VERSION 5.8 ;
BUSBITCHARS "[]" ;
DIVIDERCHAR "/" ;
UNITS
    DATABASE MICRONS 1000 ;
END UNITS

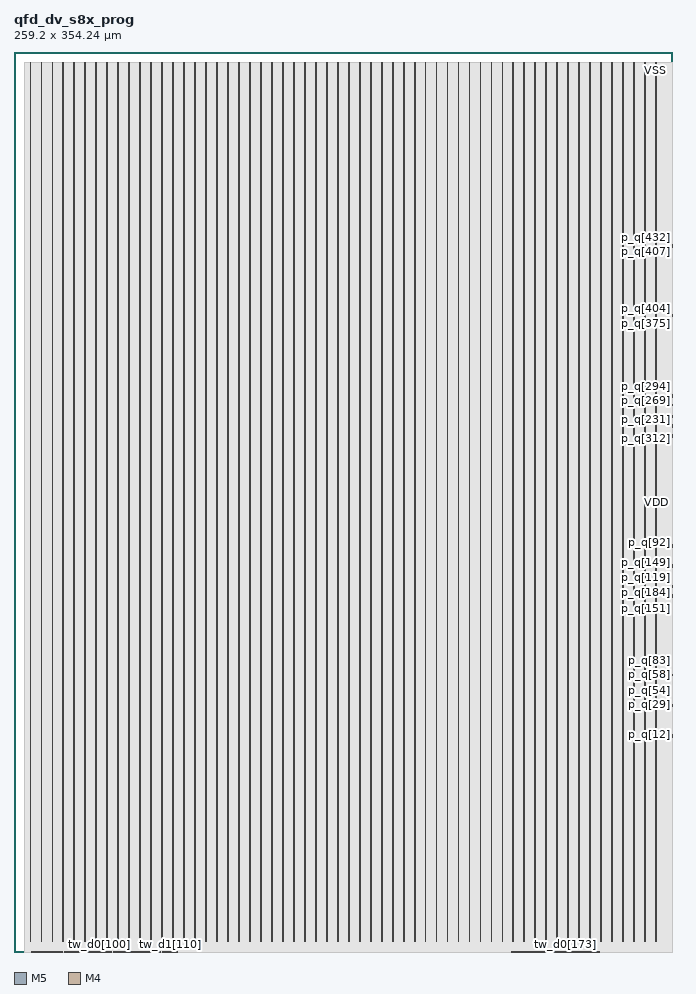
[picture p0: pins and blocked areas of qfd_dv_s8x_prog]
MACRO qfd_dv_s8x_prog
  FOREIGN qfd_dv_s8x_prog 0 0 ;
  CLASS BLOCK ;
  SIZE 259.2 BY 354.24 ;
  PIN ck
    DIRECTION INPUT ;
    USE SIGNAL ;
    PORT
      LAYER M5 ;
        RECT  35.28 0 35.304 0.084 ;
    END
  END ck
  PIN p_idx[0]
    DIRECTION INPUT ;
    USE SIGNAL ;
    PORT
      LAYER M4 ;
        RECT  259.116 83.664 259.2 83.688 ;
    END
  END p_idx[0]
  PIN p_idx[1]
    DIRECTION INPUT ;
    USE SIGNAL ;
    PORT
      LAYER M4 ;
        RECT  259.116 83.76 259.2 83.784 ;
    END
  END p_idx[1]
  PIN p_idx[2]
    DIRECTION INPUT ;
    USE SIGNAL ;
    PORT
      LAYER M4 ;
        RECT  259.116 83.856 259.2 83.88 ;
    END
  END p_idx[2]
  PIN p_idx[3]
    DIRECTION INPUT ;
    USE SIGNAL ;
    PORT
      LAYER M4 ;
        RECT  259.116 83.952 259.2 83.976 ;
    END
  END p_idx[3]
  PIN p_idx[4]
    DIRECTION INPUT ;
    USE SIGNAL ;
    PORT
      LAYER M4 ;
        RECT  259.116 84.048 259.2 84.072 ;
    END
  END p_idx[4]
  PIN p_idx[5]
    DIRECTION INPUT ;
    USE SIGNAL ;
    PORT
      LAYER M4 ;
        RECT  259.116 84.144 259.2 84.168 ;
    END
  END p_idx[5]
  PIN p_idx[6]
    DIRECTION INPUT ;
    USE SIGNAL ;
    PORT
      LAYER M4 ;
        RECT  259.116 84.24 259.2 84.264 ;
    END
  END p_idx[6]
  PIN p_idx[7]
    DIRECTION INPUT ;
    USE SIGNAL ;
    PORT
      LAYER M4 ;
        RECT  259.116 84.336 259.2 84.36 ;
    END
  END p_idx[7]
  PIN p_idx[8]
    DIRECTION INPUT ;
    USE SIGNAL ;
    PORT
      LAYER M4 ;
        RECT  259.116 84.432 259.2 84.456 ;
    END
  END p_idx[8]
  PIN p_q[0]
    DIRECTION OUTPUT ;
    USE SIGNAL ;
    PORT
      LAYER M4 ;
        RECT  259.116 84.528 259.2 84.552 ;
    END
  END p_q[0]
  PIN p_q[100]
    DIRECTION OUTPUT ;
    USE SIGNAL ;
    PORT
      LAYER M4 ;
        RECT  259.116 158.64 259.2 158.664 ;
    END
  END p_q[100]
  PIN p_q[101]
    DIRECTION OUTPUT ;
    USE SIGNAL ;
    PORT
      LAYER M4 ;
        RECT  259.116 158.736 259.2 158.76 ;
    END
  END p_q[101]
  PIN p_q[102]
    DIRECTION OUTPUT ;
    USE SIGNAL ;
    PORT
      LAYER M4 ;
        RECT  259.116 158.832 259.2 158.856 ;
    END
  END p_q[102]
  PIN p_q[103]
    DIRECTION OUTPUT ;
    USE SIGNAL ;
    PORT
      LAYER M4 ;
        RECT  259.116 158.928 259.2 158.952 ;
    END
  END p_q[103]
  PIN p_q[104]
    DIRECTION OUTPUT ;
    USE SIGNAL ;
    PORT
      LAYER M4 ;
        RECT  259.116 159.024 259.2 159.048 ;
    END
  END p_q[104]
  PIN p_q[105]
    DIRECTION OUTPUT ;
    USE SIGNAL ;
    PORT
      LAYER M4 ;
        RECT  259.116 159.12 259.2 159.144 ;
    END
  END p_q[105]
  PIN p_q[106]
    DIRECTION OUTPUT ;
    USE SIGNAL ;
    PORT
      LAYER M4 ;
        RECT  259.116 159.216 259.2 159.24 ;
    END
  END p_q[106]
  PIN p_q[107]
    DIRECTION OUTPUT ;
    USE SIGNAL ;
    PORT
      LAYER M4 ;
        RECT  259.116 159.312 259.2 159.336 ;
    END
  END p_q[107]
  PIN p_q[108]
    DIRECTION OUTPUT ;
    USE SIGNAL ;
    PORT
      LAYER M4 ;
        RECT  259.116 159.408 259.2 159.432 ;
    END
  END p_q[108]
  PIN p_q[109]
    DIRECTION OUTPUT ;
    USE SIGNAL ;
    PORT
      LAYER M4 ;
        RECT  259.116 159.504 259.2 159.528 ;
    END
  END p_q[109]
  PIN p_q[10]
    DIRECTION OUTPUT ;
    USE SIGNAL ;
    PORT
      LAYER M4 ;
        RECT  259.116 85.488 259.2 85.512 ;
    END
  END p_q[10]
  PIN p_q[110]
    DIRECTION OUTPUT ;
    USE SIGNAL ;
    PORT
      LAYER M4 ;
        RECT  259.116 159.6 259.2 159.624 ;
    END
  END p_q[110]
  PIN p_q[111]
    DIRECTION OUTPUT ;
    USE SIGNAL ;
    PORT
      LAYER M4 ;
        RECT  259.116 159.696 259.2 159.72 ;
    END
  END p_q[111]
  PIN p_q[112]
    DIRECTION OUTPUT ;
    USE SIGNAL ;
    PORT
      LAYER M4 ;
        RECT  259.116 159.792 259.2 159.816 ;
    END
  END p_q[112]
  PIN p_q[113]
    DIRECTION OUTPUT ;
    USE SIGNAL ;
    PORT
      LAYER M4 ;
        RECT  259.116 159.888 259.2 159.912 ;
    END
  END p_q[113]
  PIN p_q[114]
    DIRECTION OUTPUT ;
    USE SIGNAL ;
    PORT
      LAYER M4 ;
        RECT  259.116 159.984 259.2 160.008 ;
    END
  END p_q[114]
  PIN p_q[115]
    DIRECTION OUTPUT ;
    USE SIGNAL ;
    PORT
      LAYER M4 ;
        RECT  259.116 160.08 259.2 160.104 ;
    END
  END p_q[115]
  PIN p_q[116]
    DIRECTION OUTPUT ;
    USE SIGNAL ;
    PORT
      LAYER M4 ;
        RECT  259.116 160.176 259.2 160.2 ;
    END
  END p_q[116]
  PIN p_q[117]
    DIRECTION OUTPUT ;
    USE SIGNAL ;
    PORT
      LAYER M4 ;
        RECT  259.116 160.272 259.2 160.296 ;
    END
  END p_q[117]
  PIN p_q[118]
    DIRECTION OUTPUT ;
    USE SIGNAL ;
    PORT
      LAYER M4 ;
        RECT  259.116 160.368 259.2 160.392 ;
    END
  END p_q[118]
  PIN p_q[119]
    DIRECTION OUTPUT ;
    USE SIGNAL ;
    PORT
      LAYER M4 ;
        RECT  259.116 150.48 259.2 150.504 ;
    END
  END p_q[119]
  PIN p_q[11]
    DIRECTION OUTPUT ;
    USE SIGNAL ;
    PORT
      LAYER M4 ;
        RECT  259.116 85.584 259.2 85.608 ;
    END
  END p_q[11]
  PIN p_q[120]
    DIRECTION OUTPUT ;
    USE SIGNAL ;
    PORT
      LAYER M4 ;
        RECT  259.116 150.576 259.2 150.6 ;
    END
  END p_q[120]
  PIN p_q[121]
    DIRECTION OUTPUT ;
    USE SIGNAL ;
    PORT
      LAYER M4 ;
        RECT  259.116 150.672 259.2 150.696 ;
    END
  END p_q[121]
  PIN p_q[122]
    DIRECTION OUTPUT ;
    USE SIGNAL ;
    PORT
      LAYER M4 ;
        RECT  259.116 150.768 259.2 150.792 ;
    END
  END p_q[122]
  PIN p_q[123]
    DIRECTION OUTPUT ;
    USE SIGNAL ;
    PORT
      LAYER M4 ;
        RECT  259.116 150.864 259.2 150.888 ;
    END
  END p_q[123]
  PIN p_q[124]
    DIRECTION OUTPUT ;
    USE SIGNAL ;
    PORT
      LAYER M4 ;
        RECT  259.116 150.96 259.2 150.984 ;
    END
  END p_q[124]
  PIN p_q[125]
    DIRECTION OUTPUT ;
    USE SIGNAL ;
    PORT
      LAYER M4 ;
        RECT  259.116 151.056 259.2 151.08 ;
    END
  END p_q[125]
  PIN p_q[126]
    DIRECTION OUTPUT ;
    USE SIGNAL ;
    PORT
      LAYER M4 ;
        RECT  259.116 151.152 259.2 151.176 ;
    END
  END p_q[126]
  PIN p_q[127]
    DIRECTION OUTPUT ;
    USE SIGNAL ;
    PORT
      LAYER M4 ;
        RECT  259.116 151.248 259.2 151.272 ;
    END
  END p_q[127]
  PIN p_q[128]
    DIRECTION OUTPUT ;
    USE SIGNAL ;
    PORT
      LAYER M4 ;
        RECT  259.116 151.344 259.2 151.368 ;
    END
  END p_q[128]
  PIN p_q[129]
    DIRECTION OUTPUT ;
    USE SIGNAL ;
    PORT
      LAYER M4 ;
        RECT  259.116 151.44 259.2 151.464 ;
    END
  END p_q[129]
  PIN p_q[12]
    DIRECTION OUTPUT ;
    USE SIGNAL ;
    PORT
      LAYER M4 ;
        RECT  259.116 85.68 259.2 85.704 ;
    END
  END p_q[12]
  PIN p_q[130]
    DIRECTION OUTPUT ;
    USE SIGNAL ;
    PORT
      LAYER M4 ;
        RECT  259.116 151.536 259.2 151.56 ;
    END
  END p_q[130]
  PIN p_q[131]
    DIRECTION OUTPUT ;
    USE SIGNAL ;
    PORT
      LAYER M4 ;
        RECT  259.116 151.632 259.2 151.656 ;
    END
  END p_q[131]
  PIN p_q[132]
    DIRECTION OUTPUT ;
    USE SIGNAL ;
    PORT
      LAYER M4 ;
        RECT  259.116 151.728 259.2 151.752 ;
    END
  END p_q[132]
  PIN p_q[133]
    DIRECTION OUTPUT ;
    USE SIGNAL ;
    PORT
      LAYER M4 ;
        RECT  259.116 151.824 259.2 151.848 ;
    END
  END p_q[133]
  PIN p_q[134]
    DIRECTION OUTPUT ;
    USE SIGNAL ;
    PORT
      LAYER M4 ;
        RECT  259.116 151.92 259.2 151.944 ;
    END
  END p_q[134]
  PIN p_q[135]
    DIRECTION OUTPUT ;
    USE SIGNAL ;
    PORT
      LAYER M4 ;
        RECT  259.116 152.016 259.2 152.04 ;
    END
  END p_q[135]
  PIN p_q[136]
    DIRECTION OUTPUT ;
    USE SIGNAL ;
    PORT
      LAYER M4 ;
        RECT  259.116 152.112 259.2 152.136 ;
    END
  END p_q[136]
  PIN p_q[137]
    DIRECTION OUTPUT ;
    USE SIGNAL ;
    PORT
      LAYER M4 ;
        RECT  259.116 152.208 259.2 152.232 ;
    END
  END p_q[137]
  PIN p_q[138]
    DIRECTION OUTPUT ;
    USE SIGNAL ;
    PORT
      LAYER M4 ;
        RECT  259.116 152.304 259.2 152.328 ;
    END
  END p_q[138]
  PIN p_q[139]
    DIRECTION OUTPUT ;
    USE SIGNAL ;
    PORT
      LAYER M4 ;
        RECT  259.116 152.4 259.2 152.424 ;
    END
  END p_q[139]
  PIN p_q[13]
    DIRECTION OUTPUT ;
    USE SIGNAL ;
    PORT
      LAYER M4 ;
        RECT  259.116 85.776 259.2 85.8 ;
    END
  END p_q[13]
  PIN p_q[140]
    DIRECTION OUTPUT ;
    USE SIGNAL ;
    PORT
      LAYER M4 ;
        RECT  259.116 152.496 259.2 152.52 ;
    END
  END p_q[140]
  PIN p_q[141]
    DIRECTION OUTPUT ;
    USE SIGNAL ;
    PORT
      LAYER M4 ;
        RECT  259.116 152.592 259.2 152.616 ;
    END
  END p_q[141]
  PIN p_q[142]
    DIRECTION OUTPUT ;
    USE SIGNAL ;
    PORT
      LAYER M4 ;
        RECT  259.116 152.688 259.2 152.712 ;
    END
  END p_q[142]
  PIN p_q[143]
    DIRECTION OUTPUT ;
    USE SIGNAL ;
    PORT
      LAYER M4 ;
        RECT  259.116 152.784 259.2 152.808 ;
    END
  END p_q[143]
  PIN p_q[144]
    DIRECTION OUTPUT ;
    USE SIGNAL ;
    PORT
      LAYER M4 ;
        RECT  259.116 152.88 259.2 152.904 ;
    END
  END p_q[144]
  PIN p_q[145]
    DIRECTION OUTPUT ;
    USE SIGNAL ;
    PORT
      LAYER M4 ;
        RECT  259.116 152.976 259.2 153 ;
    END
  END p_q[145]
  PIN p_q[146]
    DIRECTION OUTPUT ;
    USE SIGNAL ;
    PORT
      LAYER M4 ;
        RECT  259.116 153.072 259.2 153.096 ;
    END
  END p_q[146]
  PIN p_q[147]
    DIRECTION OUTPUT ;
    USE SIGNAL ;
    PORT
      LAYER M4 ;
        RECT  259.116 153.168 259.2 153.192 ;
    END
  END p_q[147]
  PIN p_q[148]
    DIRECTION OUTPUT ;
    USE SIGNAL ;
    PORT
      LAYER M4 ;
        RECT  259.116 153.264 259.2 153.288 ;
    END
  END p_q[148]
  PIN p_q[149]
    DIRECTION OUTPUT ;
    USE SIGNAL ;
    PORT
      LAYER M4 ;
        RECT  259.116 153.36 259.2 153.384 ;
    END
  END p_q[149]
  PIN p_q[14]
    DIRECTION OUTPUT ;
    USE SIGNAL ;
    PORT
      LAYER M4 ;
        RECT  259.116 85.872 259.2 85.896 ;
    END
  END p_q[14]
  PIN p_q[150]
    DIRECTION OUTPUT ;
    USE SIGNAL ;
    PORT
      LAYER M4 ;
        RECT  259.116 153.456 259.2 153.48 ;
    END
  END p_q[150]
  PIN p_q[151]
    DIRECTION OUTPUT ;
    USE SIGNAL ;
    PORT
      LAYER M4 ;
        RECT  259.116 138.192 259.2 138.216 ;
    END
  END p_q[151]
  PIN p_q[152]
    DIRECTION OUTPUT ;
    USE SIGNAL ;
    PORT
      LAYER M4 ;
        RECT  259.116 138.288 259.2 138.312 ;
    END
  END p_q[152]
  PIN p_q[153]
    DIRECTION OUTPUT ;
    USE SIGNAL ;
    PORT
      LAYER M4 ;
        RECT  259.116 138.384 259.2 138.408 ;
    END
  END p_q[153]
  PIN p_q[154]
    DIRECTION OUTPUT ;
    USE SIGNAL ;
    PORT
      LAYER M4 ;
        RECT  259.116 138.48 259.2 138.504 ;
    END
  END p_q[154]
  PIN p_q[155]
    DIRECTION OUTPUT ;
    USE SIGNAL ;
    PORT
      LAYER M4 ;
        RECT  259.116 138.576 259.2 138.6 ;
    END
  END p_q[155]
  PIN p_q[156]
    DIRECTION OUTPUT ;
    USE SIGNAL ;
    PORT
      LAYER M4 ;
        RECT  259.116 138.672 259.2 138.696 ;
    END
  END p_q[156]
  PIN p_q[157]
    DIRECTION OUTPUT ;
    USE SIGNAL ;
    PORT
      LAYER M4 ;
        RECT  259.116 138.768 259.2 138.792 ;
    END
  END p_q[157]
  PIN p_q[158]
    DIRECTION OUTPUT ;
    USE SIGNAL ;
    PORT
      LAYER M4 ;
        RECT  259.116 138.864 259.2 138.888 ;
    END
  END p_q[158]
  PIN p_q[159]
    DIRECTION OUTPUT ;
    USE SIGNAL ;
    PORT
      LAYER M4 ;
        RECT  259.116 138.96 259.2 138.984 ;
    END
  END p_q[159]
  PIN p_q[15]
    DIRECTION OUTPUT ;
    USE SIGNAL ;
    PORT
      LAYER M4 ;
        RECT  259.116 85.968 259.2 85.992 ;
    END
  END p_q[15]
  PIN p_q[160]
    DIRECTION OUTPUT ;
    USE SIGNAL ;
    PORT
      LAYER M4 ;
        RECT  259.116 139.056 259.2 139.08 ;
    END
  END p_q[160]
  PIN p_q[161]
    DIRECTION OUTPUT ;
    USE SIGNAL ;
    PORT
      LAYER M4 ;
        RECT  259.116 139.152 259.2 139.176 ;
    END
  END p_q[161]
  PIN p_q[162]
    DIRECTION OUTPUT ;
    USE SIGNAL ;
    PORT
      LAYER M4 ;
        RECT  259.116 139.248 259.2 139.272 ;
    END
  END p_q[162]
  PIN p_q[163]
    DIRECTION OUTPUT ;
    USE SIGNAL ;
    PORT
      LAYER M4 ;
        RECT  259.116 139.344 259.2 139.368 ;
    END
  END p_q[163]
  PIN p_q[164]
    DIRECTION OUTPUT ;
    USE SIGNAL ;
    PORT
      LAYER M4 ;
        RECT  259.116 139.44 259.2 139.464 ;
    END
  END p_q[164]
  PIN p_q[165]
    DIRECTION OUTPUT ;
    USE SIGNAL ;
    PORT
      LAYER M4 ;
        RECT  259.116 139.536 259.2 139.56 ;
    END
  END p_q[165]
  PIN p_q[166]
    DIRECTION OUTPUT ;
    USE SIGNAL ;
    PORT
      LAYER M4 ;
        RECT  259.116 139.632 259.2 139.656 ;
    END
  END p_q[166]
  PIN p_q[167]
    DIRECTION OUTPUT ;
    USE SIGNAL ;
    PORT
      LAYER M4 ;
        RECT  259.116 139.728 259.2 139.752 ;
    END
  END p_q[167]
  PIN p_q[168]
    DIRECTION OUTPUT ;
    USE SIGNAL ;
    PORT
      LAYER M4 ;
        RECT  259.116 139.824 259.2 139.848 ;
    END
  END p_q[168]
  PIN p_q[169]
    DIRECTION OUTPUT ;
    USE SIGNAL ;
    PORT
      LAYER M4 ;
        RECT  259.116 139.92 259.2 139.944 ;
    END
  END p_q[169]
  PIN p_q[16]
    DIRECTION OUTPUT ;
    USE SIGNAL ;
    PORT
      LAYER M4 ;
        RECT  259.116 86.064 259.2 86.088 ;
    END
  END p_q[16]
  PIN p_q[170]
    DIRECTION OUTPUT ;
    USE SIGNAL ;
    PORT
      LAYER M4 ;
        RECT  259.116 140.016 259.2 140.04 ;
    END
  END p_q[170]
  PIN p_q[171]
    DIRECTION OUTPUT ;
    USE SIGNAL ;
    PORT
      LAYER M4 ;
        RECT  259.116 140.112 259.2 140.136 ;
    END
  END p_q[171]
  PIN p_q[172]
    DIRECTION OUTPUT ;
    USE SIGNAL ;
    PORT
      LAYER M4 ;
        RECT  259.116 140.208 259.2 140.232 ;
    END
  END p_q[172]
  PIN p_q[173]
    DIRECTION OUTPUT ;
    USE SIGNAL ;
    PORT
      LAYER M4 ;
        RECT  259.116 140.304 259.2 140.328 ;
    END
  END p_q[173]
  PIN p_q[174]
    DIRECTION OUTPUT ;
    USE SIGNAL ;
    PORT
      LAYER M4 ;
        RECT  259.116 140.4 259.2 140.424 ;
    END
  END p_q[174]
  PIN p_q[175]
    DIRECTION OUTPUT ;
    USE SIGNAL ;
    PORT
      LAYER M4 ;
        RECT  259.116 140.496 259.2 140.52 ;
    END
  END p_q[175]
  PIN p_q[176]
    DIRECTION OUTPUT ;
    USE SIGNAL ;
    PORT
      LAYER M4 ;
        RECT  259.116 140.592 259.2 140.616 ;
    END
  END p_q[176]
  PIN p_q[177]
    DIRECTION OUTPUT ;
    USE SIGNAL ;
    PORT
      LAYER M4 ;
        RECT  259.116 140.688 259.2 140.712 ;
    END
  END p_q[177]
  PIN p_q[178]
    DIRECTION OUTPUT ;
    USE SIGNAL ;
    PORT
      LAYER M4 ;
        RECT  259.116 140.784 259.2 140.808 ;
    END
  END p_q[178]
  PIN p_q[179]
    DIRECTION OUTPUT ;
    USE SIGNAL ;
    PORT
      LAYER M4 ;
        RECT  259.116 140.88 259.2 140.904 ;
    END
  END p_q[179]
  PIN p_q[17]
    DIRECTION OUTPUT ;
    USE SIGNAL ;
    PORT
      LAYER M4 ;
        RECT  259.116 86.16 259.2 86.184 ;
    END
  END p_q[17]
  PIN p_q[180]
    DIRECTION OUTPUT ;
    USE SIGNAL ;
    PORT
      LAYER M4 ;
        RECT  259.116 140.976 259.2 141 ;
    END
  END p_q[180]
  PIN p_q[181]
    DIRECTION OUTPUT ;
    USE SIGNAL ;
    PORT
      LAYER M4 ;
        RECT  259.116 141.072 259.2 141.096 ;
    END
  END p_q[181]
  PIN p_q[182]
    DIRECTION OUTPUT ;
    USE SIGNAL ;
    PORT
      LAYER M4 ;
        RECT  259.116 141.168 259.2 141.192 ;
    END
  END p_q[182]
  PIN p_q[183]
    DIRECTION OUTPUT ;
    USE SIGNAL ;
    PORT
      LAYER M4 ;
        RECT  259.116 141.264 259.2 141.288 ;
    END
  END p_q[183]
  PIN p_q[184]
    DIRECTION OUTPUT ;
    USE SIGNAL ;
    PORT
      LAYER M4 ;
        RECT  259.116 141.36 259.2 141.384 ;
    END
  END p_q[184]
  PIN p_q[185]
    DIRECTION OUTPUT ;
    USE SIGNAL ;
    PORT
      LAYER M4 ;
        RECT  259.116 141.456 259.2 141.48 ;
    END
  END p_q[185]
  PIN p_q[186]
    DIRECTION OUTPUT ;
    USE SIGNAL ;
    PORT
      LAYER M4 ;
        RECT  259.116 141.552 259.2 141.576 ;
    END
  END p_q[186]
  PIN p_q[187]
    DIRECTION OUTPUT ;
    USE SIGNAL ;
    PORT
      LAYER M4 ;
        RECT  259.116 141.648 259.2 141.672 ;
    END
  END p_q[187]
  PIN p_q[188]
    DIRECTION OUTPUT ;
    USE SIGNAL ;
    PORT
      LAYER M4 ;
        RECT  259.116 141.744 259.2 141.768 ;
    END
  END p_q[188]
  PIN p_q[189]
    DIRECTION OUTPUT ;
    USE SIGNAL ;
    PORT
      LAYER M4 ;
        RECT  259.116 141.84 259.2 141.864 ;
    END
  END p_q[189]
  PIN p_q[18]
    DIRECTION OUTPUT ;
    USE SIGNAL ;
    PORT
      LAYER M4 ;
        RECT  259.116 86.256 259.2 86.28 ;
    END
  END p_q[18]
  PIN p_q[190]
    DIRECTION OUTPUT ;
    USE SIGNAL ;
    PORT
      LAYER M4 ;
        RECT  259.116 141.936 259.2 141.96 ;
    END
  END p_q[190]
  PIN p_q[191]
    DIRECTION OUTPUT ;
    USE SIGNAL ;
    PORT
      LAYER M4 ;
        RECT  259.116 142.032 259.2 142.056 ;
    END
  END p_q[191]
  PIN p_q[192]
    DIRECTION OUTPUT ;
    USE SIGNAL ;
    PORT
      LAYER M4 ;
        RECT  259.116 142.128 259.2 142.152 ;
    END
  END p_q[192]
  PIN p_q[193]
    DIRECTION OUTPUT ;
    USE SIGNAL ;
    PORT
      LAYER M4 ;
        RECT  259.116 142.224 259.2 142.248 ;
    END
  END p_q[193]
  PIN p_q[194]
    DIRECTION OUTPUT ;
    USE SIGNAL ;
    PORT
      LAYER M4 ;
        RECT  259.116 142.32 259.2 142.344 ;
    END
  END p_q[194]
  PIN p_q[195]
    DIRECTION OUTPUT ;
    USE SIGNAL ;
    PORT
      LAYER M4 ;
        RECT  259.116 142.416 259.2 142.44 ;
    END
  END p_q[195]
  PIN p_q[196]
    DIRECTION OUTPUT ;
    USE SIGNAL ;
    PORT
      LAYER M4 ;
        RECT  259.116 142.512 259.2 142.536 ;
    END
  END p_q[196]
  PIN p_q[197]
    DIRECTION OUTPUT ;
    USE SIGNAL ;
    PORT
      LAYER M4 ;
        RECT  259.116 142.608 259.2 142.632 ;
    END
  END p_q[197]
  PIN p_q[198]
    DIRECTION OUTPUT ;
    USE SIGNAL ;
    PORT
      LAYER M4 ;
        RECT  259.116 142.704 259.2 142.728 ;
    END
  END p_q[198]
  PIN p_q[199]
    DIRECTION OUTPUT ;
    USE SIGNAL ;
    PORT
      LAYER M4 ;
        RECT  259.116 142.8 259.2 142.824 ;
    END
  END p_q[199]
  PIN p_q[19]
    DIRECTION OUTPUT ;
    USE SIGNAL ;
    PORT
      LAYER M4 ;
        RECT  259.116 86.352 259.2 86.376 ;
    END
  END p_q[19]
  PIN p_q[1]
    DIRECTION OUTPUT ;
    USE SIGNAL ;
    PORT
      LAYER M4 ;
        RECT  259.116 84.624 259.2 84.648 ;
    END
  END p_q[1]
  PIN p_q[200]
    DIRECTION OUTPUT ;
    USE SIGNAL ;
    PORT
      LAYER M4 ;
        RECT  259.116 142.896 259.2 142.92 ;
    END
  END p_q[200]
  PIN p_q[201]
    DIRECTION OUTPUT ;
    USE SIGNAL ;
    PORT
      LAYER M4 ;
        RECT  259.116 142.992 259.2 143.016 ;
    END
  END p_q[201]
  PIN p_q[202]
    DIRECTION OUTPUT ;
    USE SIGNAL ;
    PORT
      LAYER M4 ;
        RECT  259.116 143.088 259.2 143.112 ;
    END
  END p_q[202]
  PIN p_q[203]
    DIRECTION OUTPUT ;
    USE SIGNAL ;
    PORT
      LAYER M4 ;
        RECT  259.116 143.184 259.2 143.208 ;
    END
  END p_q[203]
  PIN p_q[204]
    DIRECTION OUTPUT ;
    USE SIGNAL ;
    PORT
      LAYER M4 ;
        RECT  259.116 143.28 259.2 143.304 ;
    END
  END p_q[204]
  PIN p_q[205]
    DIRECTION OUTPUT ;
    USE SIGNAL ;
    PORT
      LAYER M4 ;
        RECT  259.116 143.376 259.2 143.4 ;
    END
  END p_q[205]
  PIN p_q[206]
    DIRECTION OUTPUT ;
    USE SIGNAL ;
    PORT
      LAYER M4 ;
        RECT  259.116 143.472 259.2 143.496 ;
    END
  END p_q[206]
  PIN p_q[207]
    DIRECTION OUTPUT ;
    USE SIGNAL ;
    PORT
      LAYER M4 ;
        RECT  259.116 143.568 259.2 143.592 ;
    END
  END p_q[207]
  PIN p_q[208]
    DIRECTION OUTPUT ;
    USE SIGNAL ;
    PORT
      LAYER M4 ;
        RECT  259.116 143.664 259.2 143.688 ;
    END
  END p_q[208]
  PIN p_q[209]
    DIRECTION OUTPUT ;
    USE SIGNAL ;
    PORT
      LAYER M4 ;
        RECT  259.116 143.76 259.2 143.784 ;
    END
  END p_q[209]
  PIN p_q[20]
    DIRECTION OUTPUT ;
    USE SIGNAL ;
    PORT
      LAYER M4 ;
        RECT  259.116 86.448 259.2 86.472 ;
    END
  END p_q[20]
  PIN p_q[210]
    DIRECTION OUTPUT ;
    USE SIGNAL ;
    PORT
      LAYER M4 ;
        RECT  259.116 143.856 259.2 143.88 ;
    END
  END p_q[210]
  PIN p_q[211]
    DIRECTION OUTPUT ;
    USE SIGNAL ;
    PORT
      LAYER M4 ;
        RECT  259.116 143.952 259.2 143.976 ;
    END
  END p_q[211]
  PIN p_q[212]
    DIRECTION OUTPUT ;
    USE SIGNAL ;
    PORT
      LAYER M4 ;
        RECT  259.116 144.048 259.2 144.072 ;
    END
  END p_q[212]
  PIN p_q[213]
    DIRECTION OUTPUT ;
    USE SIGNAL ;
    PORT
      LAYER M4 ;
        RECT  259.116 144.144 259.2 144.168 ;
    END
  END p_q[213]
  PIN p_q[214]
    DIRECTION OUTPUT ;
    USE SIGNAL ;
    PORT
      LAYER M4 ;
        RECT  259.116 144.24 259.2 144.264 ;
    END
  END p_q[214]
  PIN p_q[215]
    DIRECTION OUTPUT ;
    USE SIGNAL ;
    PORT
      LAYER M4 ;
        RECT  259.116 208.08 259.2 208.104 ;
    END
  END p_q[215]
  PIN p_q[216]
    DIRECTION OUTPUT ;
    USE SIGNAL ;
    PORT
      LAYER M4 ;
        RECT  259.116 208.176 259.2 208.2 ;
    END
  END p_q[216]
  PIN p_q[217]
    DIRECTION OUTPUT ;
    USE SIGNAL ;
    PORT
      LAYER M4 ;
        RECT  259.116 208.272 259.2 208.296 ;
    END
  END p_q[217]
  PIN p_q[218]
    DIRECTION OUTPUT ;
    USE SIGNAL ;
    PORT
      LAYER M4 ;
        RECT  259.116 208.368 259.2 208.392 ;
    END
  END p_q[218]
  PIN p_q[219]
    DIRECTION OUTPUT ;
    USE SIGNAL ;
    PORT
      LAYER M4 ;
        RECT  259.116 208.464 259.2 208.488 ;
    END
  END p_q[219]
  PIN p_q[21]
    DIRECTION OUTPUT ;
    USE SIGNAL ;
    PORT
      LAYER M4 ;
        RECT  259.116 86.544 259.2 86.568 ;
    END
  END p_q[21]
  PIN p_q[220]
    DIRECTION OUTPUT ;
    USE SIGNAL ;
    PORT
      LAYER M4 ;
        RECT  259.116 208.56 259.2 208.584 ;
    END
  END p_q[220]
  PIN p_q[221]
    DIRECTION OUTPUT ;
    USE SIGNAL ;
    PORT
      LAYER M4 ;
        RECT  259.116 208.656 259.2 208.68 ;
    END
  END p_q[221]
  PIN p_q[222]
    DIRECTION OUTPUT ;
    USE SIGNAL ;
    PORT
      LAYER M4 ;
        RECT  259.116 208.752 259.2 208.776 ;
    END
  END p_q[222]
  PIN p_q[223]
    DIRECTION OUTPUT ;
    USE SIGNAL ;
    PORT
      LAYER M4 ;
        RECT  259.116 208.848 259.2 208.872 ;
    END
  END p_q[223]
  PIN p_q[224]
    DIRECTION OUTPUT ;
    USE SIGNAL ;
    PORT
      LAYER M4 ;
        RECT  259.116 208.944 259.2 208.968 ;
    END
  END p_q[224]
  PIN p_q[225]
    DIRECTION OUTPUT ;
    USE SIGNAL ;
    PORT
      LAYER M4 ;
        RECT  259.116 209.04 259.2 209.064 ;
    END
  END p_q[225]
  PIN p_q[226]
    DIRECTION OUTPUT ;
    USE SIGNAL ;
    PORT
      LAYER M4 ;
        RECT  259.116 209.136 259.2 209.16 ;
    END
  END p_q[226]
  PIN p_q[227]
    DIRECTION OUTPUT ;
    USE SIGNAL ;
    PORT
      LAYER M4 ;
        RECT  259.116 209.232 259.2 209.256 ;
    END
  END p_q[227]
  PIN p_q[228]
    DIRECTION OUTPUT ;
    USE SIGNAL ;
    PORT
      LAYER M4 ;
        RECT  259.116 209.328 259.2 209.352 ;
    END
  END p_q[228]
  PIN p_q[229]
    DIRECTION OUTPUT ;
    USE SIGNAL ;
    PORT
      LAYER M4 ;
        RECT  259.116 209.424 259.2 209.448 ;
    END
  END p_q[229]
  PIN p_q[22]
    DIRECTION OUTPUT ;
    USE SIGNAL ;
    PORT
      LAYER M4 ;
        RECT  259.116 86.64 259.2 86.664 ;
    END
  END p_q[22]
  PIN p_q[230]
    DIRECTION OUTPUT ;
    USE SIGNAL ;
    PORT
      LAYER M4 ;
        RECT  259.116 209.52 259.2 209.544 ;
    END
  END p_q[230]
  PIN p_q[231]
    DIRECTION OUTPUT ;
    USE SIGNAL ;
    PORT
      LAYER M4 ;
        RECT  259.116 209.616 259.2 209.64 ;
    END
  END p_q[231]
  PIN p_q[232]
    DIRECTION OUTPUT ;
    USE SIGNAL ;
    PORT
      LAYER M4 ;
        RECT  259.116 209.712 259.2 209.736 ;
    END
  END p_q[232]
  PIN p_q[233]
    DIRECTION OUTPUT ;
    USE SIGNAL ;
    PORT
      LAYER M4 ;
        RECT  259.116 209.808 259.2 209.832 ;
    END
  END p_q[233]
  PIN p_q[234]
    DIRECTION OUTPUT ;
    USE SIGNAL ;
    PORT
      LAYER M4 ;
        RECT  259.116 209.904 259.2 209.928 ;
    END
  END p_q[234]
  PIN p_q[235]
    DIRECTION OUTPUT ;
    USE SIGNAL ;
    PORT
      LAYER M4 ;
        RECT  259.116 210 259.2 210.024 ;
    END
  END p_q[235]
  PIN p_q[236]
    DIRECTION OUTPUT ;
    USE SIGNAL ;
    PORT
      LAYER M4 ;
        RECT  259.116 210.096 259.2 210.12 ;
    END
  END p_q[236]
  PIN p_q[237]
    DIRECTION OUTPUT ;
    USE SIGNAL ;
    PORT
      LAYER M4 ;
        RECT  259.116 210.192 259.2 210.216 ;
    END
  END p_q[237]
  PIN p_q[238]
    DIRECTION OUTPUT ;
    USE SIGNAL ;
    PORT
      LAYER M4 ;
        RECT  259.116 210.288 259.2 210.312 ;
    END
  END p_q[238]
  PIN p_q[239]
    DIRECTION OUTPUT ;
    USE SIGNAL ;
    PORT
      LAYER M4 ;
        RECT  259.116 210.384 259.2 210.408 ;
    END
  END p_q[239]
  PIN p_q[23]
    DIRECTION OUTPUT ;
    USE SIGNAL ;
    PORT
      LAYER M4 ;
        RECT  259.116 96.72 259.2 96.744 ;
    END
  END p_q[23]
  PIN p_q[240]
    DIRECTION OUTPUT ;
    USE SIGNAL ;
    PORT
      LAYER M4 ;
        RECT  259.116 210.48 259.2 210.504 ;
    END
  END p_q[240]
  PIN p_q[241]
    DIRECTION OUTPUT ;
    USE SIGNAL ;
    PORT
      LAYER M4 ;
        RECT  259.116 210.576 259.2 210.6 ;
    END
  END p_q[241]
  PIN p_q[242]
    DIRECTION OUTPUT ;
    USE SIGNAL ;
    PORT
      LAYER M4 ;
        RECT  259.116 210.672 259.2 210.696 ;
    END
  END p_q[242]
  PIN p_q[243]
    DIRECTION OUTPUT ;
    USE SIGNAL ;
    PORT
      LAYER M4 ;
        RECT  259.116 210.768 259.2 210.792 ;
    END
  END p_q[243]
  PIN p_q[244]
    DIRECTION OUTPUT ;
    USE SIGNAL ;
    PORT
      LAYER M4 ;
        RECT  259.116 210.864 259.2 210.888 ;
    END
  END p_q[244]
  PIN p_q[245]
    DIRECTION OUTPUT ;
    USE SIGNAL ;
    PORT
      LAYER M4 ;
        RECT  259.116 210.96 259.2 210.984 ;
    END
  END p_q[245]
  PIN p_q[246]
    DIRECTION OUTPUT ;
    USE SIGNAL ;
    PORT
      LAYER M4 ;
        RECT  259.116 211.056 259.2 211.08 ;
    END
  END p_q[246]
  PIN p_q[247]
    DIRECTION OUTPUT ;
    USE SIGNAL ;
    PORT
      LAYER M4 ;
        RECT  259.116 214.992 259.2 215.016 ;
    END
  END p_q[247]
  PIN p_q[248]
    DIRECTION OUTPUT ;
    USE SIGNAL ;
    PORT
      LAYER M4 ;
        RECT  259.116 215.088 259.2 215.112 ;
    END
  END p_q[248]
  PIN p_q[249]
    DIRECTION OUTPUT ;
    USE SIGNAL ;
    PORT
      LAYER M4 ;
        RECT  259.116 215.184 259.2 215.208 ;
    END
  END p_q[249]
  PIN p_q[24]
    DIRECTION OUTPUT ;
    USE SIGNAL ;
    PORT
      LAYER M4 ;
        RECT  259.116 96.816 259.2 96.84 ;
    END
  END p_q[24]
  PIN p_q[250]
    DIRECTION OUTPUT ;
    USE SIGNAL ;
    PORT
      LAYER M4 ;
        RECT  259.116 215.28 259.2 215.304 ;
    END
  END p_q[250]
  PIN p_q[251]
    DIRECTION OUTPUT ;
    USE SIGNAL ;
    PORT
      LAYER M4 ;
        RECT  259.116 215.376 259.2 215.4 ;
    END
  END p_q[251]
  PIN p_q[252]
    DIRECTION OUTPUT ;
    USE SIGNAL ;
    PORT
      LAYER M4 ;
        RECT  259.116 215.472 259.2 215.496 ;
    END
  END p_q[252]
  PIN p_q[253]
    DIRECTION OUTPUT ;
    USE SIGNAL ;
    PORT
      LAYER M4 ;
        RECT  259.116 215.568 259.2 215.592 ;
    END
  END p_q[253]
  PIN p_q[254]
    DIRECTION OUTPUT ;
    USE SIGNAL ;
    PORT
      LAYER M4 ;
        RECT  259.116 215.664 259.2 215.688 ;
    END
  END p_q[254]
  PIN p_q[255]
    DIRECTION OUTPUT ;
    USE SIGNAL ;
    PORT
      LAYER M4 ;
        RECT  259.116 215.76 259.2 215.784 ;
    END
  END p_q[255]
  PIN p_q[256]
    DIRECTION OUTPUT ;
    USE SIGNAL ;
    PORT
      LAYER M4 ;
        RECT  259.116 215.856 259.2 215.88 ;
    END
  END p_q[256]
  PIN p_q[257]
    DIRECTION OUTPUT ;
    USE SIGNAL ;
    PORT
      LAYER M4 ;
        RECT  259.116 215.952 259.2 215.976 ;
    END
  END p_q[257]
  PIN p_q[258]
    DIRECTION OUTPUT ;
    USE SIGNAL ;
    PORT
      LAYER M4 ;
        RECT  259.116 216.048 259.2 216.072 ;
    END
  END p_q[258]
  PIN p_q[259]
    DIRECTION OUTPUT ;
    USE SIGNAL ;
    PORT
      LAYER M4 ;
        RECT  259.116 216.144 259.2 216.168 ;
    END
  END p_q[259]
  PIN p_q[25]
    DIRECTION OUTPUT ;
    USE SIGNAL ;
    PORT
      LAYER M4 ;
        RECT  259.116 96.912 259.2 96.936 ;
    END
  END p_q[25]
  PIN p_q[260]
    DIRECTION OUTPUT ;
    USE SIGNAL ;
    PORT
      LAYER M4 ;
        RECT  259.116 216.24 259.2 216.264 ;
    END
  END p_q[260]
  PIN p_q[261]
    DIRECTION OUTPUT ;
    USE SIGNAL ;
    PORT
      LAYER M4 ;
        RECT  259.116 216.336 259.2 216.36 ;
    END
  END p_q[261]
  PIN p_q[262]
    DIRECTION OUTPUT ;
    USE SIGNAL ;
    PORT
      LAYER M4 ;
        RECT  259.116 216.432 259.2 216.456 ;
    END
  END p_q[262]
  PIN p_q[263]
    DIRECTION OUTPUT ;
    USE SIGNAL ;
    PORT
      LAYER M4 ;
        RECT  259.116 216.528 259.2 216.552 ;
    END
  END p_q[263]
  PIN p_q[264]
    DIRECTION OUTPUT ;
    USE SIGNAL ;
    PORT
      LAYER M4 ;
        RECT  259.116 216.624 259.2 216.648 ;
    END
  END p_q[264]
  PIN p_q[265]
    DIRECTION OUTPUT ;
    USE SIGNAL ;
    PORT
      LAYER M4 ;
        RECT  259.116 216.72 259.2 216.744 ;
    END
  END p_q[265]
  PIN p_q[266]
    DIRECTION OUTPUT ;
    USE SIGNAL ;
    PORT
      LAYER M4 ;
        RECT  259.116 216.816 259.2 216.84 ;
    END
  END p_q[266]
  PIN p_q[267]
    DIRECTION OUTPUT ;
    USE SIGNAL ;
    PORT
      LAYER M4 ;
        RECT  259.116 216.912 259.2 216.936 ;
    END
  END p_q[267]
  PIN p_q[268]
    DIRECTION OUTPUT ;
    USE SIGNAL ;
    PORT
      LAYER M4 ;
        RECT  259.116 217.008 259.2 217.032 ;
    END
  END p_q[268]
  PIN p_q[269]
    DIRECTION OUTPUT ;
    USE SIGNAL ;
    PORT
      LAYER M4 ;
        RECT  259.116 217.104 259.2 217.128 ;
    END
  END p_q[269]
  PIN p_q[26]
    DIRECTION OUTPUT ;
    USE SIGNAL ;
    PORT
      LAYER M4 ;
        RECT  259.116 97.008 259.2 97.032 ;
    END
  END p_q[26]
  PIN p_q[270]
    DIRECTION OUTPUT ;
    USE SIGNAL ;
    PORT
      LAYER M4 ;
        RECT  259.116 217.2 259.2 217.224 ;
    END
  END p_q[270]
  PIN p_q[271]
    DIRECTION OUTPUT ;
    USE SIGNAL ;
    PORT
      LAYER M4 ;
        RECT  259.116 217.296 259.2 217.32 ;
    END
  END p_q[271]
  PIN p_q[272]
    DIRECTION OUTPUT ;
    USE SIGNAL ;
    PORT
      LAYER M4 ;
        RECT  259.116 217.392 259.2 217.416 ;
    END
  END p_q[272]
  PIN p_q[273]
    DIRECTION OUTPUT ;
    USE SIGNAL ;
    PORT
      LAYER M4 ;
        RECT  259.116 217.488 259.2 217.512 ;
    END
  END p_q[273]
  PIN p_q[274]
    DIRECTION OUTPUT ;
    USE SIGNAL ;
    PORT
      LAYER M4 ;
        RECT  259.116 217.584 259.2 217.608 ;
    END
  END p_q[274]
  PIN p_q[275]
    DIRECTION OUTPUT ;
    USE SIGNAL ;
    PORT
      LAYER M4 ;
        RECT  259.116 217.68 259.2 217.704 ;
    END
  END p_q[275]
  PIN p_q[276]
    DIRECTION OUTPUT ;
    USE SIGNAL ;
    PORT
      LAYER M4 ;
        RECT  259.116 217.776 259.2 217.8 ;
    END
  END p_q[276]
  PIN p_q[277]
    DIRECTION OUTPUT ;
    USE SIGNAL ;
    PORT
      LAYER M4 ;
        RECT  259.116 217.872 259.2 217.896 ;
    END
  END p_q[277]
  PIN p_q[278]
    DIRECTION OUTPUT ;
    USE SIGNAL ;
    PORT
      LAYER M4 ;
        RECT  259.116 217.968 259.2 217.992 ;
    END
  END p_q[278]
  PIN p_q[279]
    DIRECTION OUTPUT ;
    USE SIGNAL ;
    PORT
      LAYER M4 ;
        RECT  259.116 218.064 259.2 218.088 ;
    END
  END p_q[279]
  PIN p_q[27]
    DIRECTION OUTPUT ;
    USE SIGNAL ;
    PORT
      LAYER M4 ;
        RECT  259.116 97.104 259.2 97.128 ;
    END
  END p_q[27]
  PIN p_q[280]
    DIRECTION OUTPUT ;
    USE SIGNAL ;
    PORT
      LAYER M4 ;
        RECT  259.116 218.16 259.2 218.184 ;
    END
  END p_q[280]
  PIN p_q[281]
    DIRECTION OUTPUT ;
    USE SIGNAL ;
    PORT
      LAYER M4 ;
        RECT  259.116 218.256 259.2 218.28 ;
    END
  END p_q[281]
  PIN p_q[282]
    DIRECTION OUTPUT ;
    USE SIGNAL ;
    PORT
      LAYER M4 ;
        RECT  259.116 218.352 259.2 218.376 ;
    END
  END p_q[282]
  PIN p_q[283]
    DIRECTION OUTPUT ;
    USE SIGNAL ;
    PORT
      LAYER M4 ;
        RECT  259.116 218.448 259.2 218.472 ;
    END
  END p_q[283]
  PIN p_q[284]
    DIRECTION OUTPUT ;
    USE SIGNAL ;
    PORT
      LAYER M4 ;
        RECT  259.116 218.544 259.2 218.568 ;
    END
  END p_q[284]
  PIN p_q[285]
    DIRECTION OUTPUT ;
    USE SIGNAL ;
    PORT
      LAYER M4 ;
        RECT  259.116 218.64 259.2 218.664 ;
    END
  END p_q[285]
  PIN p_q[286]
    DIRECTION OUTPUT ;
    USE SIGNAL ;
    PORT
      LAYER M4 ;
        RECT  259.116 218.736 259.2 218.76 ;
    END
  END p_q[286]
  PIN p_q[287]
    DIRECTION OUTPUT ;
    USE SIGNAL ;
    PORT
      LAYER M4 ;
        RECT  259.116 218.832 259.2 218.856 ;
    END
  END p_q[287]
  PIN p_q[288]
    DIRECTION OUTPUT ;
    USE SIGNAL ;
    PORT
      LAYER M4 ;
        RECT  259.116 218.928 259.2 218.952 ;
    END
  END p_q[288]
  PIN p_q[289]
    DIRECTION OUTPUT ;
    USE SIGNAL ;
    PORT
      LAYER M4 ;
        RECT  259.116 219.024 259.2 219.048 ;
    END
  END p_q[289]
  PIN p_q[28]
    DIRECTION OUTPUT ;
    USE SIGNAL ;
    PORT
      LAYER M4 ;
        RECT  259.116 97.2 259.2 97.224 ;
    END
  END p_q[28]
  PIN p_q[290]
    DIRECTION OUTPUT ;
    USE SIGNAL ;
    PORT
      LAYER M4 ;
        RECT  259.116 219.12 259.2 219.144 ;
    END
  END p_q[290]
  PIN p_q[291]
    DIRECTION OUTPUT ;
    USE SIGNAL ;
    PORT
      LAYER M4 ;
        RECT  259.116 219.216 259.2 219.24 ;
    END
  END p_q[291]
  PIN p_q[292]
    DIRECTION OUTPUT ;
    USE SIGNAL ;
    PORT
      LAYER M4 ;
        RECT  259.116 219.312 259.2 219.336 ;
    END
  END p_q[292]
  PIN p_q[293]
    DIRECTION OUTPUT ;
    USE SIGNAL ;
    PORT
      LAYER M4 ;
        RECT  259.116 219.408 259.2 219.432 ;
    END
  END p_q[293]
  PIN p_q[294]
    DIRECTION OUTPUT ;
    USE SIGNAL ;
    PORT
      LAYER M4 ;
        RECT  259.116 219.504 259.2 219.528 ;
    END
  END p_q[294]
  PIN p_q[295]
    DIRECTION OUTPUT ;
    USE SIGNAL ;
    PORT
      LAYER M4 ;
        RECT  259.116 219.6 259.2 219.624 ;
    END
  END p_q[295]
  PIN p_q[296]
    DIRECTION OUTPUT ;
    USE SIGNAL ;
    PORT
      LAYER M4 ;
        RECT  259.116 219.696 259.2 219.72 ;
    END
  END p_q[296]
  PIN p_q[297]
    DIRECTION OUTPUT ;
    USE SIGNAL ;
    PORT
      LAYER M4 ;
        RECT  259.116 219.792 259.2 219.816 ;
    END
  END p_q[297]
  PIN p_q[298]
    DIRECTION OUTPUT ;
    USE SIGNAL ;
    PORT
      LAYER M4 ;
        RECT  259.116 219.888 259.2 219.912 ;
    END
  END p_q[298]
  PIN p_q[299]
    DIRECTION OUTPUT ;
    USE SIGNAL ;
    PORT
      LAYER M4 ;
        RECT  259.116 219.984 259.2 220.008 ;
    END
  END p_q[299]
  PIN p_q[29]
    DIRECTION OUTPUT ;
    USE SIGNAL ;
    PORT
      LAYER M4 ;
        RECT  259.116 97.296 259.2 97.32 ;
    END
  END p_q[29]
  PIN p_q[2]
    DIRECTION OUTPUT ;
    USE SIGNAL ;
    PORT
      LAYER M4 ;
        RECT  259.116 84.72 259.2 84.744 ;
    END
  END p_q[2]
  PIN p_q[300]
    DIRECTION OUTPUT ;
    USE SIGNAL ;
    PORT
      LAYER M4 ;
        RECT  259.116 220.08 259.2 220.104 ;
    END
  END p_q[300]
  PIN p_q[301]
    DIRECTION OUTPUT ;
    USE SIGNAL ;
    PORT
      LAYER M4 ;
        RECT  259.116 220.176 259.2 220.2 ;
    END
  END p_q[301]
  PIN p_q[302]
    DIRECTION OUTPUT ;
    USE SIGNAL ;
    PORT
      LAYER M4 ;
        RECT  259.116 220.272 259.2 220.296 ;
    END
  END p_q[302]
  PIN p_q[303]
    DIRECTION OUTPUT ;
    USE SIGNAL ;
    PORT
      LAYER M4 ;
        RECT  259.116 220.368 259.2 220.392 ;
    END
  END p_q[303]
  PIN p_q[304]
    DIRECTION OUTPUT ;
    USE SIGNAL ;
    PORT
      LAYER M4 ;
        RECT  259.116 220.464 259.2 220.488 ;
    END
  END p_q[304]
  PIN p_q[305]
    DIRECTION OUTPUT ;
    USE SIGNAL ;
    PORT
      LAYER M4 ;
        RECT  259.116 220.56 259.2 220.584 ;
    END
  END p_q[305]
  PIN p_q[306]
    DIRECTION OUTPUT ;
    USE SIGNAL ;
    PORT
      LAYER M4 ;
        RECT  259.116 220.656 259.2 220.68 ;
    END
  END p_q[306]
  PIN p_q[307]
    DIRECTION OUTPUT ;
    USE SIGNAL ;
    PORT
      LAYER M4 ;
        RECT  259.116 220.752 259.2 220.776 ;
    END
  END p_q[307]
  PIN p_q[308]
    DIRECTION OUTPUT ;
    USE SIGNAL ;
    PORT
      LAYER M4 ;
        RECT  259.116 220.848 259.2 220.872 ;
    END
  END p_q[308]
  PIN p_q[309]
    DIRECTION OUTPUT ;
    USE SIGNAL ;
    PORT
      LAYER M4 ;
        RECT  259.116 220.944 259.2 220.968 ;
    END
  END p_q[309]
  PIN p_q[30]
    DIRECTION OUTPUT ;
    USE SIGNAL ;
    PORT
      LAYER M4 ;
        RECT  259.116 97.392 259.2 97.416 ;
    END
  END p_q[30]
  PIN p_q[310]
    DIRECTION OUTPUT ;
    USE SIGNAL ;
    PORT
      LAYER M4 ;
        RECT  259.116 221.04 259.2 221.064 ;
    END
  END p_q[310]
  PIN p_q[311]
    DIRECTION OUTPUT ;
    USE SIGNAL ;
    PORT
      LAYER M4 ;
        RECT  259.116 205.008 259.2 205.032 ;
    END
  END p_q[311]
  PIN p_q[312]
    DIRECTION OUTPUT ;
    USE SIGNAL ;
    PORT
      LAYER M4 ;
        RECT  259.116 205.104 259.2 205.128 ;
    END
  END p_q[312]
  PIN p_q[313]
    DIRECTION OUTPUT ;
    USE SIGNAL ;
    PORT
      LAYER M4 ;
        RECT  259.116 205.2 259.2 205.224 ;
    END
  END p_q[313]
  PIN p_q[314]
    DIRECTION OUTPUT ;
    USE SIGNAL ;
    PORT
      LAYER M4 ;
        RECT  259.116 205.296 259.2 205.32 ;
    END
  END p_q[314]
  PIN p_q[315]
    DIRECTION OUTPUT ;
    USE SIGNAL ;
    PORT
      LAYER M4 ;
        RECT  259.116 205.392 259.2 205.416 ;
    END
  END p_q[315]
  PIN p_q[316]
    DIRECTION OUTPUT ;
    USE SIGNAL ;
    PORT
      LAYER M4 ;
        RECT  259.116 205.488 259.2 205.512 ;
    END
  END p_q[316]
  PIN p_q[317]
    DIRECTION OUTPUT ;
    USE SIGNAL ;
    PORT
      LAYER M4 ;
        RECT  259.116 205.584 259.2 205.608 ;
    END
  END p_q[317]
  PIN p_q[318]
    DIRECTION OUTPUT ;
    USE SIGNAL ;
    PORT
      LAYER M4 ;
        RECT  259.116 205.68 259.2 205.704 ;
    END
  END p_q[318]
  PIN p_q[319]
    DIRECTION OUTPUT ;
    USE SIGNAL ;
    PORT
      LAYER M4 ;
        RECT  259.116 205.776 259.2 205.8 ;
    END
  END p_q[319]
  PIN p_q[31]
    DIRECTION OUTPUT ;
    USE SIGNAL ;
    PORT
      LAYER M4 ;
        RECT  259.116 97.488 259.2 97.512 ;
    END
  END p_q[31]
  PIN p_q[320]
    DIRECTION OUTPUT ;
    USE SIGNAL ;
    PORT
      LAYER M4 ;
        RECT  259.116 205.872 259.2 205.896 ;
    END
  END p_q[320]
  PIN p_q[321]
    DIRECTION OUTPUT ;
    USE SIGNAL ;
    PORT
      LAYER M4 ;
        RECT  259.116 205.968 259.2 205.992 ;
    END
  END p_q[321]
  PIN p_q[322]
    DIRECTION OUTPUT ;
    USE SIGNAL ;
    PORT
      LAYER M4 ;
        RECT  259.116 206.064 259.2 206.088 ;
    END
  END p_q[322]
  PIN p_q[323]
    DIRECTION OUTPUT ;
    USE SIGNAL ;
    PORT
      LAYER M4 ;
        RECT  259.116 206.16 259.2 206.184 ;
    END
  END p_q[323]
  PIN p_q[324]
    DIRECTION OUTPUT ;
    USE SIGNAL ;
    PORT
      LAYER M4 ;
        RECT  259.116 206.256 259.2 206.28 ;
    END
  END p_q[324]
  PIN p_q[325]
    DIRECTION OUTPUT ;
    USE SIGNAL ;
    PORT
      LAYER M4 ;
        RECT  259.116 206.352 259.2 206.376 ;
    END
  END p_q[325]
  PIN p_q[326]
    DIRECTION OUTPUT ;
    USE SIGNAL ;
    PORT
      LAYER M4 ;
        RECT  259.116 206.448 259.2 206.472 ;
    END
  END p_q[326]
  PIN p_q[327]
    DIRECTION OUTPUT ;
    USE SIGNAL ;
    PORT
      LAYER M4 ;
        RECT  259.116 206.544 259.2 206.568 ;
    END
  END p_q[327]
  PIN p_q[328]
    DIRECTION OUTPUT ;
    USE SIGNAL ;
    PORT
      LAYER M4 ;
        RECT  259.116 206.64 259.2 206.664 ;
    END
  END p_q[328]
  PIN p_q[329]
    DIRECTION OUTPUT ;
    USE SIGNAL ;
    PORT
      LAYER M4 ;
        RECT  259.116 206.736 259.2 206.76 ;
    END
  END p_q[329]
  PIN p_q[32]
    DIRECTION OUTPUT ;
    USE SIGNAL ;
    PORT
      LAYER M4 ;
        RECT  259.116 97.584 259.2 97.608 ;
    END
  END p_q[32]
  PIN p_q[330]
    DIRECTION OUTPUT ;
    USE SIGNAL ;
    PORT
      LAYER M4 ;
        RECT  259.116 206.832 259.2 206.856 ;
    END
  END p_q[330]
  PIN p_q[331]
    DIRECTION OUTPUT ;
    USE SIGNAL ;
    PORT
      LAYER M4 ;
        RECT  259.116 206.928 259.2 206.952 ;
    END
  END p_q[331]
  PIN p_q[332]
    DIRECTION OUTPUT ;
    USE SIGNAL ;
    PORT
      LAYER M4 ;
        RECT  259.116 207.024 259.2 207.048 ;
    END
  END p_q[332]
  PIN p_q[333]
    DIRECTION OUTPUT ;
    USE SIGNAL ;
    PORT
      LAYER M4 ;
        RECT  259.116 207.12 259.2 207.144 ;
    END
  END p_q[333]
  PIN p_q[334]
    DIRECTION OUTPUT ;
    USE SIGNAL ;
    PORT
      LAYER M4 ;
        RECT  259.116 207.216 259.2 207.24 ;
    END
  END p_q[334]
  PIN p_q[335]
    DIRECTION OUTPUT ;
    USE SIGNAL ;
    PORT
      LAYER M4 ;
        RECT  259.116 207.312 259.2 207.336 ;
    END
  END p_q[335]
  PIN p_q[336]
    DIRECTION OUTPUT ;
    USE SIGNAL ;
    PORT
      LAYER M4 ;
        RECT  259.116 207.408 259.2 207.432 ;
    END
  END p_q[336]
  PIN p_q[337]
    DIRECTION OUTPUT ;
    USE SIGNAL ;
    PORT
      LAYER M4 ;
        RECT  259.116 207.504 259.2 207.528 ;
    END
  END p_q[337]
  PIN p_q[338]
    DIRECTION OUTPUT ;
    USE SIGNAL ;
    PORT
      LAYER M4 ;
        RECT  259.116 207.6 259.2 207.624 ;
    END
  END p_q[338]
  PIN p_q[339]
    DIRECTION OUTPUT ;
    USE SIGNAL ;
    PORT
      LAYER M4 ;
        RECT  259.116 207.696 259.2 207.72 ;
    END
  END p_q[339]
  PIN p_q[33]
    DIRECTION OUTPUT ;
    USE SIGNAL ;
    PORT
      LAYER M4 ;
        RECT  259.116 97.68 259.2 97.704 ;
    END
  END p_q[33]
  PIN p_q[340]
    DIRECTION OUTPUT ;
    USE SIGNAL ;
    PORT
      LAYER M4 ;
        RECT  259.116 207.792 259.2 207.816 ;
    END
  END p_q[340]
  PIN p_q[341]
    DIRECTION OUTPUT ;
    USE SIGNAL ;
    PORT
      LAYER M4 ;
        RECT  259.116 207.888 259.2 207.912 ;
    END
  END p_q[341]
  PIN p_q[342]
    DIRECTION OUTPUT ;
    USE SIGNAL ;
    PORT
      LAYER M4 ;
        RECT  259.116 207.984 259.2 208.008 ;
    END
  END p_q[342]
  PIN p_q[343]
    DIRECTION OUTPUT ;
    USE SIGNAL ;
    PORT
      LAYER M4 ;
        RECT  259.116 201.936 259.2 201.96 ;
    END
  END p_q[343]
  PIN p_q[344]
    DIRECTION OUTPUT ;
    USE SIGNAL ;
    PORT
      LAYER M4 ;
        RECT  259.116 202.032 259.2 202.056 ;
    END
  END p_q[344]
  PIN p_q[345]
    DIRECTION OUTPUT ;
    USE SIGNAL ;
    PORT
      LAYER M4 ;
        RECT  259.116 202.128 259.2 202.152 ;
    END
  END p_q[345]
  PIN p_q[346]
    DIRECTION OUTPUT ;
    USE SIGNAL ;
    PORT
      LAYER M4 ;
        RECT  259.116 202.224 259.2 202.248 ;
    END
  END p_q[346]
  PIN p_q[347]
    DIRECTION OUTPUT ;
    USE SIGNAL ;
    PORT
      LAYER M4 ;
        RECT  259.116 202.32 259.2 202.344 ;
    END
  END p_q[347]
  PIN p_q[348]
    DIRECTION OUTPUT ;
    USE SIGNAL ;
    PORT
      LAYER M4 ;
        RECT  259.116 202.416 259.2 202.44 ;
    END
  END p_q[348]
  PIN p_q[349]
    DIRECTION OUTPUT ;
    USE SIGNAL ;
    PORT
      LAYER M4 ;
        RECT  259.116 202.512 259.2 202.536 ;
    END
  END p_q[349]
  PIN p_q[34]
    DIRECTION OUTPUT ;
    USE SIGNAL ;
    PORT
      LAYER M4 ;
        RECT  259.116 97.776 259.2 97.8 ;
    END
  END p_q[34]
  PIN p_q[350]
    DIRECTION OUTPUT ;
    USE SIGNAL ;
    PORT
      LAYER M4 ;
        RECT  259.116 202.608 259.2 202.632 ;
    END
  END p_q[350]
  PIN p_q[351]
    DIRECTION OUTPUT ;
    USE SIGNAL ;
    PORT
      LAYER M4 ;
        RECT  259.116 202.704 259.2 202.728 ;
    END
  END p_q[351]
  PIN p_q[352]
    DIRECTION OUTPUT ;
    USE SIGNAL ;
    PORT
      LAYER M4 ;
        RECT  259.116 202.8 259.2 202.824 ;
    END
  END p_q[352]
  PIN p_q[353]
    DIRECTION OUTPUT ;
    USE SIGNAL ;
    PORT
      LAYER M4 ;
        RECT  259.116 202.896 259.2 202.92 ;
    END
  END p_q[353]
  PIN p_q[354]
    DIRECTION OUTPUT ;
    USE SIGNAL ;
    PORT
      LAYER M4 ;
        RECT  259.116 202.992 259.2 203.016 ;
    END
  END p_q[354]
  PIN p_q[355]
    DIRECTION OUTPUT ;
    USE SIGNAL ;
    PORT
      LAYER M4 ;
        RECT  259.116 203.088 259.2 203.112 ;
    END
  END p_q[355]
  PIN p_q[356]
    DIRECTION OUTPUT ;
    USE SIGNAL ;
    PORT
      LAYER M4 ;
        RECT  259.116 203.184 259.2 203.208 ;
    END
  END p_q[356]
  PIN p_q[357]
    DIRECTION OUTPUT ;
    USE SIGNAL ;
    PORT
      LAYER M4 ;
        RECT  259.116 203.28 259.2 203.304 ;
    END
  END p_q[357]
  PIN p_q[358]
    DIRECTION OUTPUT ;
    USE SIGNAL ;
    PORT
      LAYER M4 ;
        RECT  259.116 203.376 259.2 203.4 ;
    END
  END p_q[358]
  PIN p_q[359]
    DIRECTION OUTPUT ;
    USE SIGNAL ;
    PORT
      LAYER M4 ;
        RECT  259.116 203.472 259.2 203.496 ;
    END
  END p_q[359]
  PIN p_q[35]
    DIRECTION OUTPUT ;
    USE SIGNAL ;
    PORT
      LAYER M4 ;
        RECT  259.116 97.872 259.2 97.896 ;
    END
  END p_q[35]
  PIN p_q[360]
    DIRECTION OUTPUT ;
    USE SIGNAL ;
    PORT
      LAYER M4 ;
        RECT  259.116 203.568 259.2 203.592 ;
    END
  END p_q[360]
  PIN p_q[361]
    DIRECTION OUTPUT ;
    USE SIGNAL ;
    PORT
      LAYER M4 ;
        RECT  259.116 203.664 259.2 203.688 ;
    END
  END p_q[361]
  PIN p_q[362]
    DIRECTION OUTPUT ;
    USE SIGNAL ;
    PORT
      LAYER M4 ;
        RECT  259.116 203.76 259.2 203.784 ;
    END
  END p_q[362]
  PIN p_q[363]
    DIRECTION OUTPUT ;
    USE SIGNAL ;
    PORT
      LAYER M4 ;
        RECT  259.116 203.856 259.2 203.88 ;
    END
  END p_q[363]
  PIN p_q[364]
    DIRECTION OUTPUT ;
    USE SIGNAL ;
    PORT
      LAYER M4 ;
        RECT  259.116 203.952 259.2 203.976 ;
    END
  END p_q[364]
  PIN p_q[365]
    DIRECTION OUTPUT ;
    USE SIGNAL ;
    PORT
      LAYER M4 ;
        RECT  259.116 204.048 259.2 204.072 ;
    END
  END p_q[365]
  PIN p_q[366]
    DIRECTION OUTPUT ;
    USE SIGNAL ;
    PORT
      LAYER M4 ;
        RECT  259.116 204.144 259.2 204.168 ;
    END
  END p_q[366]
  PIN p_q[367]
    DIRECTION OUTPUT ;
    USE SIGNAL ;
    PORT
      LAYER M4 ;
        RECT  259.116 204.24 259.2 204.264 ;
    END
  END p_q[367]
  PIN p_q[368]
    DIRECTION OUTPUT ;
    USE SIGNAL ;
    PORT
      LAYER M4 ;
        RECT  259.116 204.336 259.2 204.36 ;
    END
  END p_q[368]
  PIN p_q[369]
    DIRECTION OUTPUT ;
    USE SIGNAL ;
    PORT
      LAYER M4 ;
        RECT  259.116 204.432 259.2 204.456 ;
    END
  END p_q[369]
  PIN p_q[36]
    DIRECTION OUTPUT ;
    USE SIGNAL ;
    PORT
      LAYER M4 ;
        RECT  259.116 97.968 259.2 97.992 ;
    END
  END p_q[36]
  PIN p_q[370]
    DIRECTION OUTPUT ;
    USE SIGNAL ;
    PORT
      LAYER M4 ;
        RECT  259.116 204.528 259.2 204.552 ;
    END
  END p_q[370]
  PIN p_q[371]
    DIRECTION OUTPUT ;
    USE SIGNAL ;
    PORT
      LAYER M4 ;
        RECT  259.116 204.624 259.2 204.648 ;
    END
  END p_q[371]
  PIN p_q[372]
    DIRECTION OUTPUT ;
    USE SIGNAL ;
    PORT
      LAYER M4 ;
        RECT  259.116 204.72 259.2 204.744 ;
    END
  END p_q[372]
  PIN p_q[373]
    DIRECTION OUTPUT ;
    USE SIGNAL ;
    PORT
      LAYER M4 ;
        RECT  259.116 204.816 259.2 204.84 ;
    END
  END p_q[373]
  PIN p_q[374]
    DIRECTION OUTPUT ;
    USE SIGNAL ;
    PORT
      LAYER M4 ;
        RECT  259.116 204.912 259.2 204.936 ;
    END
  END p_q[374]
  PIN p_q[375]
    DIRECTION OUTPUT ;
    USE SIGNAL ;
    PORT
      LAYER M4 ;
        RECT  259.116 250.32 259.2 250.344 ;
    END
  END p_q[375]
  PIN p_q[376]
    DIRECTION OUTPUT ;
    USE SIGNAL ;
    PORT
      LAYER M4 ;
        RECT  259.116 250.416 259.2 250.44 ;
    END
  END p_q[376]
  PIN p_q[377]
    DIRECTION OUTPUT ;
    USE SIGNAL ;
    PORT
      LAYER M4 ;
        RECT  259.116 250.512 259.2 250.536 ;
    END
  END p_q[377]
  PIN p_q[378]
    DIRECTION OUTPUT ;
    USE SIGNAL ;
    PORT
      LAYER M4 ;
        RECT  259.116 250.608 259.2 250.632 ;
    END
  END p_q[378]
  PIN p_q[379]
    DIRECTION OUTPUT ;
    USE SIGNAL ;
    PORT
      LAYER M4 ;
        RECT  259.116 250.704 259.2 250.728 ;
    END
  END p_q[379]
  PIN p_q[37]
    DIRECTION OUTPUT ;
    USE SIGNAL ;
    PORT
      LAYER M4 ;
        RECT  259.116 98.064 259.2 98.088 ;
    END
  END p_q[37]
  PIN p_q[380]
    DIRECTION OUTPUT ;
    USE SIGNAL ;
    PORT
      LAYER M4 ;
        RECT  259.116 250.8 259.2 250.824 ;
    END
  END p_q[380]
  PIN p_q[381]
    DIRECTION OUTPUT ;
    USE SIGNAL ;
    PORT
      LAYER M4 ;
        RECT  259.116 250.896 259.2 250.92 ;
    END
  END p_q[381]
  PIN p_q[382]
    DIRECTION OUTPUT ;
    USE SIGNAL ;
    PORT
      LAYER M4 ;
        RECT  259.116 250.992 259.2 251.016 ;
    END
  END p_q[382]
  PIN p_q[383]
    DIRECTION OUTPUT ;
    USE SIGNAL ;
    PORT
      LAYER M4 ;
        RECT  259.116 251.088 259.2 251.112 ;
    END
  END p_q[383]
  PIN p_q[384]
    DIRECTION OUTPUT ;
    USE SIGNAL ;
    PORT
      LAYER M4 ;
        RECT  259.116 251.184 259.2 251.208 ;
    END
  END p_q[384]
  PIN p_q[385]
    DIRECTION OUTPUT ;
    USE SIGNAL ;
    PORT
      LAYER M4 ;
        RECT  259.116 251.28 259.2 251.304 ;
    END
  END p_q[385]
  PIN p_q[386]
    DIRECTION OUTPUT ;
    USE SIGNAL ;
    PORT
      LAYER M4 ;
        RECT  259.116 251.376 259.2 251.4 ;
    END
  END p_q[386]
  PIN p_q[387]
    DIRECTION OUTPUT ;
    USE SIGNAL ;
    PORT
      LAYER M4 ;
        RECT  259.116 251.472 259.2 251.496 ;
    END
  END p_q[387]
  PIN p_q[388]
    DIRECTION OUTPUT ;
    USE SIGNAL ;
    PORT
      LAYER M4 ;
        RECT  259.116 251.568 259.2 251.592 ;
    END
  END p_q[388]
  PIN p_q[389]
    DIRECTION OUTPUT ;
    USE SIGNAL ;
    PORT
      LAYER M4 ;
        RECT  259.116 251.664 259.2 251.688 ;
    END
  END p_q[389]
  PIN p_q[38]
    DIRECTION OUTPUT ;
    USE SIGNAL ;
    PORT
      LAYER M4 ;
        RECT  259.116 98.16 259.2 98.184 ;
    END
  END p_q[38]
  PIN p_q[390]
    DIRECTION OUTPUT ;
    USE SIGNAL ;
    PORT
      LAYER M4 ;
        RECT  259.116 251.76 259.2 251.784 ;
    END
  END p_q[390]
  PIN p_q[391]
    DIRECTION OUTPUT ;
    USE SIGNAL ;
    PORT
      LAYER M4 ;
        RECT  259.116 251.856 259.2 251.88 ;
    END
  END p_q[391]
  PIN p_q[392]
    DIRECTION OUTPUT ;
    USE SIGNAL ;
    PORT
      LAYER M4 ;
        RECT  259.116 251.952 259.2 251.976 ;
    END
  END p_q[392]
  PIN p_q[393]
    DIRECTION OUTPUT ;
    USE SIGNAL ;
    PORT
      LAYER M4 ;
        RECT  259.116 252.048 259.2 252.072 ;
    END
  END p_q[393]
  PIN p_q[394]
    DIRECTION OUTPUT ;
    USE SIGNAL ;
    PORT
      LAYER M4 ;
        RECT  259.116 252.144 259.2 252.168 ;
    END
  END p_q[394]
  PIN p_q[395]
    DIRECTION OUTPUT ;
    USE SIGNAL ;
    PORT
      LAYER M4 ;
        RECT  259.116 252.24 259.2 252.264 ;
    END
  END p_q[395]
  PIN p_q[396]
    DIRECTION OUTPUT ;
    USE SIGNAL ;
    PORT
      LAYER M4 ;
        RECT  259.116 252.336 259.2 252.36 ;
    END
  END p_q[396]
  PIN p_q[397]
    DIRECTION OUTPUT ;
    USE SIGNAL ;
    PORT
      LAYER M4 ;
        RECT  259.116 252.432 259.2 252.456 ;
    END
  END p_q[397]
  PIN p_q[398]
    DIRECTION OUTPUT ;
    USE SIGNAL ;
    PORT
      LAYER M4 ;
        RECT  259.116 252.528 259.2 252.552 ;
    END
  END p_q[398]
  PIN p_q[399]
    DIRECTION OUTPUT ;
    USE SIGNAL ;
    PORT
      LAYER M4 ;
        RECT  259.116 252.624 259.2 252.648 ;
    END
  END p_q[399]
  PIN p_q[39]
    DIRECTION OUTPUT ;
    USE SIGNAL ;
    PORT
      LAYER M4 ;
        RECT  259.116 98.256 259.2 98.28 ;
    END
  END p_q[39]
  PIN p_q[3]
    DIRECTION OUTPUT ;
    USE SIGNAL ;
    PORT
      LAYER M4 ;
        RECT  259.116 84.816 259.2 84.84 ;
    END
  END p_q[3]
  PIN p_q[400]
    DIRECTION OUTPUT ;
    USE SIGNAL ;
    PORT
      LAYER M4 ;
        RECT  259.116 252.72 259.2 252.744 ;
    END
  END p_q[400]
  PIN p_q[401]
    DIRECTION OUTPUT ;
    USE SIGNAL ;
    PORT
      LAYER M4 ;
        RECT  259.116 252.816 259.2 252.84 ;
    END
  END p_q[401]
  PIN p_q[402]
    DIRECTION OUTPUT ;
    USE SIGNAL ;
    PORT
      LAYER M4 ;
        RECT  259.116 252.912 259.2 252.936 ;
    END
  END p_q[402]
  PIN p_q[403]
    DIRECTION OUTPUT ;
    USE SIGNAL ;
    PORT
      LAYER M4 ;
        RECT  259.116 253.008 259.2 253.032 ;
    END
  END p_q[403]
  PIN p_q[404]
    DIRECTION OUTPUT ;
    USE SIGNAL ;
    PORT
      LAYER M4 ;
        RECT  259.116 253.104 259.2 253.128 ;
    END
  END p_q[404]
  PIN p_q[405]
    DIRECTION OUTPUT ;
    USE SIGNAL ;
    PORT
      LAYER M4 ;
        RECT  259.116 253.2 259.2 253.224 ;
    END
  END p_q[405]
  PIN p_q[406]
    DIRECTION OUTPUT ;
    USE SIGNAL ;
    PORT
      LAYER M4 ;
        RECT  259.116 253.296 259.2 253.32 ;
    END
  END p_q[406]
  PIN p_q[407]
    DIRECTION OUTPUT ;
    USE SIGNAL ;
    PORT
      LAYER M4 ;
        RECT  259.116 275.664 259.2 275.688 ;
    END
  END p_q[407]
  PIN p_q[408]
    DIRECTION OUTPUT ;
    USE SIGNAL ;
    PORT
      LAYER M4 ;
        RECT  259.116 275.76 259.2 275.784 ;
    END
  END p_q[408]
  PIN p_q[409]
    DIRECTION OUTPUT ;
    USE SIGNAL ;
    PORT
      LAYER M4 ;
        RECT  259.116 275.856 259.2 275.88 ;
    END
  END p_q[409]
  PIN p_q[40]
    DIRECTION OUTPUT ;
    USE SIGNAL ;
    PORT
      LAYER M4 ;
        RECT  259.116 98.352 259.2 98.376 ;
    END
  END p_q[40]
  PIN p_q[410]
    DIRECTION OUTPUT ;
    USE SIGNAL ;
    PORT
      LAYER M4 ;
        RECT  259.116 275.952 259.2 275.976 ;
    END
  END p_q[410]
  PIN p_q[411]
    DIRECTION OUTPUT ;
    USE SIGNAL ;
    PORT
      LAYER M4 ;
        RECT  259.116 276.048 259.2 276.072 ;
    END
  END p_q[411]
  PIN p_q[412]
    DIRECTION OUTPUT ;
    USE SIGNAL ;
    PORT
      LAYER M4 ;
        RECT  259.116 276.144 259.2 276.168 ;
    END
  END p_q[412]
  PIN p_q[413]
    DIRECTION OUTPUT ;
    USE SIGNAL ;
    PORT
      LAYER M4 ;
        RECT  259.116 276.24 259.2 276.264 ;
    END
  END p_q[413]
  PIN p_q[414]
    DIRECTION OUTPUT ;
    USE SIGNAL ;
    PORT
      LAYER M4 ;
        RECT  259.116 276.336 259.2 276.36 ;
    END
  END p_q[414]
  PIN p_q[415]
    DIRECTION OUTPUT ;
    USE SIGNAL ;
    PORT
      LAYER M4 ;
        RECT  259.116 276.432 259.2 276.456 ;
    END
  END p_q[415]
  PIN p_q[416]
    DIRECTION OUTPUT ;
    USE SIGNAL ;
    PORT
      LAYER M4 ;
        RECT  259.116 276.528 259.2 276.552 ;
    END
  END p_q[416]
  PIN p_q[417]
    DIRECTION OUTPUT ;
    USE SIGNAL ;
    PORT
      LAYER M4 ;
        RECT  259.116 276.624 259.2 276.648 ;
    END
  END p_q[417]
  PIN p_q[418]
    DIRECTION OUTPUT ;
    USE SIGNAL ;
    PORT
      LAYER M4 ;
        RECT  259.116 276.72 259.2 276.744 ;
    END
  END p_q[418]
  PIN p_q[419]
    DIRECTION OUTPUT ;
    USE SIGNAL ;
    PORT
      LAYER M4 ;
        RECT  259.116 276.816 259.2 276.84 ;
    END
  END p_q[419]
  PIN p_q[41]
    DIRECTION OUTPUT ;
    USE SIGNAL ;
    PORT
      LAYER M4 ;
        RECT  259.116 98.448 259.2 98.472 ;
    END
  END p_q[41]
  PIN p_q[420]
    DIRECTION OUTPUT ;
    USE SIGNAL ;
    PORT
      LAYER M4 ;
        RECT  259.116 276.912 259.2 276.936 ;
    END
  END p_q[420]
  PIN p_q[421]
    DIRECTION OUTPUT ;
    USE SIGNAL ;
    PORT
      LAYER M4 ;
        RECT  259.116 277.008 259.2 277.032 ;
    END
  END p_q[421]
  PIN p_q[422]
    DIRECTION OUTPUT ;
    USE SIGNAL ;
    PORT
      LAYER M4 ;
        RECT  259.116 277.104 259.2 277.128 ;
    END
  END p_q[422]
  PIN p_q[423]
    DIRECTION OUTPUT ;
    USE SIGNAL ;
    PORT
      LAYER M4 ;
        RECT  259.116 277.2 259.2 277.224 ;
    END
  END p_q[423]
  PIN p_q[424]
    DIRECTION OUTPUT ;
    USE SIGNAL ;
    PORT
      LAYER M4 ;
        RECT  259.116 277.296 259.2 277.32 ;
    END
  END p_q[424]
  PIN p_q[425]
    DIRECTION OUTPUT ;
    USE SIGNAL ;
    PORT
      LAYER M4 ;
        RECT  259.116 277.392 259.2 277.416 ;
    END
  END p_q[425]
  PIN p_q[426]
    DIRECTION OUTPUT ;
    USE SIGNAL ;
    PORT
      LAYER M4 ;
        RECT  259.116 277.488 259.2 277.512 ;
    END
  END p_q[426]
  PIN p_q[427]
    DIRECTION OUTPUT ;
    USE SIGNAL ;
    PORT
      LAYER M4 ;
        RECT  259.116 277.584 259.2 277.608 ;
    END
  END p_q[427]
  PIN p_q[428]
    DIRECTION OUTPUT ;
    USE SIGNAL ;
    PORT
      LAYER M4 ;
        RECT  259.116 277.68 259.2 277.704 ;
    END
  END p_q[428]
  PIN p_q[429]
    DIRECTION OUTPUT ;
    USE SIGNAL ;
    PORT
      LAYER M4 ;
        RECT  259.116 277.776 259.2 277.8 ;
    END
  END p_q[429]
  PIN p_q[42]
    DIRECTION OUTPUT ;
    USE SIGNAL ;
    PORT
      LAYER M4 ;
        RECT  259.116 98.544 259.2 98.568 ;
    END
  END p_q[42]
  PIN p_q[430]
    DIRECTION OUTPUT ;
    USE SIGNAL ;
    PORT
      LAYER M4 ;
        RECT  259.116 277.872 259.2 277.896 ;
    END
  END p_q[430]
  PIN p_q[431]
    DIRECTION OUTPUT ;
    USE SIGNAL ;
    PORT
      LAYER M4 ;
        RECT  259.116 277.968 259.2 277.992 ;
    END
  END p_q[431]
  PIN p_q[432]
    DIRECTION OUTPUT ;
    USE SIGNAL ;
    PORT
      LAYER M4 ;
        RECT  259.116 278.064 259.2 278.088 ;
    END
  END p_q[432]
  PIN p_q[433]
    DIRECTION OUTPUT ;
    USE SIGNAL ;
    PORT
      LAYER M4 ;
        RECT  259.116 278.16 259.2 278.184 ;
    END
  END p_q[433]
  PIN p_q[434]
    DIRECTION OUTPUT ;
    USE SIGNAL ;
    PORT
      LAYER M4 ;
        RECT  259.116 278.256 259.2 278.28 ;
    END
  END p_q[434]
  PIN p_q[435]
    DIRECTION OUTPUT ;
    USE SIGNAL ;
    PORT
      LAYER M4 ;
        RECT  259.116 278.352 259.2 278.376 ;
    END
  END p_q[435]
  PIN p_q[436]
    DIRECTION OUTPUT ;
    USE SIGNAL ;
    PORT
      LAYER M4 ;
        RECT  259.116 278.448 259.2 278.472 ;
    END
  END p_q[436]
  PIN p_q[437]
    DIRECTION OUTPUT ;
    USE SIGNAL ;
    PORT
      LAYER M4 ;
        RECT  259.116 278.544 259.2 278.568 ;
    END
  END p_q[437]
  PIN p_q[438]
    DIRECTION OUTPUT ;
    USE SIGNAL ;
    PORT
      LAYER M4 ;
        RECT  259.116 278.64 259.2 278.664 ;
    END
  END p_q[438]
  PIN p_q[439]
    DIRECTION OUTPUT ;
    USE SIGNAL ;
    PORT
      LAYER M4 ;
        RECT  259.116 278.736 259.2 278.76 ;
    END
  END p_q[439]
  PIN p_q[43]
    DIRECTION OUTPUT ;
    USE SIGNAL ;
    PORT
      LAYER M4 ;
        RECT  259.116 98.64 259.2 98.664 ;
    END
  END p_q[43]
  PIN p_q[440]
    DIRECTION OUTPUT ;
    USE SIGNAL ;
    PORT
      LAYER M4 ;
        RECT  259.116 278.832 259.2 278.856 ;
    END
  END p_q[440]
  PIN p_q[441]
    DIRECTION OUTPUT ;
    USE SIGNAL ;
    PORT
      LAYER M4 ;
        RECT  259.116 278.928 259.2 278.952 ;
    END
  END p_q[441]
  PIN p_q[442]
    DIRECTION OUTPUT ;
    USE SIGNAL ;
    PORT
      LAYER M4 ;
        RECT  259.116 279.024 259.2 279.048 ;
    END
  END p_q[442]
  PIN p_q[443]
    DIRECTION OUTPUT ;
    USE SIGNAL ;
    PORT
      LAYER M4 ;
        RECT  259.116 279.12 259.2 279.144 ;
    END
  END p_q[443]
  PIN p_q[444]
    DIRECTION OUTPUT ;
    USE SIGNAL ;
    PORT
      LAYER M4 ;
        RECT  259.116 279.216 259.2 279.24 ;
    END
  END p_q[444]
  PIN p_q[445]
    DIRECTION OUTPUT ;
    USE SIGNAL ;
    PORT
      LAYER M4 ;
        RECT  259.116 279.312 259.2 279.336 ;
    END
  END p_q[445]
  PIN p_q[446]
    DIRECTION OUTPUT ;
    USE SIGNAL ;
    PORT
      LAYER M4 ;
        RECT  259.116 279.408 259.2 279.432 ;
    END
  END p_q[446]
  PIN p_q[447]
    DIRECTION OUTPUT ;
    USE SIGNAL ;
    PORT
      LAYER M4 ;
        RECT  259.116 279.504 259.2 279.528 ;
    END
  END p_q[447]
  PIN p_q[448]
    DIRECTION OUTPUT ;
    USE SIGNAL ;
    PORT
      LAYER M4 ;
        RECT  259.116 279.6 259.2 279.624 ;
    END
  END p_q[448]
  PIN p_q[449]
    DIRECTION OUTPUT ;
    USE SIGNAL ;
    PORT
      LAYER M4 ;
        RECT  259.116 279.696 259.2 279.72 ;
    END
  END p_q[449]
  PIN p_q[44]
    DIRECTION OUTPUT ;
    USE SIGNAL ;
    PORT
      LAYER M4 ;
        RECT  259.116 98.736 259.2 98.76 ;
    END
  END p_q[44]
  PIN p_q[450]
    DIRECTION OUTPUT ;
    USE SIGNAL ;
    PORT
      LAYER M4 ;
        RECT  259.116 279.792 259.2 279.816 ;
    END
  END p_q[450]
  PIN p_q[451]
    DIRECTION OUTPUT ;
    USE SIGNAL ;
    PORT
      LAYER M4 ;
        RECT  259.116 279.888 259.2 279.912 ;
    END
  END p_q[451]
  PIN p_q[452]
    DIRECTION OUTPUT ;
    USE SIGNAL ;
    PORT
      LAYER M4 ;
        RECT  259.116 279.984 259.2 280.008 ;
    END
  END p_q[452]
  PIN p_q[453]
    DIRECTION OUTPUT ;
    USE SIGNAL ;
    PORT
      LAYER M4 ;
        RECT  259.116 280.08 259.2 280.104 ;
    END
  END p_q[453]
  PIN p_q[454]
    DIRECTION OUTPUT ;
    USE SIGNAL ;
    PORT
      LAYER M4 ;
        RECT  259.116 280.176 259.2 280.2 ;
    END
  END p_q[454]
  PIN p_q[455]
    DIRECTION OUTPUT ;
    USE SIGNAL ;
    PORT
      LAYER M4 ;
        RECT  259.116 280.272 259.2 280.296 ;
    END
  END p_q[455]
  PIN p_q[456]
    DIRECTION OUTPUT ;
    USE SIGNAL ;
    PORT
      LAYER M4 ;
        RECT  259.116 280.368 259.2 280.392 ;
    END
  END p_q[456]
  PIN p_q[45]
    DIRECTION OUTPUT ;
    USE SIGNAL ;
    PORT
      LAYER M4 ;
        RECT  259.116 98.832 259.2 98.856 ;
    END
  END p_q[45]
  PIN p_q[46]
    DIRECTION OUTPUT ;
    USE SIGNAL ;
    PORT
      LAYER M4 ;
        RECT  259.116 98.928 259.2 98.952 ;
    END
  END p_q[46]
  PIN p_q[47]
    DIRECTION OUTPUT ;
    USE SIGNAL ;
    PORT
      LAYER M4 ;
        RECT  259.116 99.024 259.2 99.048 ;
    END
  END p_q[47]
  PIN p_q[48]
    DIRECTION OUTPUT ;
    USE SIGNAL ;
    PORT
      LAYER M4 ;
        RECT  259.116 99.12 259.2 99.144 ;
    END
  END p_q[48]
  PIN p_q[49]
    DIRECTION OUTPUT ;
    USE SIGNAL ;
    PORT
      LAYER M4 ;
        RECT  259.116 99.216 259.2 99.24 ;
    END
  END p_q[49]
  PIN p_q[4]
    DIRECTION OUTPUT ;
    USE SIGNAL ;
    PORT
      LAYER M4 ;
        RECT  259.116 84.912 259.2 84.936 ;
    END
  END p_q[4]
  PIN p_q[50]
    DIRECTION OUTPUT ;
    USE SIGNAL ;
    PORT
      LAYER M4 ;
        RECT  259.116 99.312 259.2 99.336 ;
    END
  END p_q[50]
  PIN p_q[51]
    DIRECTION OUTPUT ;
    USE SIGNAL ;
    PORT
      LAYER M4 ;
        RECT  259.116 99.408 259.2 99.432 ;
    END
  END p_q[51]
  PIN p_q[52]
    DIRECTION OUTPUT ;
    USE SIGNAL ;
    PORT
      LAYER M4 ;
        RECT  259.116 99.504 259.2 99.528 ;
    END
  END p_q[52]
  PIN p_q[53]
    DIRECTION OUTPUT ;
    USE SIGNAL ;
    PORT
      LAYER M4 ;
        RECT  259.116 99.6 259.2 99.624 ;
    END
  END p_q[53]
  PIN p_q[54]
    DIRECTION OUTPUT ;
    USE SIGNAL ;
    PORT
      LAYER M4 ;
        RECT  259.116 99.696 259.2 99.72 ;
    END
  END p_q[54]
  PIN p_q[55]
    DIRECTION OUTPUT ;
    USE SIGNAL ;
    PORT
      LAYER M4 ;
        RECT  259.116 109.008 259.2 109.032 ;
    END
  END p_q[55]
  PIN p_q[56]
    DIRECTION OUTPUT ;
    USE SIGNAL ;
    PORT
      LAYER M4 ;
        RECT  259.116 109.104 259.2 109.128 ;
    END
  END p_q[56]
  PIN p_q[57]
    DIRECTION OUTPUT ;
    USE SIGNAL ;
    PORT
      LAYER M4 ;
        RECT  259.116 109.2 259.2 109.224 ;
    END
  END p_q[57]
  PIN p_q[58]
    DIRECTION OUTPUT ;
    USE SIGNAL ;
    PORT
      LAYER M4 ;
        RECT  259.116 109.296 259.2 109.32 ;
    END
  END p_q[58]
  PIN p_q[59]
    DIRECTION OUTPUT ;
    USE SIGNAL ;
    PORT
      LAYER M4 ;
        RECT  259.116 109.392 259.2 109.416 ;
    END
  END p_q[59]
  PIN p_q[5]
    DIRECTION OUTPUT ;
    USE SIGNAL ;
    PORT
      LAYER M4 ;
        RECT  259.116 85.008 259.2 85.032 ;
    END
  END p_q[5]
  PIN p_q[60]
    DIRECTION OUTPUT ;
    USE SIGNAL ;
    PORT
      LAYER M4 ;
        RECT  259.116 109.488 259.2 109.512 ;
    END
  END p_q[60]
  PIN p_q[61]
    DIRECTION OUTPUT ;
    USE SIGNAL ;
    PORT
      LAYER M4 ;
        RECT  259.116 109.584 259.2 109.608 ;
    END
  END p_q[61]
  PIN p_q[62]
    DIRECTION OUTPUT ;
    USE SIGNAL ;
    PORT
      LAYER M4 ;
        RECT  259.116 109.68 259.2 109.704 ;
    END
  END p_q[62]
  PIN p_q[63]
    DIRECTION OUTPUT ;
    USE SIGNAL ;
    PORT
      LAYER M4 ;
        RECT  259.116 109.776 259.2 109.8 ;
    END
  END p_q[63]
  PIN p_q[64]
    DIRECTION OUTPUT ;
    USE SIGNAL ;
    PORT
      LAYER M4 ;
        RECT  259.116 109.872 259.2 109.896 ;
    END
  END p_q[64]
  PIN p_q[65]
    DIRECTION OUTPUT ;
    USE SIGNAL ;
    PORT
      LAYER M4 ;
        RECT  259.116 109.968 259.2 109.992 ;
    END
  END p_q[65]
  PIN p_q[66]
    DIRECTION OUTPUT ;
    USE SIGNAL ;
    PORT
      LAYER M4 ;
        RECT  259.116 110.064 259.2 110.088 ;
    END
  END p_q[66]
  PIN p_q[67]
    DIRECTION OUTPUT ;
    USE SIGNAL ;
    PORT
      LAYER M4 ;
        RECT  259.116 110.16 259.2 110.184 ;
    END
  END p_q[67]
  PIN p_q[68]
    DIRECTION OUTPUT ;
    USE SIGNAL ;
    PORT
      LAYER M4 ;
        RECT  259.116 110.256 259.2 110.28 ;
    END
  END p_q[68]
  PIN p_q[69]
    DIRECTION OUTPUT ;
    USE SIGNAL ;
    PORT
      LAYER M4 ;
        RECT  259.116 110.352 259.2 110.376 ;
    END
  END p_q[69]
  PIN p_q[6]
    DIRECTION OUTPUT ;
    USE SIGNAL ;
    PORT
      LAYER M4 ;
        RECT  259.116 85.104 259.2 85.128 ;
    END
  END p_q[6]
  PIN p_q[70]
    DIRECTION OUTPUT ;
    USE SIGNAL ;
    PORT
      LAYER M4 ;
        RECT  259.116 110.448 259.2 110.472 ;
    END
  END p_q[70]
  PIN p_q[71]
    DIRECTION OUTPUT ;
    USE SIGNAL ;
    PORT
      LAYER M4 ;
        RECT  259.116 110.544 259.2 110.568 ;
    END
  END p_q[71]
  PIN p_q[72]
    DIRECTION OUTPUT ;
    USE SIGNAL ;
    PORT
      LAYER M4 ;
        RECT  259.116 110.64 259.2 110.664 ;
    END
  END p_q[72]
  PIN p_q[73]
    DIRECTION OUTPUT ;
    USE SIGNAL ;
    PORT
      LAYER M4 ;
        RECT  259.116 110.736 259.2 110.76 ;
    END
  END p_q[73]
  PIN p_q[74]
    DIRECTION OUTPUT ;
    USE SIGNAL ;
    PORT
      LAYER M4 ;
        RECT  259.116 110.832 259.2 110.856 ;
    END
  END p_q[74]
  PIN p_q[75]
    DIRECTION OUTPUT ;
    USE SIGNAL ;
    PORT
      LAYER M4 ;
        RECT  259.116 110.928 259.2 110.952 ;
    END
  END p_q[75]
  PIN p_q[76]
    DIRECTION OUTPUT ;
    USE SIGNAL ;
    PORT
      LAYER M4 ;
        RECT  259.116 111.024 259.2 111.048 ;
    END
  END p_q[76]
  PIN p_q[77]
    DIRECTION OUTPUT ;
    USE SIGNAL ;
    PORT
      LAYER M4 ;
        RECT  259.116 111.12 259.2 111.144 ;
    END
  END p_q[77]
  PIN p_q[78]
    DIRECTION OUTPUT ;
    USE SIGNAL ;
    PORT
      LAYER M4 ;
        RECT  259.116 111.216 259.2 111.24 ;
    END
  END p_q[78]
  PIN p_q[79]
    DIRECTION OUTPUT ;
    USE SIGNAL ;
    PORT
      LAYER M4 ;
        RECT  259.116 111.312 259.2 111.336 ;
    END
  END p_q[79]
  PIN p_q[7]
    DIRECTION OUTPUT ;
    USE SIGNAL ;
    PORT
      LAYER M4 ;
        RECT  259.116 85.2 259.2 85.224 ;
    END
  END p_q[7]
  PIN p_q[80]
    DIRECTION OUTPUT ;
    USE SIGNAL ;
    PORT
      LAYER M4 ;
        RECT  259.116 111.408 259.2 111.432 ;
    END
  END p_q[80]
  PIN p_q[81]
    DIRECTION OUTPUT ;
    USE SIGNAL ;
    PORT
      LAYER M4 ;
        RECT  259.116 111.504 259.2 111.528 ;
    END
  END p_q[81]
  PIN p_q[82]
    DIRECTION OUTPUT ;
    USE SIGNAL ;
    PORT
      LAYER M4 ;
        RECT  259.116 111.6 259.2 111.624 ;
    END
  END p_q[82]
  PIN p_q[83]
    DIRECTION OUTPUT ;
    USE SIGNAL ;
    PORT
      LAYER M4 ;
        RECT  259.116 111.696 259.2 111.72 ;
    END
  END p_q[83]
  PIN p_q[84]
    DIRECTION OUTPUT ;
    USE SIGNAL ;
    PORT
      LAYER M4 ;
        RECT  259.116 111.792 259.2 111.816 ;
    END
  END p_q[84]
  PIN p_q[85]
    DIRECTION OUTPUT ;
    USE SIGNAL ;
    PORT
      LAYER M4 ;
        RECT  259.116 111.888 259.2 111.912 ;
    END
  END p_q[85]
  PIN p_q[86]
    DIRECTION OUTPUT ;
    USE SIGNAL ;
    PORT
      LAYER M4 ;
        RECT  259.116 111.984 259.2 112.008 ;
    END
  END p_q[86]
  PIN p_q[87]
    DIRECTION OUTPUT ;
    USE SIGNAL ;
    PORT
      LAYER M4 ;
        RECT  259.116 157.392 259.2 157.416 ;
    END
  END p_q[87]
  PIN p_q[88]
    DIRECTION OUTPUT ;
    USE SIGNAL ;
    PORT
      LAYER M4 ;
        RECT  259.116 157.488 259.2 157.512 ;
    END
  END p_q[88]
  PIN p_q[89]
    DIRECTION OUTPUT ;
    USE SIGNAL ;
    PORT
      LAYER M4 ;
        RECT  259.116 157.584 259.2 157.608 ;
    END
  END p_q[89]
  PIN p_q[8]
    DIRECTION OUTPUT ;
    USE SIGNAL ;
    PORT
      LAYER M4 ;
        RECT  259.116 85.296 259.2 85.32 ;
    END
  END p_q[8]
  PIN p_q[90]
    DIRECTION OUTPUT ;
    USE SIGNAL ;
    PORT
      LAYER M4 ;
        RECT  259.116 157.68 259.2 157.704 ;
    END
  END p_q[90]
  PIN p_q[91]
    DIRECTION OUTPUT ;
    USE SIGNAL ;
    PORT
      LAYER M4 ;
        RECT  259.116 157.776 259.2 157.8 ;
    END
  END p_q[91]
  PIN p_q[92]
    DIRECTION OUTPUT ;
    USE SIGNAL ;
    PORT
      LAYER M4 ;
        RECT  259.116 157.872 259.2 157.896 ;
    END
  END p_q[92]
  PIN p_q[93]
    DIRECTION OUTPUT ;
    USE SIGNAL ;
    PORT
      LAYER M4 ;
        RECT  259.116 157.968 259.2 157.992 ;
    END
  END p_q[93]
  PIN p_q[94]
    DIRECTION OUTPUT ;
    USE SIGNAL ;
    PORT
      LAYER M4 ;
        RECT  259.116 158.064 259.2 158.088 ;
    END
  END p_q[94]
  PIN p_q[95]
    DIRECTION OUTPUT ;
    USE SIGNAL ;
    PORT
      LAYER M4 ;
        RECT  259.116 158.16 259.2 158.184 ;
    END
  END p_q[95]
  PIN p_q[96]
    DIRECTION OUTPUT ;
    USE SIGNAL ;
    PORT
      LAYER M4 ;
        RECT  259.116 158.256 259.2 158.28 ;
    END
  END p_q[96]
  PIN p_q[97]
    DIRECTION OUTPUT ;
    USE SIGNAL ;
    PORT
      LAYER M4 ;
        RECT  259.116 158.352 259.2 158.376 ;
    END
  END p_q[97]
  PIN p_q[98]
    DIRECTION OUTPUT ;
    USE SIGNAL ;
    PORT
      LAYER M4 ;
        RECT  259.116 158.448 259.2 158.472 ;
    END
  END p_q[98]
  PIN p_q[99]
    DIRECTION OUTPUT ;
    USE SIGNAL ;
    PORT
      LAYER M4 ;
        RECT  259.116 158.544 259.2 158.568 ;
    END
  END p_q[99]
  PIN p_q[9]
    DIRECTION OUTPUT ;
    USE SIGNAL ;
    PORT
      LAYER M4 ;
        RECT  259.116 85.392 259.2 85.416 ;
    END
  END p_q[9]
  PIN p_re
    DIRECTION INPUT ;
    USE SIGNAL ;
    PORT
      LAYER M4 ;
        RECT  259.116 280.464 259.2 280.488 ;
    END
  END p_re
  PIN tw_addr[0]
    DIRECTION INPUT ;
    USE SIGNAL ;
    PORT
      LAYER M5 ;
        RECT  35.376 0 35.4 0.084 ;
    END
  END tw_addr[0]
  PIN tw_addr[1]
    DIRECTION INPUT ;
    USE SIGNAL ;
    PORT
      LAYER M5 ;
        RECT  35.472 0 35.496 0.084 ;
    END
  END tw_addr[1]
  PIN tw_addr[2]
    DIRECTION INPUT ;
    USE SIGNAL ;
    PORT
      LAYER M5 ;
        RECT  35.568 0 35.592 0.084 ;
    END
  END tw_addr[2]
  PIN tw_addr[3]
    DIRECTION INPUT ;
    USE SIGNAL ;
    PORT
      LAYER M5 ;
        RECT  35.664 0 35.688 0.084 ;
    END
  END tw_addr[3]
  PIN tw_addr[4]
    DIRECTION INPUT ;
    USE SIGNAL ;
    PORT
      LAYER M5 ;
        RECT  35.76 0 35.784 0.084 ;
    END
  END tw_addr[4]
  PIN tw_addr[5]
    DIRECTION INPUT ;
    USE SIGNAL ;
    PORT
      LAYER M5 ;
        RECT  35.856 0 35.88 0.084 ;
    END
  END tw_addr[5]
  PIN tw_addr[6]
    DIRECTION INPUT ;
    USE SIGNAL ;
    PORT
      LAYER M5 ;
        RECT  35.952 0 35.976 0.084 ;
    END
  END tw_addr[6]
  PIN tw_addr[7]
    DIRECTION INPUT ;
    USE SIGNAL ;
    PORT
      LAYER M5 ;
        RECT  36.048 0 36.072 0.084 ;
    END
  END tw_addr[7]
  PIN tw_d0[0]
    DIRECTION INPUT ;
    USE SIGNAL ;
    PORT
      LAYER M5 ;
        RECT  36.144 0 36.168 0.084 ;
    END
  END tw_d0[0]
  PIN tw_d0[100]
    DIRECTION INPUT ;
    USE SIGNAL ;
    PORT
      LAYER M5 ;
        RECT  33.456 0 33.48 0.084 ;
    END
  END tw_d0[100]
  PIN tw_d0[101]
    DIRECTION INPUT ;
    USE SIGNAL ;
    PORT
      LAYER M5 ;
        RECT  33.552 0 33.576 0.084 ;
    END
  END tw_d0[101]
  PIN tw_d0[102]
    DIRECTION INPUT ;
    USE SIGNAL ;
    PORT
      LAYER M5 ;
        RECT  33.648 0 33.672 0.084 ;
    END
  END tw_d0[102]
  PIN tw_d0[103]
    DIRECTION INPUT ;
    USE SIGNAL ;
    PORT
      LAYER M5 ;
        RECT  33.744 0 33.768 0.084 ;
    END
  END tw_d0[103]
  PIN tw_d0[104]
    DIRECTION INPUT ;
    USE SIGNAL ;
    PORT
      LAYER M5 ;
        RECT  33.84 0 33.864 0.084 ;
    END
  END tw_d0[104]
  PIN tw_d0[105]
    DIRECTION INPUT ;
    USE SIGNAL ;
    PORT
      LAYER M5 ;
        RECT  33.936 0 33.96 0.084 ;
    END
  END tw_d0[105]
  PIN tw_d0[106]
    DIRECTION INPUT ;
    USE SIGNAL ;
    PORT
      LAYER M5 ;
        RECT  34.032 0 34.056 0.084 ;
    END
  END tw_d0[106]
  PIN tw_d0[107]
    DIRECTION INPUT ;
    USE SIGNAL ;
    PORT
      LAYER M5 ;
        RECT  34.128 0 34.152 0.084 ;
    END
  END tw_d0[107]
  PIN tw_d0[108]
    DIRECTION INPUT ;
    USE SIGNAL ;
    PORT
      LAYER M5 ;
        RECT  34.224 0 34.248 0.084 ;
    END
  END tw_d0[108]
  PIN tw_d0[109]
    DIRECTION INPUT ;
    USE SIGNAL ;
    PORT
      LAYER M5 ;
        RECT  34.32 0 34.344 0.084 ;
    END
  END tw_d0[109]
  PIN tw_d0[10]
    DIRECTION INPUT ;
    USE SIGNAL ;
    PORT
      LAYER M5 ;
        RECT  37.104 0 37.128 0.084 ;
    END
  END tw_d0[10]
  PIN tw_d0[110]
    DIRECTION INPUT ;
    USE SIGNAL ;
    PORT
      LAYER M5 ;
        RECT  34.416 0 34.44 0.084 ;
    END
  END tw_d0[110]
  PIN tw_d0[111]
    DIRECTION INPUT ;
    USE SIGNAL ;
    PORT
      LAYER M5 ;
        RECT  34.512 0 34.536 0.084 ;
    END
  END tw_d0[111]
  PIN tw_d0[112]
    DIRECTION INPUT ;
    USE SIGNAL ;
    PORT
      LAYER M5 ;
        RECT  34.608 0 34.632 0.084 ;
    END
  END tw_d0[112]
  PIN tw_d0[113]
    DIRECTION INPUT ;
    USE SIGNAL ;
    PORT
      LAYER M5 ;
        RECT  34.704 0 34.728 0.084 ;
    END
  END tw_d0[113]
  PIN tw_d0[114]
    DIRECTION INPUT ;
    USE SIGNAL ;
    PORT
      LAYER M5 ;
        RECT  34.8 0 34.824 0.084 ;
    END
  END tw_d0[114]
  PIN tw_d0[115]
    DIRECTION INPUT ;
    USE SIGNAL ;
    PORT
      LAYER M5 ;
        RECT  34.896 0 34.92 0.084 ;
    END
  END tw_d0[115]
  PIN tw_d0[116]
    DIRECTION INPUT ;
    USE SIGNAL ;
    PORT
      LAYER M5 ;
        RECT  34.992 0 35.016 0.084 ;
    END
  END tw_d0[116]
  PIN tw_d0[117]
    DIRECTION INPUT ;
    USE SIGNAL ;
    PORT
      LAYER M5 ;
        RECT  35.088 0 35.112 0.084 ;
    END
  END tw_d0[117]
  PIN tw_d0[118]
    DIRECTION INPUT ;
    USE SIGNAL ;
    PORT
      LAYER M5 ;
        RECT  35.184 0 35.208 0.084 ;
    END
  END tw_d0[118]
  PIN tw_d0[119]
    DIRECTION INPUT ;
    USE SIGNAL ;
    PORT
      LAYER M5 ;
        RECT  54.48 0 54.504 0.084 ;
    END
  END tw_d0[119]
  PIN tw_d0[11]
    DIRECTION INPUT ;
    USE SIGNAL ;
    PORT
      LAYER M5 ;
        RECT  37.2 0 37.224 0.084 ;
    END
  END tw_d0[11]
  PIN tw_d0[120]
    DIRECTION INPUT ;
    USE SIGNAL ;
    PORT
      LAYER M5 ;
        RECT  54.576 0 54.6 0.084 ;
    END
  END tw_d0[120]
  PIN tw_d0[121]
    DIRECTION INPUT ;
    USE SIGNAL ;
    PORT
      LAYER M5 ;
        RECT  54.672 0 54.696 0.084 ;
    END
  END tw_d0[121]
  PIN tw_d0[122]
    DIRECTION INPUT ;
    USE SIGNAL ;
    PORT
      LAYER M5 ;
        RECT  54.768 0 54.792 0.084 ;
    END
  END tw_d0[122]
  PIN tw_d0[123]
    DIRECTION INPUT ;
    USE SIGNAL ;
    PORT
      LAYER M5 ;
        RECT  54.864 0 54.888 0.084 ;
    END
  END tw_d0[123]
  PIN tw_d0[124]
    DIRECTION INPUT ;
    USE SIGNAL ;
    PORT
      LAYER M5 ;
        RECT  54.96 0 54.984 0.084 ;
    END
  END tw_d0[124]
  PIN tw_d0[125]
    DIRECTION INPUT ;
    USE SIGNAL ;
    PORT
      LAYER M5 ;
        RECT  55.056 0 55.08 0.084 ;
    END
  END tw_d0[125]
  PIN tw_d0[126]
    DIRECTION INPUT ;
    USE SIGNAL ;
    PORT
      LAYER M5 ;
        RECT  55.152 0 55.176 0.084 ;
    END
  END tw_d0[126]
  PIN tw_d0[127]
    DIRECTION INPUT ;
    USE SIGNAL ;
    PORT
      LAYER M5 ;
        RECT  55.248 0 55.272 0.084 ;
    END
  END tw_d0[127]
  PIN tw_d0[128]
    DIRECTION INPUT ;
    USE SIGNAL ;
    PORT
      LAYER M5 ;
        RECT  55.344 0 55.368 0.084 ;
    END
  END tw_d0[128]
  PIN tw_d0[129]
    DIRECTION INPUT ;
    USE SIGNAL ;
    PORT
      LAYER M5 ;
        RECT  55.44 0 55.464 0.084 ;
    END
  END tw_d0[129]
  PIN tw_d0[12]
    DIRECTION INPUT ;
    USE SIGNAL ;
    PORT
      LAYER M5 ;
        RECT  37.296 0 37.32 0.084 ;
    END
  END tw_d0[12]
  PIN tw_d0[130]
    DIRECTION INPUT ;
    USE SIGNAL ;
    PORT
      LAYER M5 ;
        RECT  55.536 0 55.56 0.084 ;
    END
  END tw_d0[130]
  PIN tw_d0[131]
    DIRECTION INPUT ;
    USE SIGNAL ;
    PORT
      LAYER M5 ;
        RECT  55.632 0 55.656 0.084 ;
    END
  END tw_d0[131]
  PIN tw_d0[132]
    DIRECTION INPUT ;
    USE SIGNAL ;
    PORT
      LAYER M5 ;
        RECT  55.728 0 55.752 0.084 ;
    END
  END tw_d0[132]
  PIN tw_d0[133]
    DIRECTION INPUT ;
    USE SIGNAL ;
    PORT
      LAYER M5 ;
        RECT  55.824 0 55.848 0.084 ;
    END
  END tw_d0[133]
  PIN tw_d0[134]
    DIRECTION INPUT ;
    USE SIGNAL ;
    PORT
      LAYER M5 ;
        RECT  55.92 0 55.944 0.084 ;
    END
  END tw_d0[134]
  PIN tw_d0[135]
    DIRECTION INPUT ;
    USE SIGNAL ;
    PORT
      LAYER M5 ;
        RECT  56.016 0 56.04 0.084 ;
    END
  END tw_d0[135]
  PIN tw_d0[136]
    DIRECTION INPUT ;
    USE SIGNAL ;
    PORT
      LAYER M5 ;
        RECT  56.112 0 56.136 0.084 ;
    END
  END tw_d0[136]
  PIN tw_d0[137]
    DIRECTION INPUT ;
    USE SIGNAL ;
    PORT
      LAYER M5 ;
        RECT  56.208 0 56.232 0.084 ;
    END
  END tw_d0[137]
  PIN tw_d0[138]
    DIRECTION INPUT ;
    USE SIGNAL ;
    PORT
      LAYER M5 ;
        RECT  56.304 0 56.328 0.084 ;
    END
  END tw_d0[138]
  PIN tw_d0[139]
    DIRECTION INPUT ;
    USE SIGNAL ;
    PORT
      LAYER M5 ;
        RECT  56.4 0 56.424 0.084 ;
    END
  END tw_d0[139]
  PIN tw_d0[13]
    DIRECTION INPUT ;
    USE SIGNAL ;
    PORT
      LAYER M5 ;
        RECT  37.392 0 37.416 0.084 ;
    END
  END tw_d0[13]
  PIN tw_d0[140]
    DIRECTION INPUT ;
    USE SIGNAL ;
    PORT
      LAYER M5 ;
        RECT  56.496 0 56.52 0.084 ;
    END
  END tw_d0[140]
  PIN tw_d0[141]
    DIRECTION INPUT ;
    USE SIGNAL ;
    PORT
      LAYER M5 ;
        RECT  56.592 0 56.616 0.084 ;
    END
  END tw_d0[141]
  PIN tw_d0[142]
    DIRECTION INPUT ;
    USE SIGNAL ;
    PORT
      LAYER M5 ;
        RECT  56.688 0 56.712 0.084 ;
    END
  END tw_d0[142]
  PIN tw_d0[143]
    DIRECTION INPUT ;
    USE SIGNAL ;
    PORT
      LAYER M5 ;
        RECT  56.784 0 56.808 0.084 ;
    END
  END tw_d0[143]
  PIN tw_d0[144]
    DIRECTION INPUT ;
    USE SIGNAL ;
    PORT
      LAYER M5 ;
        RECT  56.88 0 56.904 0.084 ;
    END
  END tw_d0[144]
  PIN tw_d0[145]
    DIRECTION INPUT ;
    USE SIGNAL ;
    PORT
      LAYER M5 ;
        RECT  56.976 0 57 0.084 ;
    END
  END tw_d0[145]
  PIN tw_d0[146]
    DIRECTION INPUT ;
    USE SIGNAL ;
    PORT
      LAYER M5 ;
        RECT  57.072 0 57.096 0.084 ;
    END
  END tw_d0[146]
  PIN tw_d0[147]
    DIRECTION INPUT ;
    USE SIGNAL ;
    PORT
      LAYER M5 ;
        RECT  57.168 0 57.192 0.084 ;
    END
  END tw_d0[147]
  PIN tw_d0[148]
    DIRECTION INPUT ;
    USE SIGNAL ;
    PORT
      LAYER M5 ;
        RECT  57.264 0 57.288 0.084 ;
    END
  END tw_d0[148]
  PIN tw_d0[149]
    DIRECTION INPUT ;
    USE SIGNAL ;
    PORT
      LAYER M5 ;
        RECT  57.36 0 57.384 0.084 ;
    END
  END tw_d0[149]
  PIN tw_d0[14]
    DIRECTION INPUT ;
    USE SIGNAL ;
    PORT
      LAYER M5 ;
        RECT  37.488 0 37.512 0.084 ;
    END
  END tw_d0[14]
  PIN tw_d0[150]
    DIRECTION INPUT ;
    USE SIGNAL ;
    PORT
      LAYER M5 ;
        RECT  57.456 0 57.48 0.084 ;
    END
  END tw_d0[150]
  PIN tw_d0[151]
    DIRECTION INPUT ;
    USE SIGNAL ;
    PORT
      LAYER M5 ;
        RECT  214.992 0 215.016 0.084 ;
    END
  END tw_d0[151]
  PIN tw_d0[152]
    DIRECTION INPUT ;
    USE SIGNAL ;
    PORT
      LAYER M5 ;
        RECT  215.088 0 215.112 0.084 ;
    END
  END tw_d0[152]
  PIN tw_d0[153]
    DIRECTION INPUT ;
    USE SIGNAL ;
    PORT
      LAYER M5 ;
        RECT  215.184 0 215.208 0.084 ;
    END
  END tw_d0[153]
  PIN tw_d0[154]
    DIRECTION INPUT ;
    USE SIGNAL ;
    PORT
      LAYER M5 ;
        RECT  215.28 0 215.304 0.084 ;
    END
  END tw_d0[154]
  PIN tw_d0[155]
    DIRECTION INPUT ;
    USE SIGNAL ;
    PORT
      LAYER M5 ;
        RECT  215.376 0 215.4 0.084 ;
    END
  END tw_d0[155]
  PIN tw_d0[156]
    DIRECTION INPUT ;
    USE SIGNAL ;
    PORT
      LAYER M5 ;
        RECT  215.472 0 215.496 0.084 ;
    END
  END tw_d0[156]
  PIN tw_d0[157]
    DIRECTION INPUT ;
    USE SIGNAL ;
    PORT
      LAYER M5 ;
        RECT  215.568 0 215.592 0.084 ;
    END
  END tw_d0[157]
  PIN tw_d0[158]
    DIRECTION INPUT ;
    USE SIGNAL ;
    PORT
      LAYER M5 ;
        RECT  215.664 0 215.688 0.084 ;
    END
  END tw_d0[158]
  PIN tw_d0[159]
    DIRECTION INPUT ;
    USE SIGNAL ;
    PORT
      LAYER M5 ;
        RECT  215.76 0 215.784 0.084 ;
    END
  END tw_d0[159]
  PIN tw_d0[15]
    DIRECTION INPUT ;
    USE SIGNAL ;
    PORT
      LAYER M5 ;
        RECT  37.584 0 37.608 0.084 ;
    END
  END tw_d0[15]
  PIN tw_d0[160]
    DIRECTION INPUT ;
    USE SIGNAL ;
    PORT
      LAYER M5 ;
        RECT  215.856 0 215.88 0.084 ;
    END
  END tw_d0[160]
  PIN tw_d0[161]
    DIRECTION INPUT ;
    USE SIGNAL ;
    PORT
      LAYER M5 ;
        RECT  215.952 0 215.976 0.084 ;
    END
  END tw_d0[161]
  PIN tw_d0[162]
    DIRECTION INPUT ;
    USE SIGNAL ;
    PORT
      LAYER M5 ;
        RECT  216.048 0 216.072 0.084 ;
    END
  END tw_d0[162]
  PIN tw_d0[163]
    DIRECTION INPUT ;
    USE SIGNAL ;
    PORT
      LAYER M5 ;
        RECT  216.144 0 216.168 0.084 ;
    END
  END tw_d0[163]
  PIN tw_d0[164]
    DIRECTION INPUT ;
    USE SIGNAL ;
    PORT
      LAYER M5 ;
        RECT  216.24 0 216.264 0.084 ;
    END
  END tw_d0[164]
  PIN tw_d0[165]
    DIRECTION INPUT ;
    USE SIGNAL ;
    PORT
      LAYER M5 ;
        RECT  216.336 0 216.36 0.084 ;
    END
  END tw_d0[165]
  PIN tw_d0[166]
    DIRECTION INPUT ;
    USE SIGNAL ;
    PORT
      LAYER M5 ;
        RECT  216.432 0 216.456 0.084 ;
    END
  END tw_d0[166]
  PIN tw_d0[167]
    DIRECTION INPUT ;
    USE SIGNAL ;
    PORT
      LAYER M5 ;
        RECT  216.528 0 216.552 0.084 ;
    END
  END tw_d0[167]
  PIN tw_d0[168]
    DIRECTION INPUT ;
    USE SIGNAL ;
    PORT
      LAYER M5 ;
        RECT  216.624 0 216.648 0.084 ;
    END
  END tw_d0[168]
  PIN tw_d0[169]
    DIRECTION INPUT ;
    USE SIGNAL ;
    PORT
      LAYER M5 ;
        RECT  216.72 0 216.744 0.084 ;
    END
  END tw_d0[169]
  PIN tw_d0[16]
    DIRECTION INPUT ;
    USE SIGNAL ;
    PORT
      LAYER M5 ;
        RECT  37.68 0 37.704 0.084 ;
    END
  END tw_d0[16]
  PIN tw_d0[170]
    DIRECTION INPUT ;
    USE SIGNAL ;
    PORT
      LAYER M5 ;
        RECT  216.816 0 216.84 0.084 ;
    END
  END tw_d0[170]
  PIN tw_d0[171]
    DIRECTION INPUT ;
    USE SIGNAL ;
    PORT
      LAYER M5 ;
        RECT  216.912 0 216.936 0.084 ;
    END
  END tw_d0[171]
  PIN tw_d0[172]
    DIRECTION INPUT ;
    USE SIGNAL ;
    PORT
      LAYER M5 ;
        RECT  217.008 0 217.032 0.084 ;
    END
  END tw_d0[172]
  PIN tw_d0[173]
    DIRECTION INPUT ;
    USE SIGNAL ;
    PORT
      LAYER M5 ;
        RECT  217.104 0 217.128 0.084 ;
    END
  END tw_d0[173]
  PIN tw_d0[174]
    DIRECTION INPUT ;
    USE SIGNAL ;
    PORT
      LAYER M5 ;
        RECT  217.2 0 217.224 0.084 ;
    END
  END tw_d0[174]
  PIN tw_d0[175]
    DIRECTION INPUT ;
    USE SIGNAL ;
    PORT
      LAYER M5 ;
        RECT  217.296 0 217.32 0.084 ;
    END
  END tw_d0[175]
  PIN tw_d0[176]
    DIRECTION INPUT ;
    USE SIGNAL ;
    PORT
      LAYER M5 ;
        RECT  217.392 0 217.416 0.084 ;
    END
  END tw_d0[176]
  PIN tw_d0[177]
    DIRECTION INPUT ;
    USE SIGNAL ;
    PORT
      LAYER M5 ;
        RECT  217.488 0 217.512 0.084 ;
    END
  END tw_d0[177]
  PIN tw_d0[178]
    DIRECTION INPUT ;
    USE SIGNAL ;
    PORT
      LAYER M5 ;
        RECT  217.584 0 217.608 0.084 ;
    END
  END tw_d0[178]
  PIN tw_d0[179]
    DIRECTION INPUT ;
    USE SIGNAL ;
    PORT
      LAYER M5 ;
        RECT  217.68 0 217.704 0.084 ;
    END
  END tw_d0[179]
  PIN tw_d0[17]
    DIRECTION INPUT ;
    USE SIGNAL ;
    PORT
      LAYER M5 ;
        RECT  37.776 0 37.8 0.084 ;
    END
  END tw_d0[17]
  PIN tw_d0[180]
    DIRECTION INPUT ;
    USE SIGNAL ;
    PORT
      LAYER M5 ;
        RECT  217.776 0 217.8 0.084 ;
    END
  END tw_d0[180]
  PIN tw_d0[181]
    DIRECTION INPUT ;
    USE SIGNAL ;
    PORT
      LAYER M5 ;
        RECT  217.872 0 217.896 0.084 ;
    END
  END tw_d0[181]
  PIN tw_d0[182]
    DIRECTION INPUT ;
    USE SIGNAL ;
    PORT
      LAYER M5 ;
        RECT  217.968 0 217.992 0.084 ;
    END
  END tw_d0[182]
  PIN tw_d0[183]
    DIRECTION INPUT ;
    USE SIGNAL ;
    PORT
      LAYER M5 ;
        RECT  224.208 0 224.232 0.084 ;
    END
  END tw_d0[183]
  PIN tw_d0[184]
    DIRECTION INPUT ;
    USE SIGNAL ;
    PORT
      LAYER M5 ;
        RECT  224.304 0 224.328 0.084 ;
    END
  END tw_d0[184]
  PIN tw_d0[185]
    DIRECTION INPUT ;
    USE SIGNAL ;
    PORT
      LAYER M5 ;
        RECT  224.4 0 224.424 0.084 ;
    END
  END tw_d0[185]
  PIN tw_d0[186]
    DIRECTION INPUT ;
    USE SIGNAL ;
    PORT
      LAYER M5 ;
        RECT  224.496 0 224.52 0.084 ;
    END
  END tw_d0[186]
  PIN tw_d0[187]
    DIRECTION INPUT ;
    USE SIGNAL ;
    PORT
      LAYER M5 ;
        RECT  224.592 0 224.616 0.084 ;
    END
  END tw_d0[187]
  PIN tw_d0[188]
    DIRECTION INPUT ;
    USE SIGNAL ;
    PORT
      LAYER M5 ;
        RECT  224.688 0 224.712 0.084 ;
    END
  END tw_d0[188]
  PIN tw_d0[189]
    DIRECTION INPUT ;
    USE SIGNAL ;
    PORT
      LAYER M5 ;
        RECT  224.784 0 224.808 0.084 ;
    END
  END tw_d0[189]
  PIN tw_d0[18]
    DIRECTION INPUT ;
    USE SIGNAL ;
    PORT
      LAYER M5 ;
        RECT  37.872 0 37.896 0.084 ;
    END
  END tw_d0[18]
  PIN tw_d0[190]
    DIRECTION INPUT ;
    USE SIGNAL ;
    PORT
      LAYER M5 ;
        RECT  224.88 0 224.904 0.084 ;
    END
  END tw_d0[190]
  PIN tw_d0[191]
    DIRECTION INPUT ;
    USE SIGNAL ;
    PORT
      LAYER M5 ;
        RECT  224.976 0 225 0.084 ;
    END
  END tw_d0[191]
  PIN tw_d0[192]
    DIRECTION INPUT ;
    USE SIGNAL ;
    PORT
      LAYER M5 ;
        RECT  225.072 0 225.096 0.084 ;
    END
  END tw_d0[192]
  PIN tw_d0[193]
    DIRECTION INPUT ;
    USE SIGNAL ;
    PORT
      LAYER M5 ;
        RECT  225.168 0 225.192 0.084 ;
    END
  END tw_d0[193]
  PIN tw_d0[194]
    DIRECTION INPUT ;
    USE SIGNAL ;
    PORT
      LAYER M5 ;
        RECT  225.264 0 225.288 0.084 ;
    END
  END tw_d0[194]
  PIN tw_d0[195]
    DIRECTION INPUT ;
    USE SIGNAL ;
    PORT
      LAYER M5 ;
        RECT  225.36 0 225.384 0.084 ;
    END
  END tw_d0[195]
  PIN tw_d0[196]
    DIRECTION INPUT ;
    USE SIGNAL ;
    PORT
      LAYER M5 ;
        RECT  225.456 0 225.48 0.084 ;
    END
  END tw_d0[196]
  PIN tw_d0[197]
    DIRECTION INPUT ;
    USE SIGNAL ;
    PORT
      LAYER M5 ;
        RECT  225.552 0 225.576 0.084 ;
    END
  END tw_d0[197]
  PIN tw_d0[198]
    DIRECTION INPUT ;
    USE SIGNAL ;
    PORT
      LAYER M5 ;
        RECT  225.648 0 225.672 0.084 ;
    END
  END tw_d0[198]
  PIN tw_d0[199]
    DIRECTION INPUT ;
    USE SIGNAL ;
    PORT
      LAYER M5 ;
        RECT  225.744 0 225.768 0.084 ;
    END
  END tw_d0[199]
  PIN tw_d0[19]
    DIRECTION INPUT ;
    USE SIGNAL ;
    PORT
      LAYER M5 ;
        RECT  37.968 0 37.992 0.084 ;
    END
  END tw_d0[19]
  PIN tw_d0[1]
    DIRECTION INPUT ;
    USE SIGNAL ;
    PORT
      LAYER M5 ;
        RECT  36.24 0 36.264 0.084 ;
    END
  END tw_d0[1]
  PIN tw_d0[200]
    DIRECTION INPUT ;
    USE SIGNAL ;
    PORT
      LAYER M5 ;
        RECT  225.84 0 225.864 0.084 ;
    END
  END tw_d0[200]
  PIN tw_d0[201]
    DIRECTION INPUT ;
    USE SIGNAL ;
    PORT
      LAYER M5 ;
        RECT  225.936 0 225.96 0.084 ;
    END
  END tw_d0[201]
  PIN tw_d0[202]
    DIRECTION INPUT ;
    USE SIGNAL ;
    PORT
      LAYER M5 ;
        RECT  226.032 0 226.056 0.084 ;
    END
  END tw_d0[202]
  PIN tw_d0[203]
    DIRECTION INPUT ;
    USE SIGNAL ;
    PORT
      LAYER M5 ;
        RECT  226.128 0 226.152 0.084 ;
    END
  END tw_d0[203]
  PIN tw_d0[204]
    DIRECTION INPUT ;
    USE SIGNAL ;
    PORT
      LAYER M5 ;
        RECT  226.224 0 226.248 0.084 ;
    END
  END tw_d0[204]
  PIN tw_d0[205]
    DIRECTION INPUT ;
    USE SIGNAL ;
    PORT
      LAYER M5 ;
        RECT  226.32 0 226.344 0.084 ;
    END
  END tw_d0[205]
  PIN tw_d0[206]
    DIRECTION INPUT ;
    USE SIGNAL ;
    PORT
      LAYER M5 ;
        RECT  226.416 0 226.44 0.084 ;
    END
  END tw_d0[206]
  PIN tw_d0[207]
    DIRECTION INPUT ;
    USE SIGNAL ;
    PORT
      LAYER M5 ;
        RECT  226.512 0 226.536 0.084 ;
    END
  END tw_d0[207]
  PIN tw_d0[208]
    DIRECTION INPUT ;
    USE SIGNAL ;
    PORT
      LAYER M5 ;
        RECT  226.608 0 226.632 0.084 ;
    END
  END tw_d0[208]
  PIN tw_d0[209]
    DIRECTION INPUT ;
    USE SIGNAL ;
    PORT
      LAYER M5 ;
        RECT  226.704 0 226.728 0.084 ;
    END
  END tw_d0[209]
  PIN tw_d0[20]
    DIRECTION INPUT ;
    USE SIGNAL ;
    PORT
      LAYER M5 ;
        RECT  38.064 0 38.088 0.084 ;
    END
  END tw_d0[20]
  PIN tw_d0[210]
    DIRECTION INPUT ;
    USE SIGNAL ;
    PORT
      LAYER M5 ;
        RECT  226.8 0 226.824 0.084 ;
    END
  END tw_d0[210]
  PIN tw_d0[211]
    DIRECTION INPUT ;
    USE SIGNAL ;
    PORT
      LAYER M5 ;
        RECT  226.896 0 226.92 0.084 ;
    END
  END tw_d0[211]
  PIN tw_d0[212]
    DIRECTION INPUT ;
    USE SIGNAL ;
    PORT
      LAYER M5 ;
        RECT  226.992 0 227.016 0.084 ;
    END
  END tw_d0[212]
  PIN tw_d0[213]
    DIRECTION INPUT ;
    USE SIGNAL ;
    PORT
      LAYER M5 ;
        RECT  227.088 0 227.112 0.084 ;
    END
  END tw_d0[213]
  PIN tw_d0[214]
    DIRECTION INPUT ;
    USE SIGNAL ;
    PORT
      LAYER M5 ;
        RECT  227.184 0 227.208 0.084 ;
    END
  END tw_d0[214]
  PIN tw_d0[215]
    DIRECTION INPUT ;
    USE SIGNAL ;
    PORT
      LAYER M5 ;
        RECT  227.28 0 227.304 0.084 ;
    END
  END tw_d0[215]
  PIN tw_d0[216]
    DIRECTION INPUT ;
    USE SIGNAL ;
    PORT
      LAYER M5 ;
        RECT  227.376 0 227.4 0.084 ;
    END
  END tw_d0[216]
  PIN tw_d0[217]
    DIRECTION INPUT ;
    USE SIGNAL ;
    PORT
      LAYER M5 ;
        RECT  227.472 0 227.496 0.084 ;
    END
  END tw_d0[217]
  PIN tw_d0[218]
    DIRECTION INPUT ;
    USE SIGNAL ;
    PORT
      LAYER M5 ;
        RECT  227.568 0 227.592 0.084 ;
    END
  END tw_d0[218]
  PIN tw_d0[219]
    DIRECTION INPUT ;
    USE SIGNAL ;
    PORT
      LAYER M5 ;
        RECT  227.664 0 227.688 0.084 ;
    END
  END tw_d0[219]
  PIN tw_d0[21]
    DIRECTION INPUT ;
    USE SIGNAL ;
    PORT
      LAYER M5 ;
        RECT  38.16 0 38.184 0.084 ;
    END
  END tw_d0[21]
  PIN tw_d0[220]
    DIRECTION INPUT ;
    USE SIGNAL ;
    PORT
      LAYER M5 ;
        RECT  227.76 0 227.784 0.084 ;
    END
  END tw_d0[220]
  PIN tw_d0[221]
    DIRECTION INPUT ;
    USE SIGNAL ;
    PORT
      LAYER M5 ;
        RECT  227.856 0 227.88 0.084 ;
    END
  END tw_d0[221]
  PIN tw_d0[222]
    DIRECTION INPUT ;
    USE SIGNAL ;
    PORT
      LAYER M5 ;
        RECT  227.952 0 227.976 0.084 ;
    END
  END tw_d0[222]
  PIN tw_d0[223]
    DIRECTION INPUT ;
    USE SIGNAL ;
    PORT
      LAYER M5 ;
        RECT  228.048 0 228.072 0.084 ;
    END
  END tw_d0[223]
  PIN tw_d0[224]
    DIRECTION INPUT ;
    USE SIGNAL ;
    PORT
      LAYER M5 ;
        RECT  228.144 0 228.168 0.084 ;
    END
  END tw_d0[224]
  PIN tw_d0[225]
    DIRECTION INPUT ;
    USE SIGNAL ;
    PORT
      LAYER M5 ;
        RECT  228.24 0 228.264 0.084 ;
    END
  END tw_d0[225]
  PIN tw_d0[226]
    DIRECTION INPUT ;
    USE SIGNAL ;
    PORT
      LAYER M5 ;
        RECT  228.336 0 228.36 0.084 ;
    END
  END tw_d0[226]
  PIN tw_d0[227]
    DIRECTION INPUT ;
    USE SIGNAL ;
    PORT
      LAYER M5 ;
        RECT  228.432 0 228.456 0.084 ;
    END
  END tw_d0[227]
  PIN tw_d0[228]
    DIRECTION INPUT ;
    USE SIGNAL ;
    PORT
      LAYER M5 ;
        RECT  228.528 0 228.552 0.084 ;
    END
  END tw_d0[228]
  PIN tw_d0[229]
    DIRECTION INPUT ;
    USE SIGNAL ;
    PORT
      LAYER M5 ;
        RECT  228.624 0 228.648 0.084 ;
    END
  END tw_d0[229]
  PIN tw_d0[22]
    DIRECTION INPUT ;
    USE SIGNAL ;
    PORT
      LAYER M5 ;
        RECT  38.256 0 38.28 0.084 ;
    END
  END tw_d0[22]
  PIN tw_d0[230]
    DIRECTION INPUT ;
    USE SIGNAL ;
    PORT
      LAYER M5 ;
        RECT  228.72 0 228.744 0.084 ;
    END
  END tw_d0[230]
  PIN tw_d0[231]
    DIRECTION INPUT ;
    USE SIGNAL ;
    PORT
      LAYER M5 ;
        RECT  228.816 0 228.84 0.084 ;
    END
  END tw_d0[231]
  PIN tw_d0[232]
    DIRECTION INPUT ;
    USE SIGNAL ;
    PORT
      LAYER M5 ;
        RECT  228.912 0 228.936 0.084 ;
    END
  END tw_d0[232]
  PIN tw_d0[233]
    DIRECTION INPUT ;
    USE SIGNAL ;
    PORT
      LAYER M5 ;
        RECT  229.008 0 229.032 0.084 ;
    END
  END tw_d0[233]
  PIN tw_d0[234]
    DIRECTION INPUT ;
    USE SIGNAL ;
    PORT
      LAYER M5 ;
        RECT  229.104 0 229.128 0.084 ;
    END
  END tw_d0[234]
  PIN tw_d0[235]
    DIRECTION INPUT ;
    USE SIGNAL ;
    PORT
      LAYER M5 ;
        RECT  229.2 0 229.224 0.084 ;
    END
  END tw_d0[235]
  PIN tw_d0[236]
    DIRECTION INPUT ;
    USE SIGNAL ;
    PORT
      LAYER M5 ;
        RECT  229.296 0 229.32 0.084 ;
    END
  END tw_d0[236]
  PIN tw_d0[237]
    DIRECTION INPUT ;
    USE SIGNAL ;
    PORT
      LAYER M5 ;
        RECT  229.392 0 229.416 0.084 ;
    END
  END tw_d0[237]
  PIN tw_d0[238]
    DIRECTION INPUT ;
    USE SIGNAL ;
    PORT
      LAYER M5 ;
        RECT  229.488 0 229.512 0.084 ;
    END
  END tw_d0[238]
  PIN tw_d0[239]
    DIRECTION INPUT ;
    USE SIGNAL ;
    PORT
      LAYER M5 ;
        RECT  229.584 0 229.608 0.084 ;
    END
  END tw_d0[239]
  PIN tw_d0[23]
    DIRECTION INPUT ;
    USE SIGNAL ;
    PORT
      LAYER M5 ;
        RECT  29.136 0 29.16 0.084 ;
    END
  END tw_d0[23]
  PIN tw_d0[240]
    DIRECTION INPUT ;
    USE SIGNAL ;
    PORT
      LAYER M5 ;
        RECT  229.68 0 229.704 0.084 ;
    END
  END tw_d0[240]
  PIN tw_d0[241]
    DIRECTION INPUT ;
    USE SIGNAL ;
    PORT
      LAYER M5 ;
        RECT  229.776 0 229.8 0.084 ;
    END
  END tw_d0[241]
  PIN tw_d0[242]
    DIRECTION INPUT ;
    USE SIGNAL ;
    PORT
      LAYER M5 ;
        RECT  229.872 0 229.896 0.084 ;
    END
  END tw_d0[242]
  PIN tw_d0[243]
    DIRECTION INPUT ;
    USE SIGNAL ;
    PORT
      LAYER M5 ;
        RECT  229.968 0 229.992 0.084 ;
    END
  END tw_d0[243]
  PIN tw_d0[244]
    DIRECTION INPUT ;
    USE SIGNAL ;
    PORT
      LAYER M5 ;
        RECT  230.064 0 230.088 0.084 ;
    END
  END tw_d0[244]
  PIN tw_d0[245]
    DIRECTION INPUT ;
    USE SIGNAL ;
    PORT
      LAYER M5 ;
        RECT  230.16 0 230.184 0.084 ;
    END
  END tw_d0[245]
  PIN tw_d0[246]
    DIRECTION INPUT ;
    USE SIGNAL ;
    PORT
      LAYER M5 ;
        RECT  230.256 0 230.28 0.084 ;
    END
  END tw_d0[246]
  PIN tw_d0[247]
    DIRECTION INPUT ;
    USE SIGNAL ;
    PORT
      LAYER M5 ;
        RECT  48.336 0 48.36 0.084 ;
    END
  END tw_d0[247]
  PIN tw_d0[248]
    DIRECTION INPUT ;
    USE SIGNAL ;
    PORT
      LAYER M5 ;
        RECT  48.432 0 48.456 0.084 ;
    END
  END tw_d0[248]
  PIN tw_d0[249]
    DIRECTION INPUT ;
    USE SIGNAL ;
    PORT
      LAYER M5 ;
        RECT  48.528 0 48.552 0.084 ;
    END
  END tw_d0[249]
  PIN tw_d0[24]
    DIRECTION INPUT ;
    USE SIGNAL ;
    PORT
      LAYER M5 ;
        RECT  29.232 0 29.256 0.084 ;
    END
  END tw_d0[24]
  PIN tw_d0[250]
    DIRECTION INPUT ;
    USE SIGNAL ;
    PORT
      LAYER M5 ;
        RECT  48.624 0 48.648 0.084 ;
    END
  END tw_d0[250]
  PIN tw_d0[251]
    DIRECTION INPUT ;
    USE SIGNAL ;
    PORT
      LAYER M5 ;
        RECT  48.72 0 48.744 0.084 ;
    END
  END tw_d0[251]
  PIN tw_d0[252]
    DIRECTION INPUT ;
    USE SIGNAL ;
    PORT
      LAYER M5 ;
        RECT  48.816 0 48.84 0.084 ;
    END
  END tw_d0[252]
  PIN tw_d0[253]
    DIRECTION INPUT ;
    USE SIGNAL ;
    PORT
      LAYER M5 ;
        RECT  48.912 0 48.936 0.084 ;
    END
  END tw_d0[253]
  PIN tw_d0[254]
    DIRECTION INPUT ;
    USE SIGNAL ;
    PORT
      LAYER M5 ;
        RECT  49.008 0 49.032 0.084 ;
    END
  END tw_d0[254]
  PIN tw_d0[255]
    DIRECTION INPUT ;
    USE SIGNAL ;
    PORT
      LAYER M5 ;
        RECT  49.104 0 49.128 0.084 ;
    END
  END tw_d0[255]
  PIN tw_d0[256]
    DIRECTION INPUT ;
    USE SIGNAL ;
    PORT
      LAYER M5 ;
        RECT  49.2 0 49.224 0.084 ;
    END
  END tw_d0[256]
  PIN tw_d0[257]
    DIRECTION INPUT ;
    USE SIGNAL ;
    PORT
      LAYER M5 ;
        RECT  49.296 0 49.32 0.084 ;
    END
  END tw_d0[257]
  PIN tw_d0[258]
    DIRECTION INPUT ;
    USE SIGNAL ;
    PORT
      LAYER M5 ;
        RECT  49.392 0 49.416 0.084 ;
    END
  END tw_d0[258]
  PIN tw_d0[259]
    DIRECTION INPUT ;
    USE SIGNAL ;
    PORT
      LAYER M5 ;
        RECT  49.488 0 49.512 0.084 ;
    END
  END tw_d0[259]
  PIN tw_d0[25]
    DIRECTION INPUT ;
    USE SIGNAL ;
    PORT
      LAYER M5 ;
        RECT  29.328 0 29.352 0.084 ;
    END
  END tw_d0[25]
  PIN tw_d0[260]
    DIRECTION INPUT ;
    USE SIGNAL ;
    PORT
      LAYER M5 ;
        RECT  49.584 0 49.608 0.084 ;
    END
  END tw_d0[260]
  PIN tw_d0[261]
    DIRECTION INPUT ;
    USE SIGNAL ;
    PORT
      LAYER M5 ;
        RECT  49.68 0 49.704 0.084 ;
    END
  END tw_d0[261]
  PIN tw_d0[262]
    DIRECTION INPUT ;
    USE SIGNAL ;
    PORT
      LAYER M5 ;
        RECT  49.776 0 49.8 0.084 ;
    END
  END tw_d0[262]
  PIN tw_d0[263]
    DIRECTION INPUT ;
    USE SIGNAL ;
    PORT
      LAYER M5 ;
        RECT  49.872 0 49.896 0.084 ;
    END
  END tw_d0[263]
  PIN tw_d0[264]
    DIRECTION INPUT ;
    USE SIGNAL ;
    PORT
      LAYER M5 ;
        RECT  49.968 0 49.992 0.084 ;
    END
  END tw_d0[264]
  PIN tw_d0[265]
    DIRECTION INPUT ;
    USE SIGNAL ;
    PORT
      LAYER M5 ;
        RECT  50.064 0 50.088 0.084 ;
    END
  END tw_d0[265]
  PIN tw_d0[266]
    DIRECTION INPUT ;
    USE SIGNAL ;
    PORT
      LAYER M5 ;
        RECT  50.16 0 50.184 0.084 ;
    END
  END tw_d0[266]
  PIN tw_d0[267]
    DIRECTION INPUT ;
    USE SIGNAL ;
    PORT
      LAYER M5 ;
        RECT  50.256 0 50.28 0.084 ;
    END
  END tw_d0[267]
  PIN tw_d0[268]
    DIRECTION INPUT ;
    USE SIGNAL ;
    PORT
      LAYER M5 ;
        RECT  50.352 0 50.376 0.084 ;
    END
  END tw_d0[268]
  PIN tw_d0[269]
    DIRECTION INPUT ;
    USE SIGNAL ;
    PORT
      LAYER M5 ;
        RECT  50.448 0 50.472 0.084 ;
    END
  END tw_d0[269]
  PIN tw_d0[26]
    DIRECTION INPUT ;
    USE SIGNAL ;
    PORT
      LAYER M5 ;
        RECT  29.424 0 29.448 0.084 ;
    END
  END tw_d0[26]
  PIN tw_d0[270]
    DIRECTION INPUT ;
    USE SIGNAL ;
    PORT
      LAYER M5 ;
        RECT  50.544 0 50.568 0.084 ;
    END
  END tw_d0[270]
  PIN tw_d0[271]
    DIRECTION INPUT ;
    USE SIGNAL ;
    PORT
      LAYER M5 ;
        RECT  50.64 0 50.664 0.084 ;
    END
  END tw_d0[271]
  PIN tw_d0[272]
    DIRECTION INPUT ;
    USE SIGNAL ;
    PORT
      LAYER M5 ;
        RECT  50.736 0 50.76 0.084 ;
    END
  END tw_d0[272]
  PIN tw_d0[273]
    DIRECTION INPUT ;
    USE SIGNAL ;
    PORT
      LAYER M5 ;
        RECT  50.832 0 50.856 0.084 ;
    END
  END tw_d0[273]
  PIN tw_d0[274]
    DIRECTION INPUT ;
    USE SIGNAL ;
    PORT
      LAYER M5 ;
        RECT  50.928 0 50.952 0.084 ;
    END
  END tw_d0[274]
  PIN tw_d0[275]
    DIRECTION INPUT ;
    USE SIGNAL ;
    PORT
      LAYER M5 ;
        RECT  51.024 0 51.048 0.084 ;
    END
  END tw_d0[275]
  PIN tw_d0[276]
    DIRECTION INPUT ;
    USE SIGNAL ;
    PORT
      LAYER M5 ;
        RECT  51.12 0 51.144 0.084 ;
    END
  END tw_d0[276]
  PIN tw_d0[277]
    DIRECTION INPUT ;
    USE SIGNAL ;
    PORT
      LAYER M5 ;
        RECT  51.216 0 51.24 0.084 ;
    END
  END tw_d0[277]
  PIN tw_d0[278]
    DIRECTION INPUT ;
    USE SIGNAL ;
    PORT
      LAYER M5 ;
        RECT  51.312 0 51.336 0.084 ;
    END
  END tw_d0[278]
  PIN tw_d0[279]
    DIRECTION INPUT ;
    USE SIGNAL ;
    PORT
      LAYER M5 ;
        RECT  26.064 0 26.088 0.084 ;
    END
  END tw_d0[279]
  PIN tw_d0[27]
    DIRECTION INPUT ;
    USE SIGNAL ;
    PORT
      LAYER M5 ;
        RECT  29.52 0 29.544 0.084 ;
    END
  END tw_d0[27]
  PIN tw_d0[280]
    DIRECTION INPUT ;
    USE SIGNAL ;
    PORT
      LAYER M5 ;
        RECT  26.16 0 26.184 0.084 ;
    END
  END tw_d0[280]
  PIN tw_d0[281]
    DIRECTION INPUT ;
    USE SIGNAL ;
    PORT
      LAYER M5 ;
        RECT  26.256 0 26.28 0.084 ;
    END
  END tw_d0[281]
  PIN tw_d0[282]
    DIRECTION INPUT ;
    USE SIGNAL ;
    PORT
      LAYER M5 ;
        RECT  26.352 0 26.376 0.084 ;
    END
  END tw_d0[282]
  PIN tw_d0[283]
    DIRECTION INPUT ;
    USE SIGNAL ;
    PORT
      LAYER M5 ;
        RECT  26.448 0 26.472 0.084 ;
    END
  END tw_d0[283]
  PIN tw_d0[284]
    DIRECTION INPUT ;
    USE SIGNAL ;
    PORT
      LAYER M5 ;
        RECT  26.544 0 26.568 0.084 ;
    END
  END tw_d0[284]
  PIN tw_d0[285]
    DIRECTION INPUT ;
    USE SIGNAL ;
    PORT
      LAYER M5 ;
        RECT  26.64 0 26.664 0.084 ;
    END
  END tw_d0[285]
  PIN tw_d0[286]
    DIRECTION INPUT ;
    USE SIGNAL ;
    PORT
      LAYER M5 ;
        RECT  26.736 0 26.76 0.084 ;
    END
  END tw_d0[286]
  PIN tw_d0[287]
    DIRECTION INPUT ;
    USE SIGNAL ;
    PORT
      LAYER M5 ;
        RECT  26.832 0 26.856 0.084 ;
    END
  END tw_d0[287]
  PIN tw_d0[288]
    DIRECTION INPUT ;
    USE SIGNAL ;
    PORT
      LAYER M5 ;
        RECT  26.928 0 26.952 0.084 ;
    END
  END tw_d0[288]
  PIN tw_d0[289]
    DIRECTION INPUT ;
    USE SIGNAL ;
    PORT
      LAYER M5 ;
        RECT  27.024 0 27.048 0.084 ;
    END
  END tw_d0[289]
  PIN tw_d0[28]
    DIRECTION INPUT ;
    USE SIGNAL ;
    PORT
      LAYER M5 ;
        RECT  29.616 0 29.64 0.084 ;
    END
  END tw_d0[28]
  PIN tw_d0[290]
    DIRECTION INPUT ;
    USE SIGNAL ;
    PORT
      LAYER M5 ;
        RECT  27.12 0 27.144 0.084 ;
    END
  END tw_d0[290]
  PIN tw_d0[291]
    DIRECTION INPUT ;
    USE SIGNAL ;
    PORT
      LAYER M5 ;
        RECT  27.216 0 27.24 0.084 ;
    END
  END tw_d0[291]
  PIN tw_d0[292]
    DIRECTION INPUT ;
    USE SIGNAL ;
    PORT
      LAYER M5 ;
        RECT  27.312 0 27.336 0.084 ;
    END
  END tw_d0[292]
  PIN tw_d0[293]
    DIRECTION INPUT ;
    USE SIGNAL ;
    PORT
      LAYER M5 ;
        RECT  27.408 0 27.432 0.084 ;
    END
  END tw_d0[293]
  PIN tw_d0[294]
    DIRECTION INPUT ;
    USE SIGNAL ;
    PORT
      LAYER M5 ;
        RECT  27.504 0 27.528 0.084 ;
    END
  END tw_d0[294]
  PIN tw_d0[295]
    DIRECTION INPUT ;
    USE SIGNAL ;
    PORT
      LAYER M5 ;
        RECT  27.6 0 27.624 0.084 ;
    END
  END tw_d0[295]
  PIN tw_d0[296]
    DIRECTION INPUT ;
    USE SIGNAL ;
    PORT
      LAYER M5 ;
        RECT  27.696 0 27.72 0.084 ;
    END
  END tw_d0[296]
  PIN tw_d0[297]
    DIRECTION INPUT ;
    USE SIGNAL ;
    PORT
      LAYER M5 ;
        RECT  27.792 0 27.816 0.084 ;
    END
  END tw_d0[297]
  PIN tw_d0[298]
    DIRECTION INPUT ;
    USE SIGNAL ;
    PORT
      LAYER M5 ;
        RECT  27.888 0 27.912 0.084 ;
    END
  END tw_d0[298]
  PIN tw_d0[299]
    DIRECTION INPUT ;
    USE SIGNAL ;
    PORT
      LAYER M5 ;
        RECT  27.984 0 28.008 0.084 ;
    END
  END tw_d0[299]
  PIN tw_d0[29]
    DIRECTION INPUT ;
    USE SIGNAL ;
    PORT
      LAYER M5 ;
        RECT  29.712 0 29.736 0.084 ;
    END
  END tw_d0[29]
  PIN tw_d0[2]
    DIRECTION INPUT ;
    USE SIGNAL ;
    PORT
      LAYER M5 ;
        RECT  36.336 0 36.36 0.084 ;
    END
  END tw_d0[2]
  PIN tw_d0[300]
    DIRECTION INPUT ;
    USE SIGNAL ;
    PORT
      LAYER M5 ;
        RECT  28.08 0 28.104 0.084 ;
    END
  END tw_d0[300]
  PIN tw_d0[301]
    DIRECTION INPUT ;
    USE SIGNAL ;
    PORT
      LAYER M5 ;
        RECT  28.176 0 28.2 0.084 ;
    END
  END tw_d0[301]
  PIN tw_d0[302]
    DIRECTION INPUT ;
    USE SIGNAL ;
    PORT
      LAYER M5 ;
        RECT  28.272 0 28.296 0.084 ;
    END
  END tw_d0[302]
  PIN tw_d0[303]
    DIRECTION INPUT ;
    USE SIGNAL ;
    PORT
      LAYER M5 ;
        RECT  28.368 0 28.392 0.084 ;
    END
  END tw_d0[303]
  PIN tw_d0[304]
    DIRECTION INPUT ;
    USE SIGNAL ;
    PORT
      LAYER M5 ;
        RECT  28.464 0 28.488 0.084 ;
    END
  END tw_d0[304]
  PIN tw_d0[305]
    DIRECTION INPUT ;
    USE SIGNAL ;
    PORT
      LAYER M5 ;
        RECT  28.56 0 28.584 0.084 ;
    END
  END tw_d0[305]
  PIN tw_d0[306]
    DIRECTION INPUT ;
    USE SIGNAL ;
    PORT
      LAYER M5 ;
        RECT  28.656 0 28.68 0.084 ;
    END
  END tw_d0[306]
  PIN tw_d0[307]
    DIRECTION INPUT ;
    USE SIGNAL ;
    PORT
      LAYER M5 ;
        RECT  28.752 0 28.776 0.084 ;
    END
  END tw_d0[307]
  PIN tw_d0[308]
    DIRECTION INPUT ;
    USE SIGNAL ;
    PORT
      LAYER M5 ;
        RECT  28.848 0 28.872 0.084 ;
    END
  END tw_d0[308]
  PIN tw_d0[309]
    DIRECTION INPUT ;
    USE SIGNAL ;
    PORT
      LAYER M5 ;
        RECT  28.944 0 28.968 0.084 ;
    END
  END tw_d0[309]
  PIN tw_d0[30]
    DIRECTION INPUT ;
    USE SIGNAL ;
    PORT
      LAYER M5 ;
        RECT  29.808 0 29.832 0.084 ;
    END
  END tw_d0[30]
  PIN tw_d0[310]
    DIRECTION INPUT ;
    USE SIGNAL ;
    PORT
      LAYER M5 ;
        RECT  29.04 0 29.064 0.084 ;
    END
  END tw_d0[310]
  PIN tw_d0[311]
    DIRECTION INPUT ;
    USE SIGNAL ;
    PORT
      LAYER M5 ;
        RECT  19.92 0 19.944 0.084 ;
    END
  END tw_d0[311]
  PIN tw_d0[312]
    DIRECTION INPUT ;
    USE SIGNAL ;
    PORT
      LAYER M5 ;
        RECT  20.016 0 20.04 0.084 ;
    END
  END tw_d0[312]
  PIN tw_d0[313]
    DIRECTION INPUT ;
    USE SIGNAL ;
    PORT
      LAYER M5 ;
        RECT  20.112 0 20.136 0.084 ;
    END
  END tw_d0[313]
  PIN tw_d0[314]
    DIRECTION INPUT ;
    USE SIGNAL ;
    PORT
      LAYER M5 ;
        RECT  20.208 0 20.232 0.084 ;
    END
  END tw_d0[314]
  PIN tw_d0[315]
    DIRECTION INPUT ;
    USE SIGNAL ;
    PORT
      LAYER M5 ;
        RECT  20.304 0 20.328 0.084 ;
    END
  END tw_d0[315]
  PIN tw_d0[316]
    DIRECTION INPUT ;
    USE SIGNAL ;
    PORT
      LAYER M5 ;
        RECT  20.4 0 20.424 0.084 ;
    END
  END tw_d0[316]
  PIN tw_d0[317]
    DIRECTION INPUT ;
    USE SIGNAL ;
    PORT
      LAYER M5 ;
        RECT  20.496 0 20.52 0.084 ;
    END
  END tw_d0[317]
  PIN tw_d0[318]
    DIRECTION INPUT ;
    USE SIGNAL ;
    PORT
      LAYER M5 ;
        RECT  20.592 0 20.616 0.084 ;
    END
  END tw_d0[318]
  PIN tw_d0[319]
    DIRECTION INPUT ;
    USE SIGNAL ;
    PORT
      LAYER M5 ;
        RECT  20.688 0 20.712 0.084 ;
    END
  END tw_d0[319]
  PIN tw_d0[31]
    DIRECTION INPUT ;
    USE SIGNAL ;
    PORT
      LAYER M5 ;
        RECT  29.904 0 29.928 0.084 ;
    END
  END tw_d0[31]
  PIN tw_d0[320]
    DIRECTION INPUT ;
    USE SIGNAL ;
    PORT
      LAYER M5 ;
        RECT  20.784 0 20.808 0.084 ;
    END
  END tw_d0[320]
  PIN tw_d0[321]
    DIRECTION INPUT ;
    USE SIGNAL ;
    PORT
      LAYER M5 ;
        RECT  20.88 0 20.904 0.084 ;
    END
  END tw_d0[321]
  PIN tw_d0[322]
    DIRECTION INPUT ;
    USE SIGNAL ;
    PORT
      LAYER M5 ;
        RECT  20.976 0 21 0.084 ;
    END
  END tw_d0[322]
  PIN tw_d0[323]
    DIRECTION INPUT ;
    USE SIGNAL ;
    PORT
      LAYER M5 ;
        RECT  21.072 0 21.096 0.084 ;
    END
  END tw_d0[323]
  PIN tw_d0[324]
    DIRECTION INPUT ;
    USE SIGNAL ;
    PORT
      LAYER M5 ;
        RECT  21.168 0 21.192 0.084 ;
    END
  END tw_d0[324]
  PIN tw_d0[325]
    DIRECTION INPUT ;
    USE SIGNAL ;
    PORT
      LAYER M5 ;
        RECT  21.264 0 21.288 0.084 ;
    END
  END tw_d0[325]
  PIN tw_d0[326]
    DIRECTION INPUT ;
    USE SIGNAL ;
    PORT
      LAYER M5 ;
        RECT  21.36 0 21.384 0.084 ;
    END
  END tw_d0[326]
  PIN tw_d0[327]
    DIRECTION INPUT ;
    USE SIGNAL ;
    PORT
      LAYER M5 ;
        RECT  21.456 0 21.48 0.084 ;
    END
  END tw_d0[327]
  PIN tw_d0[328]
    DIRECTION INPUT ;
    USE SIGNAL ;
    PORT
      LAYER M5 ;
        RECT  21.552 0 21.576 0.084 ;
    END
  END tw_d0[328]
  PIN tw_d0[329]
    DIRECTION INPUT ;
    USE SIGNAL ;
    PORT
      LAYER M5 ;
        RECT  21.648 0 21.672 0.084 ;
    END
  END tw_d0[329]
  PIN tw_d0[32]
    DIRECTION INPUT ;
    USE SIGNAL ;
    PORT
      LAYER M5 ;
        RECT  30 0 30.024 0.084 ;
    END
  END tw_d0[32]
  PIN tw_d0[330]
    DIRECTION INPUT ;
    USE SIGNAL ;
    PORT
      LAYER M5 ;
        RECT  21.744 0 21.768 0.084 ;
    END
  END tw_d0[330]
  PIN tw_d0[331]
    DIRECTION INPUT ;
    USE SIGNAL ;
    PORT
      LAYER M5 ;
        RECT  21.84 0 21.864 0.084 ;
    END
  END tw_d0[331]
  PIN tw_d0[332]
    DIRECTION INPUT ;
    USE SIGNAL ;
    PORT
      LAYER M5 ;
        RECT  21.936 0 21.96 0.084 ;
    END
  END tw_d0[332]
  PIN tw_d0[333]
    DIRECTION INPUT ;
    USE SIGNAL ;
    PORT
      LAYER M5 ;
        RECT  22.032 0 22.056 0.084 ;
    END
  END tw_d0[333]
  PIN tw_d0[334]
    DIRECTION INPUT ;
    USE SIGNAL ;
    PORT
      LAYER M5 ;
        RECT  22.128 0 22.152 0.084 ;
    END
  END tw_d0[334]
  PIN tw_d0[335]
    DIRECTION INPUT ;
    USE SIGNAL ;
    PORT
      LAYER M5 ;
        RECT  22.224 0 22.248 0.084 ;
    END
  END tw_d0[335]
  PIN tw_d0[336]
    DIRECTION INPUT ;
    USE SIGNAL ;
    PORT
      LAYER M5 ;
        RECT  22.32 0 22.344 0.084 ;
    END
  END tw_d0[336]
  PIN tw_d0[337]
    DIRECTION INPUT ;
    USE SIGNAL ;
    PORT
      LAYER M5 ;
        RECT  22.416 0 22.44 0.084 ;
    END
  END tw_d0[337]
  PIN tw_d0[338]
    DIRECTION INPUT ;
    USE SIGNAL ;
    PORT
      LAYER M5 ;
        RECT  22.512 0 22.536 0.084 ;
    END
  END tw_d0[338]
  PIN tw_d0[339]
    DIRECTION INPUT ;
    USE SIGNAL ;
    PORT
      LAYER M5 ;
        RECT  22.608 0 22.632 0.084 ;
    END
  END tw_d0[339]
  PIN tw_d0[33]
    DIRECTION INPUT ;
    USE SIGNAL ;
    PORT
      LAYER M5 ;
        RECT  30.096 0 30.12 0.084 ;
    END
  END tw_d0[33]
  PIN tw_d0[340]
    DIRECTION INPUT ;
    USE SIGNAL ;
    PORT
      LAYER M5 ;
        RECT  22.704 0 22.728 0.084 ;
    END
  END tw_d0[340]
  PIN tw_d0[341]
    DIRECTION INPUT ;
    USE SIGNAL ;
    PORT
      LAYER M5 ;
        RECT  22.8 0 22.824 0.084 ;
    END
  END tw_d0[341]
  PIN tw_d0[342]
    DIRECTION INPUT ;
    USE SIGNAL ;
    PORT
      LAYER M5 ;
        RECT  22.896 0 22.92 0.084 ;
    END
  END tw_d0[342]
  PIN tw_d0[343]
    DIRECTION INPUT ;
    USE SIGNAL ;
    PORT
      LAYER M5 ;
        RECT  45.264 0 45.288 0.084 ;
    END
  END tw_d0[343]
  PIN tw_d0[344]
    DIRECTION INPUT ;
    USE SIGNAL ;
    PORT
      LAYER M5 ;
        RECT  45.36 0 45.384 0.084 ;
    END
  END tw_d0[344]
  PIN tw_d0[345]
    DIRECTION INPUT ;
    USE SIGNAL ;
    PORT
      LAYER M5 ;
        RECT  45.456 0 45.48 0.084 ;
    END
  END tw_d0[345]
  PIN tw_d0[346]
    DIRECTION INPUT ;
    USE SIGNAL ;
    PORT
      LAYER M5 ;
        RECT  45.552 0 45.576 0.084 ;
    END
  END tw_d0[346]
  PIN tw_d0[347]
    DIRECTION INPUT ;
    USE SIGNAL ;
    PORT
      LAYER M5 ;
        RECT  45.648 0 45.672 0.084 ;
    END
  END tw_d0[347]
  PIN tw_d0[348]
    DIRECTION INPUT ;
    USE SIGNAL ;
    PORT
      LAYER M5 ;
        RECT  45.744 0 45.768 0.084 ;
    END
  END tw_d0[348]
  PIN tw_d0[349]
    DIRECTION INPUT ;
    USE SIGNAL ;
    PORT
      LAYER M5 ;
        RECT  45.84 0 45.864 0.084 ;
    END
  END tw_d0[349]
  PIN tw_d0[34]
    DIRECTION INPUT ;
    USE SIGNAL ;
    PORT
      LAYER M5 ;
        RECT  30.192 0 30.216 0.084 ;
    END
  END tw_d0[34]
  PIN tw_d0[350]
    DIRECTION INPUT ;
    USE SIGNAL ;
    PORT
      LAYER M5 ;
        RECT  45.936 0 45.96 0.084 ;
    END
  END tw_d0[350]
  PIN tw_d0[351]
    DIRECTION INPUT ;
    USE SIGNAL ;
    PORT
      LAYER M5 ;
        RECT  46.032 0 46.056 0.084 ;
    END
  END tw_d0[351]
  PIN tw_d0[352]
    DIRECTION INPUT ;
    USE SIGNAL ;
    PORT
      LAYER M5 ;
        RECT  46.128 0 46.152 0.084 ;
    END
  END tw_d0[352]
  PIN tw_d0[353]
    DIRECTION INPUT ;
    USE SIGNAL ;
    PORT
      LAYER M5 ;
        RECT  46.224 0 46.248 0.084 ;
    END
  END tw_d0[353]
  PIN tw_d0[354]
    DIRECTION INPUT ;
    USE SIGNAL ;
    PORT
      LAYER M5 ;
        RECT  46.32 0 46.344 0.084 ;
    END
  END tw_d0[354]
  PIN tw_d0[355]
    DIRECTION INPUT ;
    USE SIGNAL ;
    PORT
      LAYER M5 ;
        RECT  46.416 0 46.44 0.084 ;
    END
  END tw_d0[355]
  PIN tw_d0[356]
    DIRECTION INPUT ;
    USE SIGNAL ;
    PORT
      LAYER M5 ;
        RECT  46.512 0 46.536 0.084 ;
    END
  END tw_d0[356]
  PIN tw_d0[357]
    DIRECTION INPUT ;
    USE SIGNAL ;
    PORT
      LAYER M5 ;
        RECT  46.608 0 46.632 0.084 ;
    END
  END tw_d0[357]
  PIN tw_d0[358]
    DIRECTION INPUT ;
    USE SIGNAL ;
    PORT
      LAYER M5 ;
        RECT  46.704 0 46.728 0.084 ;
    END
  END tw_d0[358]
  PIN tw_d0[359]
    DIRECTION INPUT ;
    USE SIGNAL ;
    PORT
      LAYER M5 ;
        RECT  46.8 0 46.824 0.084 ;
    END
  END tw_d0[359]
  PIN tw_d0[35]
    DIRECTION INPUT ;
    USE SIGNAL ;
    PORT
      LAYER M5 ;
        RECT  30.288 0 30.312 0.084 ;
    END
  END tw_d0[35]
  PIN tw_d0[360]
    DIRECTION INPUT ;
    USE SIGNAL ;
    PORT
      LAYER M5 ;
        RECT  46.896 0 46.92 0.084 ;
    END
  END tw_d0[360]
  PIN tw_d0[361]
    DIRECTION INPUT ;
    USE SIGNAL ;
    PORT
      LAYER M5 ;
        RECT  46.992 0 47.016 0.084 ;
    END
  END tw_d0[361]
  PIN tw_d0[362]
    DIRECTION INPUT ;
    USE SIGNAL ;
    PORT
      LAYER M5 ;
        RECT  47.088 0 47.112 0.084 ;
    END
  END tw_d0[362]
  PIN tw_d0[363]
    DIRECTION INPUT ;
    USE SIGNAL ;
    PORT
      LAYER M5 ;
        RECT  47.184 0 47.208 0.084 ;
    END
  END tw_d0[363]
  PIN tw_d0[364]
    DIRECTION INPUT ;
    USE SIGNAL ;
    PORT
      LAYER M5 ;
        RECT  47.28 0 47.304 0.084 ;
    END
  END tw_d0[364]
  PIN tw_d0[365]
    DIRECTION INPUT ;
    USE SIGNAL ;
    PORT
      LAYER M5 ;
        RECT  47.376 0 47.4 0.084 ;
    END
  END tw_d0[365]
  PIN tw_d0[366]
    DIRECTION INPUT ;
    USE SIGNAL ;
    PORT
      LAYER M5 ;
        RECT  47.472 0 47.496 0.084 ;
    END
  END tw_d0[366]
  PIN tw_d0[367]
    DIRECTION INPUT ;
    USE SIGNAL ;
    PORT
      LAYER M5 ;
        RECT  47.568 0 47.592 0.084 ;
    END
  END tw_d0[367]
  PIN tw_d0[368]
    DIRECTION INPUT ;
    USE SIGNAL ;
    PORT
      LAYER M5 ;
        RECT  47.664 0 47.688 0.084 ;
    END
  END tw_d0[368]
  PIN tw_d0[369]
    DIRECTION INPUT ;
    USE SIGNAL ;
    PORT
      LAYER M5 ;
        RECT  47.76 0 47.784 0.084 ;
    END
  END tw_d0[369]
  PIN tw_d0[36]
    DIRECTION INPUT ;
    USE SIGNAL ;
    PORT
      LAYER M5 ;
        RECT  30.384 0 30.408 0.084 ;
    END
  END tw_d0[36]
  PIN tw_d0[370]
    DIRECTION INPUT ;
    USE SIGNAL ;
    PORT
      LAYER M5 ;
        RECT  47.856 0 47.88 0.084 ;
    END
  END tw_d0[370]
  PIN tw_d0[371]
    DIRECTION INPUT ;
    USE SIGNAL ;
    PORT
      LAYER M5 ;
        RECT  47.952 0 47.976 0.084 ;
    END
  END tw_d0[371]
  PIN tw_d0[372]
    DIRECTION INPUT ;
    USE SIGNAL ;
    PORT
      LAYER M5 ;
        RECT  48.048 0 48.072 0.084 ;
    END
  END tw_d0[372]
  PIN tw_d0[373]
    DIRECTION INPUT ;
    USE SIGNAL ;
    PORT
      LAYER M5 ;
        RECT  48.144 0 48.168 0.084 ;
    END
  END tw_d0[373]
  PIN tw_d0[374]
    DIRECTION INPUT ;
    USE SIGNAL ;
    PORT
      LAYER M5 ;
        RECT  48.24 0 48.264 0.084 ;
    END
  END tw_d0[374]
  PIN tw_d0[375]
    DIRECTION INPUT ;
    USE SIGNAL ;
    PORT
      LAYER M5 ;
        RECT  51.408 0 51.432 0.084 ;
    END
  END tw_d0[375]
  PIN tw_d0[376]
    DIRECTION INPUT ;
    USE SIGNAL ;
    PORT
      LAYER M5 ;
        RECT  51.504 0 51.528 0.084 ;
    END
  END tw_d0[376]
  PIN tw_d0[377]
    DIRECTION INPUT ;
    USE SIGNAL ;
    PORT
      LAYER M5 ;
        RECT  51.6 0 51.624 0.084 ;
    END
  END tw_d0[377]
  PIN tw_d0[378]
    DIRECTION INPUT ;
    USE SIGNAL ;
    PORT
      LAYER M5 ;
        RECT  51.696 0 51.72 0.084 ;
    END
  END tw_d0[378]
  PIN tw_d0[379]
    DIRECTION INPUT ;
    USE SIGNAL ;
    PORT
      LAYER M5 ;
        RECT  51.792 0 51.816 0.084 ;
    END
  END tw_d0[379]
  PIN tw_d0[37]
    DIRECTION INPUT ;
    USE SIGNAL ;
    PORT
      LAYER M5 ;
        RECT  30.48 0 30.504 0.084 ;
    END
  END tw_d0[37]
  PIN tw_d0[380]
    DIRECTION INPUT ;
    USE SIGNAL ;
    PORT
      LAYER M5 ;
        RECT  51.888 0 51.912 0.084 ;
    END
  END tw_d0[380]
  PIN tw_d0[381]
    DIRECTION INPUT ;
    USE SIGNAL ;
    PORT
      LAYER M5 ;
        RECT  51.984 0 52.008 0.084 ;
    END
  END tw_d0[381]
  PIN tw_d0[382]
    DIRECTION INPUT ;
    USE SIGNAL ;
    PORT
      LAYER M5 ;
        RECT  52.08 0 52.104 0.084 ;
    END
  END tw_d0[382]
  PIN tw_d0[383]
    DIRECTION INPUT ;
    USE SIGNAL ;
    PORT
      LAYER M5 ;
        RECT  52.176 0 52.2 0.084 ;
    END
  END tw_d0[383]
  PIN tw_d0[384]
    DIRECTION INPUT ;
    USE SIGNAL ;
    PORT
      LAYER M5 ;
        RECT  52.272 0 52.296 0.084 ;
    END
  END tw_d0[384]
  PIN tw_d0[385]
    DIRECTION INPUT ;
    USE SIGNAL ;
    PORT
      LAYER M5 ;
        RECT  52.368 0 52.392 0.084 ;
    END
  END tw_d0[385]
  PIN tw_d0[386]
    DIRECTION INPUT ;
    USE SIGNAL ;
    PORT
      LAYER M5 ;
        RECT  52.464 0 52.488 0.084 ;
    END
  END tw_d0[386]
  PIN tw_d0[387]
    DIRECTION INPUT ;
    USE SIGNAL ;
    PORT
      LAYER M5 ;
        RECT  52.56 0 52.584 0.084 ;
    END
  END tw_d0[387]
  PIN tw_d0[388]
    DIRECTION INPUT ;
    USE SIGNAL ;
    PORT
      LAYER M5 ;
        RECT  52.656 0 52.68 0.084 ;
    END
  END tw_d0[388]
  PIN tw_d0[389]
    DIRECTION INPUT ;
    USE SIGNAL ;
    PORT
      LAYER M5 ;
        RECT  52.752 0 52.776 0.084 ;
    END
  END tw_d0[389]
  PIN tw_d0[38]
    DIRECTION INPUT ;
    USE SIGNAL ;
    PORT
      LAYER M5 ;
        RECT  30.576 0 30.6 0.084 ;
    END
  END tw_d0[38]
  PIN tw_d0[390]
    DIRECTION INPUT ;
    USE SIGNAL ;
    PORT
      LAYER M5 ;
        RECT  52.848 0 52.872 0.084 ;
    END
  END tw_d0[390]
  PIN tw_d0[391]
    DIRECTION INPUT ;
    USE SIGNAL ;
    PORT
      LAYER M5 ;
        RECT  52.944 0 52.968 0.084 ;
    END
  END tw_d0[391]
  PIN tw_d0[392]
    DIRECTION INPUT ;
    USE SIGNAL ;
    PORT
      LAYER M5 ;
        RECT  53.04 0 53.064 0.084 ;
    END
  END tw_d0[392]
  PIN tw_d0[393]
    DIRECTION INPUT ;
    USE SIGNAL ;
    PORT
      LAYER M5 ;
        RECT  53.136 0 53.16 0.084 ;
    END
  END tw_d0[393]
  PIN tw_d0[394]
    DIRECTION INPUT ;
    USE SIGNAL ;
    PORT
      LAYER M5 ;
        RECT  53.232 0 53.256 0.084 ;
    END
  END tw_d0[394]
  PIN tw_d0[395]
    DIRECTION INPUT ;
    USE SIGNAL ;
    PORT
      LAYER M5 ;
        RECT  53.328 0 53.352 0.084 ;
    END
  END tw_d0[395]
  PIN tw_d0[396]
    DIRECTION INPUT ;
    USE SIGNAL ;
    PORT
      LAYER M5 ;
        RECT  53.424 0 53.448 0.084 ;
    END
  END tw_d0[396]
  PIN tw_d0[397]
    DIRECTION INPUT ;
    USE SIGNAL ;
    PORT
      LAYER M5 ;
        RECT  53.52 0 53.544 0.084 ;
    END
  END tw_d0[397]
  PIN tw_d0[398]
    DIRECTION INPUT ;
    USE SIGNAL ;
    PORT
      LAYER M5 ;
        RECT  53.616 0 53.64 0.084 ;
    END
  END tw_d0[398]
  PIN tw_d0[399]
    DIRECTION INPUT ;
    USE SIGNAL ;
    PORT
      LAYER M5 ;
        RECT  53.712 0 53.736 0.084 ;
    END
  END tw_d0[399]
  PIN tw_d0[39]
    DIRECTION INPUT ;
    USE SIGNAL ;
    PORT
      LAYER M5 ;
        RECT  30.672 0 30.696 0.084 ;
    END
  END tw_d0[39]
  PIN tw_d0[3]
    DIRECTION INPUT ;
    USE SIGNAL ;
    PORT
      LAYER M5 ;
        RECT  36.432 0 36.456 0.084 ;
    END
  END tw_d0[3]
  PIN tw_d0[400]
    DIRECTION INPUT ;
    USE SIGNAL ;
    PORT
      LAYER M5 ;
        RECT  53.808 0 53.832 0.084 ;
    END
  END tw_d0[400]
  PIN tw_d0[401]
    DIRECTION INPUT ;
    USE SIGNAL ;
    PORT
      LAYER M5 ;
        RECT  53.904 0 53.928 0.084 ;
    END
  END tw_d0[401]
  PIN tw_d0[402]
    DIRECTION INPUT ;
    USE SIGNAL ;
    PORT
      LAYER M5 ;
        RECT  54 0 54.024 0.084 ;
    END
  END tw_d0[402]
  PIN tw_d0[403]
    DIRECTION INPUT ;
    USE SIGNAL ;
    PORT
      LAYER M5 ;
        RECT  54.096 0 54.12 0.084 ;
    END
  END tw_d0[403]
  PIN tw_d0[404]
    DIRECTION INPUT ;
    USE SIGNAL ;
    PORT
      LAYER M5 ;
        RECT  54.192 0 54.216 0.084 ;
    END
  END tw_d0[404]
  PIN tw_d0[405]
    DIRECTION INPUT ;
    USE SIGNAL ;
    PORT
      LAYER M5 ;
        RECT  54.288 0 54.312 0.084 ;
    END
  END tw_d0[405]
  PIN tw_d0[406]
    DIRECTION INPUT ;
    USE SIGNAL ;
    PORT
      LAYER M5 ;
        RECT  54.384 0 54.408 0.084 ;
    END
  END tw_d0[406]
  PIN tw_d0[407]
    DIRECTION INPUT ;
    USE SIGNAL ;
    PORT
      LAYER M5 ;
        RECT  218.064 0 218.088 0.084 ;
    END
  END tw_d0[407]
  PIN tw_d0[408]
    DIRECTION INPUT ;
    USE SIGNAL ;
    PORT
      LAYER M5 ;
        RECT  218.16 0 218.184 0.084 ;
    END
  END tw_d0[408]
  PIN tw_d0[409]
    DIRECTION INPUT ;
    USE SIGNAL ;
    PORT
      LAYER M5 ;
        RECT  218.256 0 218.28 0.084 ;
    END
  END tw_d0[409]
  PIN tw_d0[40]
    DIRECTION INPUT ;
    USE SIGNAL ;
    PORT
      LAYER M5 ;
        RECT  30.768 0 30.792 0.084 ;
    END
  END tw_d0[40]
  PIN tw_d0[410]
    DIRECTION INPUT ;
    USE SIGNAL ;
    PORT
      LAYER M5 ;
        RECT  218.352 0 218.376 0.084 ;
    END
  END tw_d0[410]
  PIN tw_d0[411]
    DIRECTION INPUT ;
    USE SIGNAL ;
    PORT
      LAYER M5 ;
        RECT  218.448 0 218.472 0.084 ;
    END
  END tw_d0[411]
  PIN tw_d0[412]
    DIRECTION INPUT ;
    USE SIGNAL ;
    PORT
      LAYER M5 ;
        RECT  218.544 0 218.568 0.084 ;
    END
  END tw_d0[412]
  PIN tw_d0[413]
    DIRECTION INPUT ;
    USE SIGNAL ;
    PORT
      LAYER M5 ;
        RECT  218.64 0 218.664 0.084 ;
    END
  END tw_d0[413]
  PIN tw_d0[414]
    DIRECTION INPUT ;
    USE SIGNAL ;
    PORT
      LAYER M5 ;
        RECT  218.736 0 218.76 0.084 ;
    END
  END tw_d0[414]
  PIN tw_d0[415]
    DIRECTION INPUT ;
    USE SIGNAL ;
    PORT
      LAYER M5 ;
        RECT  218.832 0 218.856 0.084 ;
    END
  END tw_d0[415]
  PIN tw_d0[416]
    DIRECTION INPUT ;
    USE SIGNAL ;
    PORT
      LAYER M5 ;
        RECT  218.928 0 218.952 0.084 ;
    END
  END tw_d0[416]
  PIN tw_d0[417]
    DIRECTION INPUT ;
    USE SIGNAL ;
    PORT
      LAYER M5 ;
        RECT  219.024 0 219.048 0.084 ;
    END
  END tw_d0[417]
  PIN tw_d0[418]
    DIRECTION INPUT ;
    USE SIGNAL ;
    PORT
      LAYER M5 ;
        RECT  219.12 0 219.144 0.084 ;
    END
  END tw_d0[418]
  PIN tw_d0[419]
    DIRECTION INPUT ;
    USE SIGNAL ;
    PORT
      LAYER M5 ;
        RECT  219.216 0 219.24 0.084 ;
    END
  END tw_d0[419]
  PIN tw_d0[41]
    DIRECTION INPUT ;
    USE SIGNAL ;
    PORT
      LAYER M5 ;
        RECT  30.864 0 30.888 0.084 ;
    END
  END tw_d0[41]
  PIN tw_d0[420]
    DIRECTION INPUT ;
    USE SIGNAL ;
    PORT
      LAYER M5 ;
        RECT  219.312 0 219.336 0.084 ;
    END
  END tw_d0[420]
  PIN tw_d0[421]
    DIRECTION INPUT ;
    USE SIGNAL ;
    PORT
      LAYER M5 ;
        RECT  219.408 0 219.432 0.084 ;
    END
  END tw_d0[421]
  PIN tw_d0[422]
    DIRECTION INPUT ;
    USE SIGNAL ;
    PORT
      LAYER M5 ;
        RECT  219.504 0 219.528 0.084 ;
    END
  END tw_d0[422]
  PIN tw_d0[423]
    DIRECTION INPUT ;
    USE SIGNAL ;
    PORT
      LAYER M5 ;
        RECT  219.6 0 219.624 0.084 ;
    END
  END tw_d0[423]
  PIN tw_d0[424]
    DIRECTION INPUT ;
    USE SIGNAL ;
    PORT
      LAYER M5 ;
        RECT  219.696 0 219.72 0.084 ;
    END
  END tw_d0[424]
  PIN tw_d0[425]
    DIRECTION INPUT ;
    USE SIGNAL ;
    PORT
      LAYER M5 ;
        RECT  219.792 0 219.816 0.084 ;
    END
  END tw_d0[425]
  PIN tw_d0[426]
    DIRECTION INPUT ;
    USE SIGNAL ;
    PORT
      LAYER M5 ;
        RECT  219.888 0 219.912 0.084 ;
    END
  END tw_d0[426]
  PIN tw_d0[427]
    DIRECTION INPUT ;
    USE SIGNAL ;
    PORT
      LAYER M5 ;
        RECT  219.984 0 220.008 0.084 ;
    END
  END tw_d0[427]
  PIN tw_d0[428]
    DIRECTION INPUT ;
    USE SIGNAL ;
    PORT
      LAYER M5 ;
        RECT  220.08 0 220.104 0.084 ;
    END
  END tw_d0[428]
  PIN tw_d0[429]
    DIRECTION INPUT ;
    USE SIGNAL ;
    PORT
      LAYER M5 ;
        RECT  220.176 0 220.2 0.084 ;
    END
  END tw_d0[429]
  PIN tw_d0[42]
    DIRECTION INPUT ;
    USE SIGNAL ;
    PORT
      LAYER M5 ;
        RECT  30.96 0 30.984 0.084 ;
    END
  END tw_d0[42]
  PIN tw_d0[430]
    DIRECTION INPUT ;
    USE SIGNAL ;
    PORT
      LAYER M5 ;
        RECT  220.272 0 220.296 0.084 ;
    END
  END tw_d0[430]
  PIN tw_d0[431]
    DIRECTION INPUT ;
    USE SIGNAL ;
    PORT
      LAYER M5 ;
        RECT  220.368 0 220.392 0.084 ;
    END
  END tw_d0[431]
  PIN tw_d0[432]
    DIRECTION INPUT ;
    USE SIGNAL ;
    PORT
      LAYER M5 ;
        RECT  220.464 0 220.488 0.084 ;
    END
  END tw_d0[432]
  PIN tw_d0[433]
    DIRECTION INPUT ;
    USE SIGNAL ;
    PORT
      LAYER M5 ;
        RECT  220.56 0 220.584 0.084 ;
    END
  END tw_d0[433]
  PIN tw_d0[434]
    DIRECTION INPUT ;
    USE SIGNAL ;
    PORT
      LAYER M5 ;
        RECT  220.656 0 220.68 0.084 ;
    END
  END tw_d0[434]
  PIN tw_d0[435]
    DIRECTION INPUT ;
    USE SIGNAL ;
    PORT
      LAYER M5 ;
        RECT  220.752 0 220.776 0.084 ;
    END
  END tw_d0[435]
  PIN tw_d0[436]
    DIRECTION INPUT ;
    USE SIGNAL ;
    PORT
      LAYER M5 ;
        RECT  220.848 0 220.872 0.084 ;
    END
  END tw_d0[436]
  PIN tw_d0[437]
    DIRECTION INPUT ;
    USE SIGNAL ;
    PORT
      LAYER M5 ;
        RECT  220.944 0 220.968 0.084 ;
    END
  END tw_d0[437]
  PIN tw_d0[438]
    DIRECTION INPUT ;
    USE SIGNAL ;
    PORT
      LAYER M5 ;
        RECT  221.04 0 221.064 0.084 ;
    END
  END tw_d0[438]
  PIN tw_d0[439]
    DIRECTION INPUT ;
    USE SIGNAL ;
    PORT
      LAYER M5 ;
        RECT  198.864 0 198.888 0.084 ;
    END
  END tw_d0[439]
  PIN tw_d0[43]
    DIRECTION INPUT ;
    USE SIGNAL ;
    PORT
      LAYER M5 ;
        RECT  31.056 0 31.08 0.084 ;
    END
  END tw_d0[43]
  PIN tw_d0[440]
    DIRECTION INPUT ;
    USE SIGNAL ;
    PORT
      LAYER M5 ;
        RECT  198.96 0 198.984 0.084 ;
    END
  END tw_d0[440]
  PIN tw_d0[441]
    DIRECTION INPUT ;
    USE SIGNAL ;
    PORT
      LAYER M5 ;
        RECT  199.056 0 199.08 0.084 ;
    END
  END tw_d0[441]
  PIN tw_d0[442]
    DIRECTION INPUT ;
    USE SIGNAL ;
    PORT
      LAYER M5 ;
        RECT  199.152 0 199.176 0.084 ;
    END
  END tw_d0[442]
  PIN tw_d0[443]
    DIRECTION INPUT ;
    USE SIGNAL ;
    PORT
      LAYER M5 ;
        RECT  199.248 0 199.272 0.084 ;
    END
  END tw_d0[443]
  PIN tw_d0[444]
    DIRECTION INPUT ;
    USE SIGNAL ;
    PORT
      LAYER M5 ;
        RECT  199.344 0 199.368 0.084 ;
    END
  END tw_d0[444]
  PIN tw_d0[445]
    DIRECTION INPUT ;
    USE SIGNAL ;
    PORT
      LAYER M5 ;
        RECT  199.44 0 199.464 0.084 ;
    END
  END tw_d0[445]
  PIN tw_d0[446]
    DIRECTION INPUT ;
    USE SIGNAL ;
    PORT
      LAYER M5 ;
        RECT  199.536 0 199.56 0.084 ;
    END
  END tw_d0[446]
  PIN tw_d0[447]
    DIRECTION INPUT ;
    USE SIGNAL ;
    PORT
      LAYER M5 ;
        RECT  199.632 0 199.656 0.084 ;
    END
  END tw_d0[447]
  PIN tw_d0[448]
    DIRECTION INPUT ;
    USE SIGNAL ;
    PORT
      LAYER M5 ;
        RECT  199.728 0 199.752 0.084 ;
    END
  END tw_d0[448]
  PIN tw_d0[449]
    DIRECTION INPUT ;
    USE SIGNAL ;
    PORT
      LAYER M5 ;
        RECT  199.824 0 199.848 0.084 ;
    END
  END tw_d0[449]
  PIN tw_d0[44]
    DIRECTION INPUT ;
    USE SIGNAL ;
    PORT
      LAYER M5 ;
        RECT  31.152 0 31.176 0.084 ;
    END
  END tw_d0[44]
  PIN tw_d0[450]
    DIRECTION INPUT ;
    USE SIGNAL ;
    PORT
      LAYER M5 ;
        RECT  199.92 0 199.944 0.084 ;
    END
  END tw_d0[450]
  PIN tw_d0[451]
    DIRECTION INPUT ;
    USE SIGNAL ;
    PORT
      LAYER M5 ;
        RECT  200.016 0 200.04 0.084 ;
    END
  END tw_d0[451]
  PIN tw_d0[452]
    DIRECTION INPUT ;
    USE SIGNAL ;
    PORT
      LAYER M5 ;
        RECT  200.112 0 200.136 0.084 ;
    END
  END tw_d0[452]
  PIN tw_d0[453]
    DIRECTION INPUT ;
    USE SIGNAL ;
    PORT
      LAYER M5 ;
        RECT  200.208 0 200.232 0.084 ;
    END
  END tw_d0[453]
  PIN tw_d0[454]
    DIRECTION INPUT ;
    USE SIGNAL ;
    PORT
      LAYER M5 ;
        RECT  200.304 0 200.328 0.084 ;
    END
  END tw_d0[454]
  PIN tw_d0[455]
    DIRECTION INPUT ;
    USE SIGNAL ;
    PORT
      LAYER M5 ;
        RECT  200.4 0 200.424 0.084 ;
    END
  END tw_d0[455]
  PIN tw_d0[456]
    DIRECTION INPUT ;
    USE SIGNAL ;
    PORT
      LAYER M5 ;
        RECT  200.496 0 200.52 0.084 ;
    END
  END tw_d0[456]
  PIN tw_d0[45]
    DIRECTION INPUT ;
    USE SIGNAL ;
    PORT
      LAYER M5 ;
        RECT  31.248 0 31.272 0.084 ;
    END
  END tw_d0[45]
  PIN tw_d0[46]
    DIRECTION INPUT ;
    USE SIGNAL ;
    PORT
      LAYER M5 ;
        RECT  31.344 0 31.368 0.084 ;
    END
  END tw_d0[46]
  PIN tw_d0[47]
    DIRECTION INPUT ;
    USE SIGNAL ;
    PORT
      LAYER M5 ;
        RECT  31.44 0 31.464 0.084 ;
    END
  END tw_d0[47]
  PIN tw_d0[48]
    DIRECTION INPUT ;
    USE SIGNAL ;
    PORT
      LAYER M5 ;
        RECT  31.536 0 31.56 0.084 ;
    END
  END tw_d0[48]
  PIN tw_d0[49]
    DIRECTION INPUT ;
    USE SIGNAL ;
    PORT
      LAYER M5 ;
        RECT  31.632 0 31.656 0.084 ;
    END
  END tw_d0[49]
  PIN tw_d0[4]
    DIRECTION INPUT ;
    USE SIGNAL ;
    PORT
      LAYER M5 ;
        RECT  36.528 0 36.552 0.084 ;
    END
  END tw_d0[4]
  PIN tw_d0[50]
    DIRECTION INPUT ;
    USE SIGNAL ;
    PORT
      LAYER M5 ;
        RECT  31.728 0 31.752 0.084 ;
    END
  END tw_d0[50]
  PIN tw_d0[51]
    DIRECTION INPUT ;
    USE SIGNAL ;
    PORT
      LAYER M5 ;
        RECT  31.824 0 31.848 0.084 ;
    END
  END tw_d0[51]
  PIN tw_d0[52]
    DIRECTION INPUT ;
    USE SIGNAL ;
    PORT
      LAYER M5 ;
        RECT  31.92 0 31.944 0.084 ;
    END
  END tw_d0[52]
  PIN tw_d0[53]
    DIRECTION INPUT ;
    USE SIGNAL ;
    PORT
      LAYER M5 ;
        RECT  32.016 0 32.04 0.084 ;
    END
  END tw_d0[53]
  PIN tw_d0[54]
    DIRECTION INPUT ;
    USE SIGNAL ;
    PORT
      LAYER M5 ;
        RECT  32.112 0 32.136 0.084 ;
    END
  END tw_d0[54]
  PIN tw_d0[55]
    DIRECTION INPUT ;
    USE SIGNAL ;
    PORT
      LAYER M5 ;
        RECT  22.992 0 23.016 0.084 ;
    END
  END tw_d0[55]
  PIN tw_d0[56]
    DIRECTION INPUT ;
    USE SIGNAL ;
    PORT
      LAYER M5 ;
        RECT  23.088 0 23.112 0.084 ;
    END
  END tw_d0[56]
  PIN tw_d0[57]
    DIRECTION INPUT ;
    USE SIGNAL ;
    PORT
      LAYER M5 ;
        RECT  23.184 0 23.208 0.084 ;
    END
  END tw_d0[57]
  PIN tw_d0[58]
    DIRECTION INPUT ;
    USE SIGNAL ;
    PORT
      LAYER M5 ;
        RECT  23.28 0 23.304 0.084 ;
    END
  END tw_d0[58]
  PIN tw_d0[59]
    DIRECTION INPUT ;
    USE SIGNAL ;
    PORT
      LAYER M5 ;
        RECT  23.376 0 23.4 0.084 ;
    END
  END tw_d0[59]
  PIN tw_d0[5]
    DIRECTION INPUT ;
    USE SIGNAL ;
    PORT
      LAYER M5 ;
        RECT  36.624 0 36.648 0.084 ;
    END
  END tw_d0[5]
  PIN tw_d0[60]
    DIRECTION INPUT ;
    USE SIGNAL ;
    PORT
      LAYER M5 ;
        RECT  23.472 0 23.496 0.084 ;
    END
  END tw_d0[60]
  PIN tw_d0[61]
    DIRECTION INPUT ;
    USE SIGNAL ;
    PORT
      LAYER M5 ;
        RECT  23.568 0 23.592 0.084 ;
    END
  END tw_d0[61]
  PIN tw_d0[62]
    DIRECTION INPUT ;
    USE SIGNAL ;
    PORT
      LAYER M5 ;
        RECT  23.664 0 23.688 0.084 ;
    END
  END tw_d0[62]
  PIN tw_d0[63]
    DIRECTION INPUT ;
    USE SIGNAL ;
    PORT
      LAYER M5 ;
        RECT  23.76 0 23.784 0.084 ;
    END
  END tw_d0[63]
  PIN tw_d0[64]
    DIRECTION INPUT ;
    USE SIGNAL ;
    PORT
      LAYER M5 ;
        RECT  23.856 0 23.88 0.084 ;
    END
  END tw_d0[64]
  PIN tw_d0[65]
    DIRECTION INPUT ;
    USE SIGNAL ;
    PORT
      LAYER M5 ;
        RECT  23.952 0 23.976 0.084 ;
    END
  END tw_d0[65]
  PIN tw_d0[66]
    DIRECTION INPUT ;
    USE SIGNAL ;
    PORT
      LAYER M5 ;
        RECT  24.048 0 24.072 0.084 ;
    END
  END tw_d0[66]
  PIN tw_d0[67]
    DIRECTION INPUT ;
    USE SIGNAL ;
    PORT
      LAYER M5 ;
        RECT  24.144 0 24.168 0.084 ;
    END
  END tw_d0[67]
  PIN tw_d0[68]
    DIRECTION INPUT ;
    USE SIGNAL ;
    PORT
      LAYER M5 ;
        RECT  24.24 0 24.264 0.084 ;
    END
  END tw_d0[68]
  PIN tw_d0[69]
    DIRECTION INPUT ;
    USE SIGNAL ;
    PORT
      LAYER M5 ;
        RECT  24.336 0 24.36 0.084 ;
    END
  END tw_d0[69]
  PIN tw_d0[6]
    DIRECTION INPUT ;
    USE SIGNAL ;
    PORT
      LAYER M5 ;
        RECT  36.72 0 36.744 0.084 ;
    END
  END tw_d0[6]
  PIN tw_d0[70]
    DIRECTION INPUT ;
    USE SIGNAL ;
    PORT
      LAYER M5 ;
        RECT  24.432 0 24.456 0.084 ;
    END
  END tw_d0[70]
  PIN tw_d0[71]
    DIRECTION INPUT ;
    USE SIGNAL ;
    PORT
      LAYER M5 ;
        RECT  24.528 0 24.552 0.084 ;
    END
  END tw_d0[71]
  PIN tw_d0[72]
    DIRECTION INPUT ;
    USE SIGNAL ;
    PORT
      LAYER M5 ;
        RECT  24.624 0 24.648 0.084 ;
    END
  END tw_d0[72]
  PIN tw_d0[73]
    DIRECTION INPUT ;
    USE SIGNAL ;
    PORT
      LAYER M5 ;
        RECT  24.72 0 24.744 0.084 ;
    END
  END tw_d0[73]
  PIN tw_d0[74]
    DIRECTION INPUT ;
    USE SIGNAL ;
    PORT
      LAYER M5 ;
        RECT  24.816 0 24.84 0.084 ;
    END
  END tw_d0[74]
  PIN tw_d0[75]
    DIRECTION INPUT ;
    USE SIGNAL ;
    PORT
      LAYER M5 ;
        RECT  24.912 0 24.936 0.084 ;
    END
  END tw_d0[75]
  PIN tw_d0[76]
    DIRECTION INPUT ;
    USE SIGNAL ;
    PORT
      LAYER M5 ;
        RECT  25.008 0 25.032 0.084 ;
    END
  END tw_d0[76]
  PIN tw_d0[77]
    DIRECTION INPUT ;
    USE SIGNAL ;
    PORT
      LAYER M5 ;
        RECT  25.104 0 25.128 0.084 ;
    END
  END tw_d0[77]
  PIN tw_d0[78]
    DIRECTION INPUT ;
    USE SIGNAL ;
    PORT
      LAYER M5 ;
        RECT  25.2 0 25.224 0.084 ;
    END
  END tw_d0[78]
  PIN tw_d0[79]
    DIRECTION INPUT ;
    USE SIGNAL ;
    PORT
      LAYER M5 ;
        RECT  25.296 0 25.32 0.084 ;
    END
  END tw_d0[79]
  PIN tw_d0[7]
    DIRECTION INPUT ;
    USE SIGNAL ;
    PORT
      LAYER M5 ;
        RECT  36.816 0 36.84 0.084 ;
    END
  END tw_d0[7]
  PIN tw_d0[80]
    DIRECTION INPUT ;
    USE SIGNAL ;
    PORT
      LAYER M5 ;
        RECT  25.392 0 25.416 0.084 ;
    END
  END tw_d0[80]
  PIN tw_d0[81]
    DIRECTION INPUT ;
    USE SIGNAL ;
    PORT
      LAYER M5 ;
        RECT  25.488 0 25.512 0.084 ;
    END
  END tw_d0[81]
  PIN tw_d0[82]
    DIRECTION INPUT ;
    USE SIGNAL ;
    PORT
      LAYER M5 ;
        RECT  25.584 0 25.608 0.084 ;
    END
  END tw_d0[82]
  PIN tw_d0[83]
    DIRECTION INPUT ;
    USE SIGNAL ;
    PORT
      LAYER M5 ;
        RECT  25.68 0 25.704 0.084 ;
    END
  END tw_d0[83]
  PIN tw_d0[84]
    DIRECTION INPUT ;
    USE SIGNAL ;
    PORT
      LAYER M5 ;
        RECT  25.776 0 25.8 0.084 ;
    END
  END tw_d0[84]
  PIN tw_d0[85]
    DIRECTION INPUT ;
    USE SIGNAL ;
    PORT
      LAYER M5 ;
        RECT  25.872 0 25.896 0.084 ;
    END
  END tw_d0[85]
  PIN tw_d0[86]
    DIRECTION INPUT ;
    USE SIGNAL ;
    PORT
      LAYER M5 ;
        RECT  25.968 0 25.992 0.084 ;
    END
  END tw_d0[86]
  PIN tw_d0[87]
    DIRECTION INPUT ;
    USE SIGNAL ;
    PORT
      LAYER M5 ;
        RECT  32.208 0 32.232 0.084 ;
    END
  END tw_d0[87]
  PIN tw_d0[88]
    DIRECTION INPUT ;
    USE SIGNAL ;
    PORT
      LAYER M5 ;
        RECT  32.304 0 32.328 0.084 ;
    END
  END tw_d0[88]
  PIN tw_d0[89]
    DIRECTION INPUT ;
    USE SIGNAL ;
    PORT
      LAYER M5 ;
        RECT  32.4 0 32.424 0.084 ;
    END
  END tw_d0[89]
  PIN tw_d0[8]
    DIRECTION INPUT ;
    USE SIGNAL ;
    PORT
      LAYER M5 ;
        RECT  36.912 0 36.936 0.084 ;
    END
  END tw_d0[8]
  PIN tw_d0[90]
    DIRECTION INPUT ;
    USE SIGNAL ;
    PORT
      LAYER M5 ;
        RECT  32.496 0 32.52 0.084 ;
    END
  END tw_d0[90]
  PIN tw_d0[91]
    DIRECTION INPUT ;
    USE SIGNAL ;
    PORT
      LAYER M5 ;
        RECT  32.592 0 32.616 0.084 ;
    END
  END tw_d0[91]
  PIN tw_d0[92]
    DIRECTION INPUT ;
    USE SIGNAL ;
    PORT
      LAYER M5 ;
        RECT  32.688 0 32.712 0.084 ;
    END
  END tw_d0[92]
  PIN tw_d0[93]
    DIRECTION INPUT ;
    USE SIGNAL ;
    PORT
      LAYER M5 ;
        RECT  32.784 0 32.808 0.084 ;
    END
  END tw_d0[93]
  PIN tw_d0[94]
    DIRECTION INPUT ;
    USE SIGNAL ;
    PORT
      LAYER M5 ;
        RECT  32.88 0 32.904 0.084 ;
    END
  END tw_d0[94]
  PIN tw_d0[95]
    DIRECTION INPUT ;
    USE SIGNAL ;
    PORT
      LAYER M5 ;
        RECT  32.976 0 33 0.084 ;
    END
  END tw_d0[95]
  PIN tw_d0[96]
    DIRECTION INPUT ;
    USE SIGNAL ;
    PORT
      LAYER M5 ;
        RECT  33.072 0 33.096 0.084 ;
    END
  END tw_d0[96]
  PIN tw_d0[97]
    DIRECTION INPUT ;
    USE SIGNAL ;
    PORT
      LAYER M5 ;
        RECT  33.168 0 33.192 0.084 ;
    END
  END tw_d0[97]
  PIN tw_d0[98]
    DIRECTION INPUT ;
    USE SIGNAL ;
    PORT
      LAYER M5 ;
        RECT  33.264 0 33.288 0.084 ;
    END
  END tw_d0[98]
  PIN tw_d0[99]
    DIRECTION INPUT ;
    USE SIGNAL ;
    PORT
      LAYER M5 ;
        RECT  33.36 0 33.384 0.084 ;
    END
  END tw_d0[99]
  PIN tw_d0[9]
    DIRECTION INPUT ;
    USE SIGNAL ;
    PORT
      LAYER M5 ;
        RECT  37.008 0 37.032 0.084 ;
    END
  END tw_d0[9]
  PIN tw_d1[0]
    DIRECTION INPUT ;
    USE SIGNAL ;
    PORT
      LAYER M5 ;
        RECT  200.592 0 200.616 0.084 ;
    END
  END tw_d1[0]
  PIN tw_d1[100]
    DIRECTION INPUT ;
    USE SIGNAL ;
    PORT
      LAYER M5 ;
        RECT  12.048 0 12.072 0.084 ;
    END
  END tw_d1[100]
  PIN tw_d1[101]
    DIRECTION INPUT ;
    USE SIGNAL ;
    PORT
      LAYER M5 ;
        RECT  12.144 0 12.168 0.084 ;
    END
  END tw_d1[101]
  PIN tw_d1[102]
    DIRECTION INPUT ;
    USE SIGNAL ;
    PORT
      LAYER M5 ;
        RECT  12.24 0 12.264 0.084 ;
    END
  END tw_d1[102]
  PIN tw_d1[103]
    DIRECTION INPUT ;
    USE SIGNAL ;
    PORT
      LAYER M5 ;
        RECT  12.336 0 12.36 0.084 ;
    END
  END tw_d1[103]
  PIN tw_d1[104]
    DIRECTION INPUT ;
    USE SIGNAL ;
    PORT
      LAYER M5 ;
        RECT  12.432 0 12.456 0.084 ;
    END
  END tw_d1[104]
  PIN tw_d1[105]
    DIRECTION INPUT ;
    USE SIGNAL ;
    PORT
      LAYER M5 ;
        RECT  12.528 0 12.552 0.084 ;
    END
  END tw_d1[105]
  PIN tw_d1[106]
    DIRECTION INPUT ;
    USE SIGNAL ;
    PORT
      LAYER M5 ;
        RECT  12.624 0 12.648 0.084 ;
    END
  END tw_d1[106]
  PIN tw_d1[107]
    DIRECTION INPUT ;
    USE SIGNAL ;
    PORT
      LAYER M5 ;
        RECT  12.72 0 12.744 0.084 ;
    END
  END tw_d1[107]
  PIN tw_d1[108]
    DIRECTION INPUT ;
    USE SIGNAL ;
    PORT
      LAYER M5 ;
        RECT  12.816 0 12.84 0.084 ;
    END
  END tw_d1[108]
  PIN tw_d1[109]
    DIRECTION INPUT ;
    USE SIGNAL ;
    PORT
      LAYER M5 ;
        RECT  12.912 0 12.936 0.084 ;
    END
  END tw_d1[109]
  PIN tw_d1[10]
    DIRECTION INPUT ;
    USE SIGNAL ;
    PORT
      LAYER M5 ;
        RECT  201.552 0 201.576 0.084 ;
    END
  END tw_d1[10]
  PIN tw_d1[110]
    DIRECTION INPUT ;
    USE SIGNAL ;
    PORT
      LAYER M5 ;
        RECT  61.392 0 61.416 0.084 ;
    END
  END tw_d1[110]
  PIN tw_d1[111]
    DIRECTION INPUT ;
    USE SIGNAL ;
    PORT
      LAYER M5 ;
        RECT  61.488 0 61.512 0.084 ;
    END
  END tw_d1[111]
  PIN tw_d1[112]
    DIRECTION INPUT ;
    USE SIGNAL ;
    PORT
      LAYER M5 ;
        RECT  61.584 0 61.608 0.084 ;
    END
  END tw_d1[112]
  PIN tw_d1[113]
    DIRECTION INPUT ;
    USE SIGNAL ;
    PORT
      LAYER M5 ;
        RECT  61.68 0 61.704 0.084 ;
    END
  END tw_d1[113]
  PIN tw_d1[114]
    DIRECTION INPUT ;
    USE SIGNAL ;
    PORT
      LAYER M5 ;
        RECT  61.776 0 61.8 0.084 ;
    END
  END tw_d1[114]
  PIN tw_d1[115]
    DIRECTION INPUT ;
    USE SIGNAL ;
    PORT
      LAYER M5 ;
        RECT  61.872 0 61.896 0.084 ;
    END
  END tw_d1[115]
  PIN tw_d1[116]
    DIRECTION INPUT ;
    USE SIGNAL ;
    PORT
      LAYER M5 ;
        RECT  61.968 0 61.992 0.084 ;
    END
  END tw_d1[116]
  PIN tw_d1[117]
    DIRECTION INPUT ;
    USE SIGNAL ;
    PORT
      LAYER M5 ;
        RECT  62.064 0 62.088 0.084 ;
    END
  END tw_d1[117]
  PIN tw_d1[118]
    DIRECTION INPUT ;
    USE SIGNAL ;
    PORT
      LAYER M5 ;
        RECT  62.16 0 62.184 0.084 ;
    END
  END tw_d1[118]
  PIN tw_d1[119]
    DIRECTION INPUT ;
    USE SIGNAL ;
    PORT
      LAYER M5 ;
        RECT  62.256 0 62.28 0.084 ;
    END
  END tw_d1[119]
  PIN tw_d1[11]
    DIRECTION INPUT ;
    USE SIGNAL ;
    PORT
      LAYER M5 ;
        RECT  201.648 0 201.672 0.084 ;
    END
  END tw_d1[11]
  PIN tw_d1[120]
    DIRECTION INPUT ;
    USE SIGNAL ;
    PORT
      LAYER M5 ;
        RECT  62.352 0 62.376 0.084 ;
    END
  END tw_d1[120]
  PIN tw_d1[121]
    DIRECTION INPUT ;
    USE SIGNAL ;
    PORT
      LAYER M5 ;
        RECT  62.448 0 62.472 0.084 ;
    END
  END tw_d1[121]
  PIN tw_d1[122]
    DIRECTION INPUT ;
    USE SIGNAL ;
    PORT
      LAYER M5 ;
        RECT  62.544 0 62.568 0.084 ;
    END
  END tw_d1[122]
  PIN tw_d1[123]
    DIRECTION INPUT ;
    USE SIGNAL ;
    PORT
      LAYER M5 ;
        RECT  62.64 0 62.664 0.084 ;
    END
  END tw_d1[123]
  PIN tw_d1[124]
    DIRECTION INPUT ;
    USE SIGNAL ;
    PORT
      LAYER M5 ;
        RECT  62.736 0 62.76 0.084 ;
    END
  END tw_d1[124]
  PIN tw_d1[125]
    DIRECTION INPUT ;
    USE SIGNAL ;
    PORT
      LAYER M5 ;
        RECT  62.832 0 62.856 0.084 ;
    END
  END tw_d1[125]
  PIN tw_d1[126]
    DIRECTION INPUT ;
    USE SIGNAL ;
    PORT
      LAYER M5 ;
        RECT  62.928 0 62.952 0.084 ;
    END
  END tw_d1[126]
  PIN tw_d1[127]
    DIRECTION INPUT ;
    USE SIGNAL ;
    PORT
      LAYER M5 ;
        RECT  63.024 0 63.048 0.084 ;
    END
  END tw_d1[127]
  PIN tw_d1[128]
    DIRECTION INPUT ;
    USE SIGNAL ;
    PORT
      LAYER M5 ;
        RECT  63.12 0 63.144 0.084 ;
    END
  END tw_d1[128]
  PIN tw_d1[129]
    DIRECTION INPUT ;
    USE SIGNAL ;
    PORT
      LAYER M5 ;
        RECT  63.216 0 63.24 0.084 ;
    END
  END tw_d1[129]
  PIN tw_d1[12]
    DIRECTION INPUT ;
    USE SIGNAL ;
    PORT
      LAYER M5 ;
        RECT  201.744 0 201.768 0.084 ;
    END
  END tw_d1[12]
  PIN tw_d1[130]
    DIRECTION INPUT ;
    USE SIGNAL ;
    PORT
      LAYER M5 ;
        RECT  63.312 0 63.336 0.084 ;
    END
  END tw_d1[130]
  PIN tw_d1[131]
    DIRECTION INPUT ;
    USE SIGNAL ;
    PORT
      LAYER M5 ;
        RECT  63.408 0 63.432 0.084 ;
    END
  END tw_d1[131]
  PIN tw_d1[132]
    DIRECTION INPUT ;
    USE SIGNAL ;
    PORT
      LAYER M5 ;
        RECT  63.504 0 63.528 0.084 ;
    END
  END tw_d1[132]
  PIN tw_d1[133]
    DIRECTION INPUT ;
    USE SIGNAL ;
    PORT
      LAYER M5 ;
        RECT  63.6 0 63.624 0.084 ;
    END
  END tw_d1[133]
  PIN tw_d1[134]
    DIRECTION INPUT ;
    USE SIGNAL ;
    PORT
      LAYER M5 ;
        RECT  63.696 0 63.72 0.084 ;
    END
  END tw_d1[134]
  PIN tw_d1[135]
    DIRECTION INPUT ;
    USE SIGNAL ;
    PORT
      LAYER M5 ;
        RECT  63.792 0 63.816 0.084 ;
    END
  END tw_d1[135]
  PIN tw_d1[136]
    DIRECTION INPUT ;
    USE SIGNAL ;
    PORT
      LAYER M5 ;
        RECT  63.888 0 63.912 0.084 ;
    END
  END tw_d1[136]
  PIN tw_d1[137]
    DIRECTION INPUT ;
    USE SIGNAL ;
    PORT
      LAYER M5 ;
        RECT  63.984 0 64.008 0.084 ;
    END
  END tw_d1[137]
  PIN tw_d1[138]
    DIRECTION INPUT ;
    USE SIGNAL ;
    PORT
      LAYER M5 ;
        RECT  64.08 0 64.104 0.084 ;
    END
  END tw_d1[138]
  PIN tw_d1[139]
    DIRECTION INPUT ;
    USE SIGNAL ;
    PORT
      LAYER M5 ;
        RECT  64.176 0 64.2 0.084 ;
    END
  END tw_d1[139]
  PIN tw_d1[13]
    DIRECTION INPUT ;
    USE SIGNAL ;
    PORT
      LAYER M5 ;
        RECT  201.84 0 201.864 0.084 ;
    END
  END tw_d1[13]
  PIN tw_d1[140]
    DIRECTION INPUT ;
    USE SIGNAL ;
    PORT
      LAYER M5 ;
        RECT  64.272 0 64.296 0.084 ;
    END
  END tw_d1[140]
  PIN tw_d1[141]
    DIRECTION INPUT ;
    USE SIGNAL ;
    PORT
      LAYER M5 ;
        RECT  64.368 0 64.392 0.084 ;
    END
  END tw_d1[141]
  PIN tw_d1[142]
    DIRECTION INPUT ;
    USE SIGNAL ;
    PORT
      LAYER M5 ;
        RECT  211.92 0 211.944 0.084 ;
    END
  END tw_d1[142]
  PIN tw_d1[143]
    DIRECTION INPUT ;
    USE SIGNAL ;
    PORT
      LAYER M5 ;
        RECT  212.016 0 212.04 0.084 ;
    END
  END tw_d1[143]
  PIN tw_d1[144]
    DIRECTION INPUT ;
    USE SIGNAL ;
    PORT
      LAYER M5 ;
        RECT  212.112 0 212.136 0.084 ;
    END
  END tw_d1[144]
  PIN tw_d1[145]
    DIRECTION INPUT ;
    USE SIGNAL ;
    PORT
      LAYER M5 ;
        RECT  212.208 0 212.232 0.084 ;
    END
  END tw_d1[145]
  PIN tw_d1[146]
    DIRECTION INPUT ;
    USE SIGNAL ;
    PORT
      LAYER M5 ;
        RECT  212.304 0 212.328 0.084 ;
    END
  END tw_d1[146]
  PIN tw_d1[147]
    DIRECTION INPUT ;
    USE SIGNAL ;
    PORT
      LAYER M5 ;
        RECT  212.4 0 212.424 0.084 ;
    END
  END tw_d1[147]
  PIN tw_d1[148]
    DIRECTION INPUT ;
    USE SIGNAL ;
    PORT
      LAYER M5 ;
        RECT  212.496 0 212.52 0.084 ;
    END
  END tw_d1[148]
  PIN tw_d1[149]
    DIRECTION INPUT ;
    USE SIGNAL ;
    PORT
      LAYER M5 ;
        RECT  212.592 0 212.616 0.084 ;
    END
  END tw_d1[149]
  PIN tw_d1[14]
    DIRECTION INPUT ;
    USE SIGNAL ;
    PORT
      LAYER M5 ;
        RECT  42.192 0 42.216 0.084 ;
    END
  END tw_d1[14]
  PIN tw_d1[150]
    DIRECTION INPUT ;
    USE SIGNAL ;
    PORT
      LAYER M5 ;
        RECT  212.688 0 212.712 0.084 ;
    END
  END tw_d1[150]
  PIN tw_d1[151]
    DIRECTION INPUT ;
    USE SIGNAL ;
    PORT
      LAYER M5 ;
        RECT  212.784 0 212.808 0.084 ;
    END
  END tw_d1[151]
  PIN tw_d1[152]
    DIRECTION INPUT ;
    USE SIGNAL ;
    PORT
      LAYER M5 ;
        RECT  212.88 0 212.904 0.084 ;
    END
  END tw_d1[152]
  PIN tw_d1[153]
    DIRECTION INPUT ;
    USE SIGNAL ;
    PORT
      LAYER M5 ;
        RECT  212.976 0 213 0.084 ;
    END
  END tw_d1[153]
  PIN tw_d1[154]
    DIRECTION INPUT ;
    USE SIGNAL ;
    PORT
      LAYER M5 ;
        RECT  213.072 0 213.096 0.084 ;
    END
  END tw_d1[154]
  PIN tw_d1[155]
    DIRECTION INPUT ;
    USE SIGNAL ;
    PORT
      LAYER M5 ;
        RECT  213.168 0 213.192 0.084 ;
    END
  END tw_d1[155]
  PIN tw_d1[156]
    DIRECTION INPUT ;
    USE SIGNAL ;
    PORT
      LAYER M5 ;
        RECT  213.264 0 213.288 0.084 ;
    END
  END tw_d1[156]
  PIN tw_d1[157]
    DIRECTION INPUT ;
    USE SIGNAL ;
    PORT
      LAYER M5 ;
        RECT  213.36 0 213.384 0.084 ;
    END
  END tw_d1[157]
  PIN tw_d1[158]
    DIRECTION INPUT ;
    USE SIGNAL ;
    PORT
      LAYER M5 ;
        RECT  213.456 0 213.48 0.084 ;
    END
  END tw_d1[158]
  PIN tw_d1[159]
    DIRECTION INPUT ;
    USE SIGNAL ;
    PORT
      LAYER M5 ;
        RECT  213.552 0 213.576 0.084 ;
    END
  END tw_d1[159]
  PIN tw_d1[15]
    DIRECTION INPUT ;
    USE SIGNAL ;
    PORT
      LAYER M5 ;
        RECT  42.288 0 42.312 0.084 ;
    END
  END tw_d1[15]
  PIN tw_d1[160]
    DIRECTION INPUT ;
    USE SIGNAL ;
    PORT
      LAYER M5 ;
        RECT  213.648 0 213.672 0.084 ;
    END
  END tw_d1[160]
  PIN tw_d1[161]
    DIRECTION INPUT ;
    USE SIGNAL ;
    PORT
      LAYER M5 ;
        RECT  213.744 0 213.768 0.084 ;
    END
  END tw_d1[161]
  PIN tw_d1[162]
    DIRECTION INPUT ;
    USE SIGNAL ;
    PORT
      LAYER M5 ;
        RECT  213.84 0 213.864 0.084 ;
    END
  END tw_d1[162]
  PIN tw_d1[163]
    DIRECTION INPUT ;
    USE SIGNAL ;
    PORT
      LAYER M5 ;
        RECT  213.936 0 213.96 0.084 ;
    END
  END tw_d1[163]
  PIN tw_d1[164]
    DIRECTION INPUT ;
    USE SIGNAL ;
    PORT
      LAYER M5 ;
        RECT  214.032 0 214.056 0.084 ;
    END
  END tw_d1[164]
  PIN tw_d1[165]
    DIRECTION INPUT ;
    USE SIGNAL ;
    PORT
      LAYER M5 ;
        RECT  214.128 0 214.152 0.084 ;
    END
  END tw_d1[165]
  PIN tw_d1[166]
    DIRECTION INPUT ;
    USE SIGNAL ;
    PORT
      LAYER M5 ;
        RECT  214.224 0 214.248 0.084 ;
    END
  END tw_d1[166]
  PIN tw_d1[167]
    DIRECTION INPUT ;
    USE SIGNAL ;
    PORT
      LAYER M5 ;
        RECT  214.32 0 214.344 0.084 ;
    END
  END tw_d1[167]
  PIN tw_d1[168]
    DIRECTION INPUT ;
    USE SIGNAL ;
    PORT
      LAYER M5 ;
        RECT  214.416 0 214.44 0.084 ;
    END
  END tw_d1[168]
  PIN tw_d1[169]
    DIRECTION INPUT ;
    USE SIGNAL ;
    PORT
      LAYER M5 ;
        RECT  214.512 0 214.536 0.084 ;
    END
  END tw_d1[169]
  PIN tw_d1[16]
    DIRECTION INPUT ;
    USE SIGNAL ;
    PORT
      LAYER M5 ;
        RECT  42.384 0 42.408 0.084 ;
    END
  END tw_d1[16]
  PIN tw_d1[170]
    DIRECTION INPUT ;
    USE SIGNAL ;
    PORT
      LAYER M5 ;
        RECT  214.608 0 214.632 0.084 ;
    END
  END tw_d1[170]
  PIN tw_d1[171]
    DIRECTION INPUT ;
    USE SIGNAL ;
    PORT
      LAYER M5 ;
        RECT  214.704 0 214.728 0.084 ;
    END
  END tw_d1[171]
  PIN tw_d1[172]
    DIRECTION INPUT ;
    USE SIGNAL ;
    PORT
      LAYER M5 ;
        RECT  214.8 0 214.824 0.084 ;
    END
  END tw_d1[172]
  PIN tw_d1[173]
    DIRECTION INPUT ;
    USE SIGNAL ;
    PORT
      LAYER M5 ;
        RECT  214.896 0 214.92 0.084 ;
    END
  END tw_d1[173]
  PIN tw_d1[174]
    DIRECTION INPUT ;
    USE SIGNAL ;
    PORT
      LAYER M5 ;
        RECT  221.136 0 221.16 0.084 ;
    END
  END tw_d1[174]
  PIN tw_d1[175]
    DIRECTION INPUT ;
    USE SIGNAL ;
    PORT
      LAYER M5 ;
        RECT  221.232 0 221.256 0.084 ;
    END
  END tw_d1[175]
  PIN tw_d1[176]
    DIRECTION INPUT ;
    USE SIGNAL ;
    PORT
      LAYER M5 ;
        RECT  221.328 0 221.352 0.084 ;
    END
  END tw_d1[176]
  PIN tw_d1[177]
    DIRECTION INPUT ;
    USE SIGNAL ;
    PORT
      LAYER M5 ;
        RECT  221.424 0 221.448 0.084 ;
    END
  END tw_d1[177]
  PIN tw_d1[178]
    DIRECTION INPUT ;
    USE SIGNAL ;
    PORT
      LAYER M5 ;
        RECT  221.52 0 221.544 0.084 ;
    END
  END tw_d1[178]
  PIN tw_d1[179]
    DIRECTION INPUT ;
    USE SIGNAL ;
    PORT
      LAYER M5 ;
        RECT  221.616 0 221.64 0.084 ;
    END
  END tw_d1[179]
  PIN tw_d1[17]
    DIRECTION INPUT ;
    USE SIGNAL ;
    PORT
      LAYER M5 ;
        RECT  42.48 0 42.504 0.084 ;
    END
  END tw_d1[17]
  PIN tw_d1[180]
    DIRECTION INPUT ;
    USE SIGNAL ;
    PORT
      LAYER M5 ;
        RECT  221.712 0 221.736 0.084 ;
    END
  END tw_d1[180]
  PIN tw_d1[181]
    DIRECTION INPUT ;
    USE SIGNAL ;
    PORT
      LAYER M5 ;
        RECT  221.808 0 221.832 0.084 ;
    END
  END tw_d1[181]
  PIN tw_d1[182]
    DIRECTION INPUT ;
    USE SIGNAL ;
    PORT
      LAYER M5 ;
        RECT  221.904 0 221.928 0.084 ;
    END
  END tw_d1[182]
  PIN tw_d1[183]
    DIRECTION INPUT ;
    USE SIGNAL ;
    PORT
      LAYER M5 ;
        RECT  222 0 222.024 0.084 ;
    END
  END tw_d1[183]
  PIN tw_d1[184]
    DIRECTION INPUT ;
    USE SIGNAL ;
    PORT
      LAYER M5 ;
        RECT  222.096 0 222.12 0.084 ;
    END
  END tw_d1[184]
  PIN tw_d1[185]
    DIRECTION INPUT ;
    USE SIGNAL ;
    PORT
      LAYER M5 ;
        RECT  222.192 0 222.216 0.084 ;
    END
  END tw_d1[185]
  PIN tw_d1[186]
    DIRECTION INPUT ;
    USE SIGNAL ;
    PORT
      LAYER M5 ;
        RECT  222.288 0 222.312 0.084 ;
    END
  END tw_d1[186]
  PIN tw_d1[187]
    DIRECTION INPUT ;
    USE SIGNAL ;
    PORT
      LAYER M5 ;
        RECT  222.384 0 222.408 0.084 ;
    END
  END tw_d1[187]
  PIN tw_d1[188]
    DIRECTION INPUT ;
    USE SIGNAL ;
    PORT
      LAYER M5 ;
        RECT  222.48 0 222.504 0.084 ;
    END
  END tw_d1[188]
  PIN tw_d1[189]
    DIRECTION INPUT ;
    USE SIGNAL ;
    PORT
      LAYER M5 ;
        RECT  222.576 0 222.6 0.084 ;
    END
  END tw_d1[189]
  PIN tw_d1[18]
    DIRECTION INPUT ;
    USE SIGNAL ;
    PORT
      LAYER M5 ;
        RECT  42.576 0 42.6 0.084 ;
    END
  END tw_d1[18]
  PIN tw_d1[190]
    DIRECTION INPUT ;
    USE SIGNAL ;
    PORT
      LAYER M5 ;
        RECT  222.672 0 222.696 0.084 ;
    END
  END tw_d1[190]
  PIN tw_d1[191]
    DIRECTION INPUT ;
    USE SIGNAL ;
    PORT
      LAYER M5 ;
        RECT  222.768 0 222.792 0.084 ;
    END
  END tw_d1[191]
  PIN tw_d1[192]
    DIRECTION INPUT ;
    USE SIGNAL ;
    PORT
      LAYER M5 ;
        RECT  222.864 0 222.888 0.084 ;
    END
  END tw_d1[192]
  PIN tw_d1[193]
    DIRECTION INPUT ;
    USE SIGNAL ;
    PORT
      LAYER M5 ;
        RECT  222.96 0 222.984 0.084 ;
    END
  END tw_d1[193]
  PIN tw_d1[194]
    DIRECTION INPUT ;
    USE SIGNAL ;
    PORT
      LAYER M5 ;
        RECT  223.056 0 223.08 0.084 ;
    END
  END tw_d1[194]
  PIN tw_d1[195]
    DIRECTION INPUT ;
    USE SIGNAL ;
    PORT
      LAYER M5 ;
        RECT  223.152 0 223.176 0.084 ;
    END
  END tw_d1[195]
  PIN tw_d1[196]
    DIRECTION INPUT ;
    USE SIGNAL ;
    PORT
      LAYER M5 ;
        RECT  223.248 0 223.272 0.084 ;
    END
  END tw_d1[196]
  PIN tw_d1[197]
    DIRECTION INPUT ;
    USE SIGNAL ;
    PORT
      LAYER M5 ;
        RECT  223.344 0 223.368 0.084 ;
    END
  END tw_d1[197]
  PIN tw_d1[198]
    DIRECTION INPUT ;
    USE SIGNAL ;
    PORT
      LAYER M5 ;
        RECT  223.44 0 223.464 0.084 ;
    END
  END tw_d1[198]
  PIN tw_d1[199]
    DIRECTION INPUT ;
    USE SIGNAL ;
    PORT
      LAYER M5 ;
        RECT  223.536 0 223.56 0.084 ;
    END
  END tw_d1[199]
  PIN tw_d1[19]
    DIRECTION INPUT ;
    USE SIGNAL ;
    PORT
      LAYER M5 ;
        RECT  42.672 0 42.696 0.084 ;
    END
  END tw_d1[19]
  PIN tw_d1[1]
    DIRECTION INPUT ;
    USE SIGNAL ;
    PORT
      LAYER M5 ;
        RECT  200.688 0 200.712 0.084 ;
    END
  END tw_d1[1]
  PIN tw_d1[200]
    DIRECTION INPUT ;
    USE SIGNAL ;
    PORT
      LAYER M5 ;
        RECT  223.632 0 223.656 0.084 ;
    END
  END tw_d1[200]
  PIN tw_d1[201]
    DIRECTION INPUT ;
    USE SIGNAL ;
    PORT
      LAYER M5 ;
        RECT  223.728 0 223.752 0.084 ;
    END
  END tw_d1[201]
  PIN tw_d1[202]
    DIRECTION INPUT ;
    USE SIGNAL ;
    PORT
      LAYER M5 ;
        RECT  223.824 0 223.848 0.084 ;
    END
  END tw_d1[202]
  PIN tw_d1[203]
    DIRECTION INPUT ;
    USE SIGNAL ;
    PORT
      LAYER M5 ;
        RECT  223.92 0 223.944 0.084 ;
    END
  END tw_d1[203]
  PIN tw_d1[204]
    DIRECTION INPUT ;
    USE SIGNAL ;
    PORT
      LAYER M5 ;
        RECT  224.016 0 224.04 0.084 ;
    END
  END tw_d1[204]
  PIN tw_d1[205]
    DIRECTION INPUT ;
    USE SIGNAL ;
    PORT
      LAYER M5 ;
        RECT  224.112 0 224.136 0.084 ;
    END
  END tw_d1[205]
  PIN tw_d1[206]
    DIRECTION INPUT ;
    USE SIGNAL ;
    PORT
      LAYER M5 ;
        RECT  208.08 0 208.104 0.084 ;
    END
  END tw_d1[206]
  PIN tw_d1[207]
    DIRECTION INPUT ;
    USE SIGNAL ;
    PORT
      LAYER M5 ;
        RECT  208.176 0 208.2 0.084 ;
    END
  END tw_d1[207]
  PIN tw_d1[208]
    DIRECTION INPUT ;
    USE SIGNAL ;
    PORT
      LAYER M5 ;
        RECT  208.272 0 208.296 0.084 ;
    END
  END tw_d1[208]
  PIN tw_d1[209]
    DIRECTION INPUT ;
    USE SIGNAL ;
    PORT
      LAYER M5 ;
        RECT  208.368 0 208.392 0.084 ;
    END
  END tw_d1[209]
  PIN tw_d1[20]
    DIRECTION INPUT ;
    USE SIGNAL ;
    PORT
      LAYER M5 ;
        RECT  42.768 0 42.792 0.084 ;
    END
  END tw_d1[20]
  PIN tw_d1[210]
    DIRECTION INPUT ;
    USE SIGNAL ;
    PORT
      LAYER M5 ;
        RECT  208.464 0 208.488 0.084 ;
    END
  END tw_d1[210]
  PIN tw_d1[211]
    DIRECTION INPUT ;
    USE SIGNAL ;
    PORT
      LAYER M5 ;
        RECT  208.56 0 208.584 0.084 ;
    END
  END tw_d1[211]
  PIN tw_d1[212]
    DIRECTION INPUT ;
    USE SIGNAL ;
    PORT
      LAYER M5 ;
        RECT  208.656 0 208.68 0.084 ;
    END
  END tw_d1[212]
  PIN tw_d1[213]
    DIRECTION INPUT ;
    USE SIGNAL ;
    PORT
      LAYER M5 ;
        RECT  208.752 0 208.776 0.084 ;
    END
  END tw_d1[213]
  PIN tw_d1[214]
    DIRECTION INPUT ;
    USE SIGNAL ;
    PORT
      LAYER M5 ;
        RECT  208.848 0 208.872 0.084 ;
    END
  END tw_d1[214]
  PIN tw_d1[215]
    DIRECTION INPUT ;
    USE SIGNAL ;
    PORT
      LAYER M5 ;
        RECT  208.944 0 208.968 0.084 ;
    END
  END tw_d1[215]
  PIN tw_d1[216]
    DIRECTION INPUT ;
    USE SIGNAL ;
    PORT
      LAYER M5 ;
        RECT  209.04 0 209.064 0.084 ;
    END
  END tw_d1[216]
  PIN tw_d1[217]
    DIRECTION INPUT ;
    USE SIGNAL ;
    PORT
      LAYER M5 ;
        RECT  209.136 0 209.16 0.084 ;
    END
  END tw_d1[217]
  PIN tw_d1[218]
    DIRECTION INPUT ;
    USE SIGNAL ;
    PORT
      LAYER M5 ;
        RECT  209.232 0 209.256 0.084 ;
    END
  END tw_d1[218]
  PIN tw_d1[219]
    DIRECTION INPUT ;
    USE SIGNAL ;
    PORT
      LAYER M5 ;
        RECT  209.328 0 209.352 0.084 ;
    END
  END tw_d1[219]
  PIN tw_d1[21]
    DIRECTION INPUT ;
    USE SIGNAL ;
    PORT
      LAYER M5 ;
        RECT  42.864 0 42.888 0.084 ;
    END
  END tw_d1[21]
  PIN tw_d1[220]
    DIRECTION INPUT ;
    USE SIGNAL ;
    PORT
      LAYER M5 ;
        RECT  209.424 0 209.448 0.084 ;
    END
  END tw_d1[220]
  PIN tw_d1[221]
    DIRECTION INPUT ;
    USE SIGNAL ;
    PORT
      LAYER M5 ;
        RECT  209.52 0 209.544 0.084 ;
    END
  END tw_d1[221]
  PIN tw_d1[222]
    DIRECTION INPUT ;
    USE SIGNAL ;
    PORT
      LAYER M5 ;
        RECT  209.616 0 209.64 0.084 ;
    END
  END tw_d1[222]
  PIN tw_d1[223]
    DIRECTION INPUT ;
    USE SIGNAL ;
    PORT
      LAYER M5 ;
        RECT  209.712 0 209.736 0.084 ;
    END
  END tw_d1[223]
  PIN tw_d1[224]
    DIRECTION INPUT ;
    USE SIGNAL ;
    PORT
      LAYER M5 ;
        RECT  209.808 0 209.832 0.084 ;
    END
  END tw_d1[224]
  PIN tw_d1[225]
    DIRECTION INPUT ;
    USE SIGNAL ;
    PORT
      LAYER M5 ;
        RECT  209.904 0 209.928 0.084 ;
    END
  END tw_d1[225]
  PIN tw_d1[226]
    DIRECTION INPUT ;
    USE SIGNAL ;
    PORT
      LAYER M5 ;
        RECT  210 0 210.024 0.084 ;
    END
  END tw_d1[226]
  PIN tw_d1[227]
    DIRECTION INPUT ;
    USE SIGNAL ;
    PORT
      LAYER M5 ;
        RECT  210.096 0 210.12 0.084 ;
    END
  END tw_d1[227]
  PIN tw_d1[228]
    DIRECTION INPUT ;
    USE SIGNAL ;
    PORT
      LAYER M5 ;
        RECT  210.192 0 210.216 0.084 ;
    END
  END tw_d1[228]
  PIN tw_d1[229]
    DIRECTION INPUT ;
    USE SIGNAL ;
    PORT
      LAYER M5 ;
        RECT  210.288 0 210.312 0.084 ;
    END
  END tw_d1[229]
  PIN tw_d1[22]
    DIRECTION INPUT ;
    USE SIGNAL ;
    PORT
      LAYER M5 ;
        RECT  42.96 0 42.984 0.084 ;
    END
  END tw_d1[22]
  PIN tw_d1[230]
    DIRECTION INPUT ;
    USE SIGNAL ;
    PORT
      LAYER M5 ;
        RECT  210.384 0 210.408 0.084 ;
    END
  END tw_d1[230]
  PIN tw_d1[231]
    DIRECTION INPUT ;
    USE SIGNAL ;
    PORT
      LAYER M5 ;
        RECT  210.48 0 210.504 0.084 ;
    END
  END tw_d1[231]
  PIN tw_d1[232]
    DIRECTION INPUT ;
    USE SIGNAL ;
    PORT
      LAYER M5 ;
        RECT  210.576 0 210.6 0.084 ;
    END
  END tw_d1[232]
  PIN tw_d1[233]
    DIRECTION INPUT ;
    USE SIGNAL ;
    PORT
      LAYER M5 ;
        RECT  210.672 0 210.696 0.084 ;
    END
  END tw_d1[233]
  PIN tw_d1[234]
    DIRECTION INPUT ;
    USE SIGNAL ;
    PORT
      LAYER M5 ;
        RECT  210.768 0 210.792 0.084 ;
    END
  END tw_d1[234]
  PIN tw_d1[235]
    DIRECTION INPUT ;
    USE SIGNAL ;
    PORT
      LAYER M5 ;
        RECT  210.864 0 210.888 0.084 ;
    END
  END tw_d1[235]
  PIN tw_d1[236]
    DIRECTION INPUT ;
    USE SIGNAL ;
    PORT
      LAYER M5 ;
        RECT  210.96 0 210.984 0.084 ;
    END
  END tw_d1[236]
  PIN tw_d1[237]
    DIRECTION INPUT ;
    USE SIGNAL ;
    PORT
      LAYER M5 ;
        RECT  211.056 0 211.08 0.084 ;
    END
  END tw_d1[237]
  PIN tw_d1[238]
    DIRECTION INPUT ;
    USE SIGNAL ;
    PORT
      LAYER M5 ;
        RECT  195.792 0 195.816 0.084 ;
    END
  END tw_d1[238]
  PIN tw_d1[239]
    DIRECTION INPUT ;
    USE SIGNAL ;
    PORT
      LAYER M5 ;
        RECT  195.888 0 195.912 0.084 ;
    END
  END tw_d1[239]
  PIN tw_d1[23]
    DIRECTION INPUT ;
    USE SIGNAL ;
    PORT
      LAYER M5 ;
        RECT  43.056 0 43.08 0.084 ;
    END
  END tw_d1[23]
  PIN tw_d1[240]
    DIRECTION INPUT ;
    USE SIGNAL ;
    PORT
      LAYER M5 ;
        RECT  195.984 0 196.008 0.084 ;
    END
  END tw_d1[240]
  PIN tw_d1[241]
    DIRECTION INPUT ;
    USE SIGNAL ;
    PORT
      LAYER M5 ;
        RECT  196.08 0 196.104 0.084 ;
    END
  END tw_d1[241]
  PIN tw_d1[242]
    DIRECTION INPUT ;
    USE SIGNAL ;
    PORT
      LAYER M5 ;
        RECT  196.176 0 196.2 0.084 ;
    END
  END tw_d1[242]
  PIN tw_d1[243]
    DIRECTION INPUT ;
    USE SIGNAL ;
    PORT
      LAYER M5 ;
        RECT  196.272 0 196.296 0.084 ;
    END
  END tw_d1[243]
  PIN tw_d1[244]
    DIRECTION INPUT ;
    USE SIGNAL ;
    PORT
      LAYER M5 ;
        RECT  196.368 0 196.392 0.084 ;
    END
  END tw_d1[244]
  PIN tw_d1[245]
    DIRECTION INPUT ;
    USE SIGNAL ;
    PORT
      LAYER M5 ;
        RECT  196.464 0 196.488 0.084 ;
    END
  END tw_d1[245]
  PIN tw_d1[246]
    DIRECTION INPUT ;
    USE SIGNAL ;
    PORT
      LAYER M5 ;
        RECT  196.56 0 196.584 0.084 ;
    END
  END tw_d1[246]
  PIN tw_d1[247]
    DIRECTION INPUT ;
    USE SIGNAL ;
    PORT
      LAYER M5 ;
        RECT  196.656 0 196.68 0.084 ;
    END
  END tw_d1[247]
  PIN tw_d1[248]
    DIRECTION INPUT ;
    USE SIGNAL ;
    PORT
      LAYER M5 ;
        RECT  196.752 0 196.776 0.084 ;
    END
  END tw_d1[248]
  PIN tw_d1[249]
    DIRECTION INPUT ;
    USE SIGNAL ;
    PORT
      LAYER M5 ;
        RECT  196.848 0 196.872 0.084 ;
    END
  END tw_d1[249]
  PIN tw_d1[24]
    DIRECTION INPUT ;
    USE SIGNAL ;
    PORT
      LAYER M5 ;
        RECT  43.152 0 43.176 0.084 ;
    END
  END tw_d1[24]
  PIN tw_d1[250]
    DIRECTION INPUT ;
    USE SIGNAL ;
    PORT
      LAYER M5 ;
        RECT  196.944 0 196.968 0.084 ;
    END
  END tw_d1[250]
  PIN tw_d1[251]
    DIRECTION INPUT ;
    USE SIGNAL ;
    PORT
      LAYER M5 ;
        RECT  197.04 0 197.064 0.084 ;
    END
  END tw_d1[251]
  PIN tw_d1[252]
    DIRECTION INPUT ;
    USE SIGNAL ;
    PORT
      LAYER M5 ;
        RECT  197.136 0 197.16 0.084 ;
    END
  END tw_d1[252]
  PIN tw_d1[253]
    DIRECTION INPUT ;
    USE SIGNAL ;
    PORT
      LAYER M5 ;
        RECT  197.232 0 197.256 0.084 ;
    END
  END tw_d1[253]
  PIN tw_d1[254]
    DIRECTION INPUT ;
    USE SIGNAL ;
    PORT
      LAYER M5 ;
        RECT  197.328 0 197.352 0.084 ;
    END
  END tw_d1[254]
  PIN tw_d1[255]
    DIRECTION INPUT ;
    USE SIGNAL ;
    PORT
      LAYER M5 ;
        RECT  197.424 0 197.448 0.084 ;
    END
  END tw_d1[255]
  PIN tw_d1[256]
    DIRECTION INPUT ;
    USE SIGNAL ;
    PORT
      LAYER M5 ;
        RECT  197.52 0 197.544 0.084 ;
    END
  END tw_d1[256]
  PIN tw_d1[257]
    DIRECTION INPUT ;
    USE SIGNAL ;
    PORT
      LAYER M5 ;
        RECT  197.616 0 197.64 0.084 ;
    END
  END tw_d1[257]
  PIN tw_d1[258]
    DIRECTION INPUT ;
    USE SIGNAL ;
    PORT
      LAYER M5 ;
        RECT  197.712 0 197.736 0.084 ;
    END
  END tw_d1[258]
  PIN tw_d1[259]
    DIRECTION INPUT ;
    USE SIGNAL ;
    PORT
      LAYER M5 ;
        RECT  197.808 0 197.832 0.084 ;
    END
  END tw_d1[259]
  PIN tw_d1[25]
    DIRECTION INPUT ;
    USE SIGNAL ;
    PORT
      LAYER M5 ;
        RECT  43.248 0 43.272 0.084 ;
    END
  END tw_d1[25]
  PIN tw_d1[260]
    DIRECTION INPUT ;
    USE SIGNAL ;
    PORT
      LAYER M5 ;
        RECT  197.904 0 197.928 0.084 ;
    END
  END tw_d1[260]
  PIN tw_d1[261]
    DIRECTION INPUT ;
    USE SIGNAL ;
    PORT
      LAYER M5 ;
        RECT  198 0 198.024 0.084 ;
    END
  END tw_d1[261]
  PIN tw_d1[262]
    DIRECTION INPUT ;
    USE SIGNAL ;
    PORT
      LAYER M5 ;
        RECT  198.096 0 198.12 0.084 ;
    END
  END tw_d1[262]
  PIN tw_d1[263]
    DIRECTION INPUT ;
    USE SIGNAL ;
    PORT
      LAYER M5 ;
        RECT  198.192 0 198.216 0.084 ;
    END
  END tw_d1[263]
  PIN tw_d1[264]
    DIRECTION INPUT ;
    USE SIGNAL ;
    PORT
      LAYER M5 ;
        RECT  198.288 0 198.312 0.084 ;
    END
  END tw_d1[264]
  PIN tw_d1[265]
    DIRECTION INPUT ;
    USE SIGNAL ;
    PORT
      LAYER M5 ;
        RECT  198.384 0 198.408 0.084 ;
    END
  END tw_d1[265]
  PIN tw_d1[266]
    DIRECTION INPUT ;
    USE SIGNAL ;
    PORT
      LAYER M5 ;
        RECT  198.48 0 198.504 0.084 ;
    END
  END tw_d1[266]
  PIN tw_d1[267]
    DIRECTION INPUT ;
    USE SIGNAL ;
    PORT
      LAYER M5 ;
        RECT  198.576 0 198.6 0.084 ;
    END
  END tw_d1[267]
  PIN tw_d1[268]
    DIRECTION INPUT ;
    USE SIGNAL ;
    PORT
      LAYER M5 ;
        RECT  198.672 0 198.696 0.084 ;
    END
  END tw_d1[268]
  PIN tw_d1[269]
    DIRECTION INPUT ;
    USE SIGNAL ;
    PORT
      LAYER M5 ;
        RECT  198.768 0 198.792 0.084 ;
    END
  END tw_d1[269]
  PIN tw_d1[26]
    DIRECTION INPUT ;
    USE SIGNAL ;
    PORT
      LAYER M5 ;
        RECT  43.344 0 43.368 0.084 ;
    END
  END tw_d1[26]
  PIN tw_d1[270]
    DIRECTION INPUT ;
    USE SIGNAL ;
    PORT
      LAYER M5 ;
        RECT  16.08 0 16.104 0.084 ;
    END
  END tw_d1[270]
  PIN tw_d1[271]
    DIRECTION INPUT ;
    USE SIGNAL ;
    PORT
      LAYER M5 ;
        RECT  16.176 0 16.2 0.084 ;
    END
  END tw_d1[271]
  PIN tw_d1[272]
    DIRECTION INPUT ;
    USE SIGNAL ;
    PORT
      LAYER M5 ;
        RECT  16.272 0 16.296 0.084 ;
    END
  END tw_d1[272]
  PIN tw_d1[273]
    DIRECTION INPUT ;
    USE SIGNAL ;
    PORT
      LAYER M5 ;
        RECT  16.368 0 16.392 0.084 ;
    END
  END tw_d1[273]
  PIN tw_d1[274]
    DIRECTION INPUT ;
    USE SIGNAL ;
    PORT
      LAYER M5 ;
        RECT  16.464 0 16.488 0.084 ;
    END
  END tw_d1[274]
  PIN tw_d1[275]
    DIRECTION INPUT ;
    USE SIGNAL ;
    PORT
      LAYER M5 ;
        RECT  16.56 0 16.584 0.084 ;
    END
  END tw_d1[275]
  PIN tw_d1[276]
    DIRECTION INPUT ;
    USE SIGNAL ;
    PORT
      LAYER M5 ;
        RECT  16.656 0 16.68 0.084 ;
    END
  END tw_d1[276]
  PIN tw_d1[277]
    DIRECTION INPUT ;
    USE SIGNAL ;
    PORT
      LAYER M5 ;
        RECT  16.752 0 16.776 0.084 ;
    END
  END tw_d1[277]
  PIN tw_d1[278]
    DIRECTION INPUT ;
    USE SIGNAL ;
    PORT
      LAYER M5 ;
        RECT  16.848 0 16.872 0.084 ;
    END
  END tw_d1[278]
  PIN tw_d1[279]
    DIRECTION INPUT ;
    USE SIGNAL ;
    PORT
      LAYER M5 ;
        RECT  16.944 0 16.968 0.084 ;
    END
  END tw_d1[279]
  PIN tw_d1[27]
    DIRECTION INPUT ;
    USE SIGNAL ;
    PORT
      LAYER M5 ;
        RECT  43.44 0 43.464 0.084 ;
    END
  END tw_d1[27]
  PIN tw_d1[280]
    DIRECTION INPUT ;
    USE SIGNAL ;
    PORT
      LAYER M5 ;
        RECT  17.04 0 17.064 0.084 ;
    END
  END tw_d1[280]
  PIN tw_d1[281]
    DIRECTION INPUT ;
    USE SIGNAL ;
    PORT
      LAYER M5 ;
        RECT  17.136 0 17.16 0.084 ;
    END
  END tw_d1[281]
  PIN tw_d1[282]
    DIRECTION INPUT ;
    USE SIGNAL ;
    PORT
      LAYER M5 ;
        RECT  17.232 0 17.256 0.084 ;
    END
  END tw_d1[282]
  PIN tw_d1[283]
    DIRECTION INPUT ;
    USE SIGNAL ;
    PORT
      LAYER M5 ;
        RECT  17.328 0 17.352 0.084 ;
    END
  END tw_d1[283]
  PIN tw_d1[284]
    DIRECTION INPUT ;
    USE SIGNAL ;
    PORT
      LAYER M5 ;
        RECT  17.424 0 17.448 0.084 ;
    END
  END tw_d1[284]
  PIN tw_d1[285]
    DIRECTION INPUT ;
    USE SIGNAL ;
    PORT
      LAYER M5 ;
        RECT  17.52 0 17.544 0.084 ;
    END
  END tw_d1[285]
  PIN tw_d1[286]
    DIRECTION INPUT ;
    USE SIGNAL ;
    PORT
      LAYER M5 ;
        RECT  17.616 0 17.64 0.084 ;
    END
  END tw_d1[286]
  PIN tw_d1[287]
    DIRECTION INPUT ;
    USE SIGNAL ;
    PORT
      LAYER M5 ;
        RECT  17.712 0 17.736 0.084 ;
    END
  END tw_d1[287]
  PIN tw_d1[288]
    DIRECTION INPUT ;
    USE SIGNAL ;
    PORT
      LAYER M5 ;
        RECT  17.808 0 17.832 0.084 ;
    END
  END tw_d1[288]
  PIN tw_d1[289]
    DIRECTION INPUT ;
    USE SIGNAL ;
    PORT
      LAYER M5 ;
        RECT  17.904 0 17.928 0.084 ;
    END
  END tw_d1[289]
  PIN tw_d1[28]
    DIRECTION INPUT ;
    USE SIGNAL ;
    PORT
      LAYER M5 ;
        RECT  43.536 0 43.56 0.084 ;
    END
  END tw_d1[28]
  PIN tw_d1[290]
    DIRECTION INPUT ;
    USE SIGNAL ;
    PORT
      LAYER M5 ;
        RECT  18 0 18.024 0.084 ;
    END
  END tw_d1[290]
  PIN tw_d1[291]
    DIRECTION INPUT ;
    USE SIGNAL ;
    PORT
      LAYER M5 ;
        RECT  18.096 0 18.12 0.084 ;
    END
  END tw_d1[291]
  PIN tw_d1[292]
    DIRECTION INPUT ;
    USE SIGNAL ;
    PORT
      LAYER M5 ;
        RECT  18.192 0 18.216 0.084 ;
    END
  END tw_d1[292]
  PIN tw_d1[293]
    DIRECTION INPUT ;
    USE SIGNAL ;
    PORT
      LAYER M5 ;
        RECT  18.288 0 18.312 0.084 ;
    END
  END tw_d1[293]
  PIN tw_d1[294]
    DIRECTION INPUT ;
    USE SIGNAL ;
    PORT
      LAYER M5 ;
        RECT  18.384 0 18.408 0.084 ;
    END
  END tw_d1[294]
  PIN tw_d1[295]
    DIRECTION INPUT ;
    USE SIGNAL ;
    PORT
      LAYER M5 ;
        RECT  18.48 0 18.504 0.084 ;
    END
  END tw_d1[295]
  PIN tw_d1[296]
    DIRECTION INPUT ;
    USE SIGNAL ;
    PORT
      LAYER M5 ;
        RECT  18.576 0 18.6 0.084 ;
    END
  END tw_d1[296]
  PIN tw_d1[297]
    DIRECTION INPUT ;
    USE SIGNAL ;
    PORT
      LAYER M5 ;
        RECT  18.672 0 18.696 0.084 ;
    END
  END tw_d1[297]
  PIN tw_d1[298]
    DIRECTION INPUT ;
    USE SIGNAL ;
    PORT
      LAYER M5 ;
        RECT  18.768 0 18.792 0.084 ;
    END
  END tw_d1[298]
  PIN tw_d1[299]
    DIRECTION INPUT ;
    USE SIGNAL ;
    PORT
      LAYER M5 ;
        RECT  18.864 0 18.888 0.084 ;
    END
  END tw_d1[299]
  PIN tw_d1[29]
    DIRECTION INPUT ;
    USE SIGNAL ;
    PORT
      LAYER M5 ;
        RECT  43.632 0 43.656 0.084 ;
    END
  END tw_d1[29]
  PIN tw_d1[2]
    DIRECTION INPUT ;
    USE SIGNAL ;
    PORT
      LAYER M5 ;
        RECT  200.784 0 200.808 0.084 ;
    END
  END tw_d1[2]
  PIN tw_d1[300]
    DIRECTION INPUT ;
    USE SIGNAL ;
    PORT
      LAYER M5 ;
        RECT  18.96 0 18.984 0.084 ;
    END
  END tw_d1[300]
  PIN tw_d1[301]
    DIRECTION INPUT ;
    USE SIGNAL ;
    PORT
      LAYER M5 ;
        RECT  19.056 0 19.08 0.084 ;
    END
  END tw_d1[301]
  PIN tw_d1[302]
    DIRECTION INPUT ;
    USE SIGNAL ;
    PORT
      LAYER M5 ;
        RECT  6.864 0 6.888 0.084 ;
    END
  END tw_d1[302]
  PIN tw_d1[303]
    DIRECTION INPUT ;
    USE SIGNAL ;
    PORT
      LAYER M5 ;
        RECT  6.96 0 6.984 0.084 ;
    END
  END tw_d1[303]
  PIN tw_d1[304]
    DIRECTION INPUT ;
    USE SIGNAL ;
    PORT
      LAYER M5 ;
        RECT  7.056 0 7.08 0.084 ;
    END
  END tw_d1[304]
  PIN tw_d1[305]
    DIRECTION INPUT ;
    USE SIGNAL ;
    PORT
      LAYER M5 ;
        RECT  7.152 0 7.176 0.084 ;
    END
  END tw_d1[305]
  PIN tw_d1[306]
    DIRECTION INPUT ;
    USE SIGNAL ;
    PORT
      LAYER M5 ;
        RECT  7.248 0 7.272 0.084 ;
    END
  END tw_d1[306]
  PIN tw_d1[307]
    DIRECTION INPUT ;
    USE SIGNAL ;
    PORT
      LAYER M5 ;
        RECT  7.344 0 7.368 0.084 ;
    END
  END tw_d1[307]
  PIN tw_d1[308]
    DIRECTION INPUT ;
    USE SIGNAL ;
    PORT
      LAYER M5 ;
        RECT  7.44 0 7.464 0.084 ;
    END
  END tw_d1[308]
  PIN tw_d1[309]
    DIRECTION INPUT ;
    USE SIGNAL ;
    PORT
      LAYER M5 ;
        RECT  7.536 0 7.56 0.084 ;
    END
  END tw_d1[309]
  PIN tw_d1[30]
    DIRECTION INPUT ;
    USE SIGNAL ;
    PORT
      LAYER M5 ;
        RECT  43.728 0 43.752 0.084 ;
    END
  END tw_d1[30]
  PIN tw_d1[310]
    DIRECTION INPUT ;
    USE SIGNAL ;
    PORT
      LAYER M5 ;
        RECT  7.632 0 7.656 0.084 ;
    END
  END tw_d1[310]
  PIN tw_d1[311]
    DIRECTION INPUT ;
    USE SIGNAL ;
    PORT
      LAYER M5 ;
        RECT  7.728 0 7.752 0.084 ;
    END
  END tw_d1[311]
  PIN tw_d1[312]
    DIRECTION INPUT ;
    USE SIGNAL ;
    PORT
      LAYER M5 ;
        RECT  7.824 0 7.848 0.084 ;
    END
  END tw_d1[312]
  PIN tw_d1[313]
    DIRECTION INPUT ;
    USE SIGNAL ;
    PORT
      LAYER M5 ;
        RECT  7.92 0 7.944 0.084 ;
    END
  END tw_d1[313]
  PIN tw_d1[314]
    DIRECTION INPUT ;
    USE SIGNAL ;
    PORT
      LAYER M5 ;
        RECT  8.016 0 8.04 0.084 ;
    END
  END tw_d1[314]
  PIN tw_d1[315]
    DIRECTION INPUT ;
    USE SIGNAL ;
    PORT
      LAYER M5 ;
        RECT  8.112 0 8.136 0.084 ;
    END
  END tw_d1[315]
  PIN tw_d1[316]
    DIRECTION INPUT ;
    USE SIGNAL ;
    PORT
      LAYER M5 ;
        RECT  8.208 0 8.232 0.084 ;
    END
  END tw_d1[316]
  PIN tw_d1[317]
    DIRECTION INPUT ;
    USE SIGNAL ;
    PORT
      LAYER M5 ;
        RECT  8.304 0 8.328 0.084 ;
    END
  END tw_d1[317]
  PIN tw_d1[318]
    DIRECTION INPUT ;
    USE SIGNAL ;
    PORT
      LAYER M5 ;
        RECT  8.4 0 8.424 0.084 ;
    END
  END tw_d1[318]
  PIN tw_d1[319]
    DIRECTION INPUT ;
    USE SIGNAL ;
    PORT
      LAYER M5 ;
        RECT  8.496 0 8.52 0.084 ;
    END
  END tw_d1[319]
  PIN tw_d1[31]
    DIRECTION INPUT ;
    USE SIGNAL ;
    PORT
      LAYER M5 ;
        RECT  43.824 0 43.848 0.084 ;
    END
  END tw_d1[31]
  PIN tw_d1[320]
    DIRECTION INPUT ;
    USE SIGNAL ;
    PORT
      LAYER M5 ;
        RECT  8.592 0 8.616 0.084 ;
    END
  END tw_d1[320]
  PIN tw_d1[321]
    DIRECTION INPUT ;
    USE SIGNAL ;
    PORT
      LAYER M5 ;
        RECT  8.688 0 8.712 0.084 ;
    END
  END tw_d1[321]
  PIN tw_d1[322]
    DIRECTION INPUT ;
    USE SIGNAL ;
    PORT
      LAYER M5 ;
        RECT  8.784 0 8.808 0.084 ;
    END
  END tw_d1[322]
  PIN tw_d1[323]
    DIRECTION INPUT ;
    USE SIGNAL ;
    PORT
      LAYER M5 ;
        RECT  8.88 0 8.904 0.084 ;
    END
  END tw_d1[323]
  PIN tw_d1[324]
    DIRECTION INPUT ;
    USE SIGNAL ;
    PORT
      LAYER M5 ;
        RECT  8.976 0 9 0.084 ;
    END
  END tw_d1[324]
  PIN tw_d1[325]
    DIRECTION INPUT ;
    USE SIGNAL ;
    PORT
      LAYER M5 ;
        RECT  9.072 0 9.096 0.084 ;
    END
  END tw_d1[325]
  PIN tw_d1[326]
    DIRECTION INPUT ;
    USE SIGNAL ;
    PORT
      LAYER M5 ;
        RECT  9.168 0 9.192 0.084 ;
    END
  END tw_d1[326]
  PIN tw_d1[327]
    DIRECTION INPUT ;
    USE SIGNAL ;
    PORT
      LAYER M5 ;
        RECT  9.264 0 9.288 0.084 ;
    END
  END tw_d1[327]
  PIN tw_d1[328]
    DIRECTION INPUT ;
    USE SIGNAL ;
    PORT
      LAYER M5 ;
        RECT  9.36 0 9.384 0.084 ;
    END
  END tw_d1[328]
  PIN tw_d1[329]
    DIRECTION INPUT ;
    USE SIGNAL ;
    PORT
      LAYER M5 ;
        RECT  9.456 0 9.48 0.084 ;
    END
  END tw_d1[329]
  PIN tw_d1[32]
    DIRECTION INPUT ;
    USE SIGNAL ;
    PORT
      LAYER M5 ;
        RECT  43.92 0 43.944 0.084 ;
    END
  END tw_d1[32]
  PIN tw_d1[330]
    DIRECTION INPUT ;
    USE SIGNAL ;
    PORT
      LAYER M5 ;
        RECT  9.552 0 9.576 0.084 ;
    END
  END tw_d1[330]
  PIN tw_d1[331]
    DIRECTION INPUT ;
    USE SIGNAL ;
    PORT
      LAYER M5 ;
        RECT  9.648 0 9.672 0.084 ;
    END
  END tw_d1[331]
  PIN tw_d1[332]
    DIRECTION INPUT ;
    USE SIGNAL ;
    PORT
      LAYER M5 ;
        RECT  9.744 0 9.768 0.084 ;
    END
  END tw_d1[332]
  PIN tw_d1[333]
    DIRECTION INPUT ;
    USE SIGNAL ;
    PORT
      LAYER M5 ;
        RECT  9.84 0 9.864 0.084 ;
    END
  END tw_d1[333]
  PIN tw_d1[334]
    DIRECTION INPUT ;
    USE SIGNAL ;
    PORT
      LAYER M5 ;
        RECT  13.008 0 13.032 0.084 ;
    END
  END tw_d1[334]
  PIN tw_d1[335]
    DIRECTION INPUT ;
    USE SIGNAL ;
    PORT
      LAYER M5 ;
        RECT  13.104 0 13.128 0.084 ;
    END
  END tw_d1[335]
  PIN tw_d1[336]
    DIRECTION INPUT ;
    USE SIGNAL ;
    PORT
      LAYER M5 ;
        RECT  13.2 0 13.224 0.084 ;
    END
  END tw_d1[336]
  PIN tw_d1[337]
    DIRECTION INPUT ;
    USE SIGNAL ;
    PORT
      LAYER M5 ;
        RECT  13.296 0 13.32 0.084 ;
    END
  END tw_d1[337]
  PIN tw_d1[338]
    DIRECTION INPUT ;
    USE SIGNAL ;
    PORT
      LAYER M5 ;
        RECT  13.392 0 13.416 0.084 ;
    END
  END tw_d1[338]
  PIN tw_d1[339]
    DIRECTION INPUT ;
    USE SIGNAL ;
    PORT
      LAYER M5 ;
        RECT  13.488 0 13.512 0.084 ;
    END
  END tw_d1[339]
  PIN tw_d1[33]
    DIRECTION INPUT ;
    USE SIGNAL ;
    PORT
      LAYER M5 ;
        RECT  44.016 0 44.04 0.084 ;
    END
  END tw_d1[33]
  PIN tw_d1[340]
    DIRECTION INPUT ;
    USE SIGNAL ;
    PORT
      LAYER M5 ;
        RECT  13.584 0 13.608 0.084 ;
    END
  END tw_d1[340]
  PIN tw_d1[341]
    DIRECTION INPUT ;
    USE SIGNAL ;
    PORT
      LAYER M5 ;
        RECT  13.68 0 13.704 0.084 ;
    END
  END tw_d1[341]
  PIN tw_d1[342]
    DIRECTION INPUT ;
    USE SIGNAL ;
    PORT
      LAYER M5 ;
        RECT  13.776 0 13.8 0.084 ;
    END
  END tw_d1[342]
  PIN tw_d1[343]
    DIRECTION INPUT ;
    USE SIGNAL ;
    PORT
      LAYER M5 ;
        RECT  13.872 0 13.896 0.084 ;
    END
  END tw_d1[343]
  PIN tw_d1[344]
    DIRECTION INPUT ;
    USE SIGNAL ;
    PORT
      LAYER M5 ;
        RECT  13.968 0 13.992 0.084 ;
    END
  END tw_d1[344]
  PIN tw_d1[345]
    DIRECTION INPUT ;
    USE SIGNAL ;
    PORT
      LAYER M5 ;
        RECT  14.064 0 14.088 0.084 ;
    END
  END tw_d1[345]
  PIN tw_d1[346]
    DIRECTION INPUT ;
    USE SIGNAL ;
    PORT
      LAYER M5 ;
        RECT  14.16 0 14.184 0.084 ;
    END
  END tw_d1[346]
  PIN tw_d1[347]
    DIRECTION INPUT ;
    USE SIGNAL ;
    PORT
      LAYER M5 ;
        RECT  14.256 0 14.28 0.084 ;
    END
  END tw_d1[347]
  PIN tw_d1[348]
    DIRECTION INPUT ;
    USE SIGNAL ;
    PORT
      LAYER M5 ;
        RECT  14.352 0 14.376 0.084 ;
    END
  END tw_d1[348]
  PIN tw_d1[349]
    DIRECTION INPUT ;
    USE SIGNAL ;
    PORT
      LAYER M5 ;
        RECT  14.448 0 14.472 0.084 ;
    END
  END tw_d1[349]
  PIN tw_d1[34]
    DIRECTION INPUT ;
    USE SIGNAL ;
    PORT
      LAYER M5 ;
        RECT  44.112 0 44.136 0.084 ;
    END
  END tw_d1[34]
  PIN tw_d1[350]
    DIRECTION INPUT ;
    USE SIGNAL ;
    PORT
      LAYER M5 ;
        RECT  14.544 0 14.568 0.084 ;
    END
  END tw_d1[350]
  PIN tw_d1[351]
    DIRECTION INPUT ;
    USE SIGNAL ;
    PORT
      LAYER M5 ;
        RECT  14.64 0 14.664 0.084 ;
    END
  END tw_d1[351]
  PIN tw_d1[352]
    DIRECTION INPUT ;
    USE SIGNAL ;
    PORT
      LAYER M5 ;
        RECT  14.736 0 14.76 0.084 ;
    END
  END tw_d1[352]
  PIN tw_d1[353]
    DIRECTION INPUT ;
    USE SIGNAL ;
    PORT
      LAYER M5 ;
        RECT  14.832 0 14.856 0.084 ;
    END
  END tw_d1[353]
  PIN tw_d1[354]
    DIRECTION INPUT ;
    USE SIGNAL ;
    PORT
      LAYER M5 ;
        RECT  14.928 0 14.952 0.084 ;
    END
  END tw_d1[354]
  PIN tw_d1[355]
    DIRECTION INPUT ;
    USE SIGNAL ;
    PORT
      LAYER M5 ;
        RECT  15.024 0 15.048 0.084 ;
    END
  END tw_d1[355]
  PIN tw_d1[356]
    DIRECTION INPUT ;
    USE SIGNAL ;
    PORT
      LAYER M5 ;
        RECT  15.12 0 15.144 0.084 ;
    END
  END tw_d1[356]
  PIN tw_d1[357]
    DIRECTION INPUT ;
    USE SIGNAL ;
    PORT
      LAYER M5 ;
        RECT  15.216 0 15.24 0.084 ;
    END
  END tw_d1[357]
  PIN tw_d1[358]
    DIRECTION INPUT ;
    USE SIGNAL ;
    PORT
      LAYER M5 ;
        RECT  15.312 0 15.336 0.084 ;
    END
  END tw_d1[358]
  PIN tw_d1[359]
    DIRECTION INPUT ;
    USE SIGNAL ;
    PORT
      LAYER M5 ;
        RECT  15.408 0 15.432 0.084 ;
    END
  END tw_d1[359]
  PIN tw_d1[35]
    DIRECTION INPUT ;
    USE SIGNAL ;
    PORT
      LAYER M5 ;
        RECT  44.208 0 44.232 0.084 ;
    END
  END tw_d1[35]
  PIN tw_d1[360]
    DIRECTION INPUT ;
    USE SIGNAL ;
    PORT
      LAYER M5 ;
        RECT  15.504 0 15.528 0.084 ;
    END
  END tw_d1[360]
  PIN tw_d1[361]
    DIRECTION INPUT ;
    USE SIGNAL ;
    PORT
      LAYER M5 ;
        RECT  15.6 0 15.624 0.084 ;
    END
  END tw_d1[361]
  PIN tw_d1[362]
    DIRECTION INPUT ;
    USE SIGNAL ;
    PORT
      LAYER M5 ;
        RECT  15.696 0 15.72 0.084 ;
    END
  END tw_d1[362]
  PIN tw_d1[363]
    DIRECTION INPUT ;
    USE SIGNAL ;
    PORT
      LAYER M5 ;
        RECT  15.792 0 15.816 0.084 ;
    END
  END tw_d1[363]
  PIN tw_d1[364]
    DIRECTION INPUT ;
    USE SIGNAL ;
    PORT
      LAYER M5 ;
        RECT  15.888 0 15.912 0.084 ;
    END
  END tw_d1[364]
  PIN tw_d1[365]
    DIRECTION INPUT ;
    USE SIGNAL ;
    PORT
      LAYER M5 ;
        RECT  15.984 0 16.008 0.084 ;
    END
  END tw_d1[365]
  PIN tw_d1[366]
    DIRECTION INPUT ;
    USE SIGNAL ;
    PORT
      LAYER M5 ;
        RECT  58.32 0 58.344 0.084 ;
    END
  END tw_d1[366]
  PIN tw_d1[367]
    DIRECTION INPUT ;
    USE SIGNAL ;
    PORT
      LAYER M5 ;
        RECT  58.416 0 58.44 0.084 ;
    END
  END tw_d1[367]
  PIN tw_d1[368]
    DIRECTION INPUT ;
    USE SIGNAL ;
    PORT
      LAYER M5 ;
        RECT  58.512 0 58.536 0.084 ;
    END
  END tw_d1[368]
  PIN tw_d1[369]
    DIRECTION INPUT ;
    USE SIGNAL ;
    PORT
      LAYER M5 ;
        RECT  58.608 0 58.632 0.084 ;
    END
  END tw_d1[369]
  PIN tw_d1[36]
    DIRECTION INPUT ;
    USE SIGNAL ;
    PORT
      LAYER M5 ;
        RECT  44.304 0 44.328 0.084 ;
    END
  END tw_d1[36]
  PIN tw_d1[370]
    DIRECTION INPUT ;
    USE SIGNAL ;
    PORT
      LAYER M5 ;
        RECT  58.704 0 58.728 0.084 ;
    END
  END tw_d1[370]
  PIN tw_d1[371]
    DIRECTION INPUT ;
    USE SIGNAL ;
    PORT
      LAYER M5 ;
        RECT  58.8 0 58.824 0.084 ;
    END
  END tw_d1[371]
  PIN tw_d1[372]
    DIRECTION INPUT ;
    USE SIGNAL ;
    PORT
      LAYER M5 ;
        RECT  58.896 0 58.92 0.084 ;
    END
  END tw_d1[372]
  PIN tw_d1[373]
    DIRECTION INPUT ;
    USE SIGNAL ;
    PORT
      LAYER M5 ;
        RECT  58.992 0 59.016 0.084 ;
    END
  END tw_d1[373]
  PIN tw_d1[374]
    DIRECTION INPUT ;
    USE SIGNAL ;
    PORT
      LAYER M5 ;
        RECT  59.088 0 59.112 0.084 ;
    END
  END tw_d1[374]
  PIN tw_d1[375]
    DIRECTION INPUT ;
    USE SIGNAL ;
    PORT
      LAYER M5 ;
        RECT  59.184 0 59.208 0.084 ;
    END
  END tw_d1[375]
  PIN tw_d1[376]
    DIRECTION INPUT ;
    USE SIGNAL ;
    PORT
      LAYER M5 ;
        RECT  59.28 0 59.304 0.084 ;
    END
  END tw_d1[376]
  PIN tw_d1[377]
    DIRECTION INPUT ;
    USE SIGNAL ;
    PORT
      LAYER M5 ;
        RECT  59.376 0 59.4 0.084 ;
    END
  END tw_d1[377]
  PIN tw_d1[378]
    DIRECTION INPUT ;
    USE SIGNAL ;
    PORT
      LAYER M5 ;
        RECT  59.472 0 59.496 0.084 ;
    END
  END tw_d1[378]
  PIN tw_d1[379]
    DIRECTION INPUT ;
    USE SIGNAL ;
    PORT
      LAYER M5 ;
        RECT  59.568 0 59.592 0.084 ;
    END
  END tw_d1[379]
  PIN tw_d1[37]
    DIRECTION INPUT ;
    USE SIGNAL ;
    PORT
      LAYER M5 ;
        RECT  44.4 0 44.424 0.084 ;
    END
  END tw_d1[37]
  PIN tw_d1[380]
    DIRECTION INPUT ;
    USE SIGNAL ;
    PORT
      LAYER M5 ;
        RECT  59.664 0 59.688 0.084 ;
    END
  END tw_d1[380]
  PIN tw_d1[381]
    DIRECTION INPUT ;
    USE SIGNAL ;
    PORT
      LAYER M5 ;
        RECT  59.76 0 59.784 0.084 ;
    END
  END tw_d1[381]
  PIN tw_d1[382]
    DIRECTION INPUT ;
    USE SIGNAL ;
    PORT
      LAYER M5 ;
        RECT  59.856 0 59.88 0.084 ;
    END
  END tw_d1[382]
  PIN tw_d1[383]
    DIRECTION INPUT ;
    USE SIGNAL ;
    PORT
      LAYER M5 ;
        RECT  59.952 0 59.976 0.084 ;
    END
  END tw_d1[383]
  PIN tw_d1[384]
    DIRECTION INPUT ;
    USE SIGNAL ;
    PORT
      LAYER M5 ;
        RECT  60.048 0 60.072 0.084 ;
    END
  END tw_d1[384]
  PIN tw_d1[385]
    DIRECTION INPUT ;
    USE SIGNAL ;
    PORT
      LAYER M5 ;
        RECT  60.144 0 60.168 0.084 ;
    END
  END tw_d1[385]
  PIN tw_d1[386]
    DIRECTION INPUT ;
    USE SIGNAL ;
    PORT
      LAYER M5 ;
        RECT  60.24 0 60.264 0.084 ;
    END
  END tw_d1[386]
  PIN tw_d1[387]
    DIRECTION INPUT ;
    USE SIGNAL ;
    PORT
      LAYER M5 ;
        RECT  60.336 0 60.36 0.084 ;
    END
  END tw_d1[387]
  PIN tw_d1[388]
    DIRECTION INPUT ;
    USE SIGNAL ;
    PORT
      LAYER M5 ;
        RECT  60.432 0 60.456 0.084 ;
    END
  END tw_d1[388]
  PIN tw_d1[389]
    DIRECTION INPUT ;
    USE SIGNAL ;
    PORT
      LAYER M5 ;
        RECT  60.528 0 60.552 0.084 ;
    END
  END tw_d1[389]
  PIN tw_d1[38]
    DIRECTION INPUT ;
    USE SIGNAL ;
    PORT
      LAYER M5 ;
        RECT  44.496 0 44.52 0.084 ;
    END
  END tw_d1[38]
  PIN tw_d1[390]
    DIRECTION INPUT ;
    USE SIGNAL ;
    PORT
      LAYER M5 ;
        RECT  60.624 0 60.648 0.084 ;
    END
  END tw_d1[390]
  PIN tw_d1[391]
    DIRECTION INPUT ;
    USE SIGNAL ;
    PORT
      LAYER M5 ;
        RECT  60.72 0 60.744 0.084 ;
    END
  END tw_d1[391]
  PIN tw_d1[392]
    DIRECTION INPUT ;
    USE SIGNAL ;
    PORT
      LAYER M5 ;
        RECT  60.816 0 60.84 0.084 ;
    END
  END tw_d1[392]
  PIN tw_d1[393]
    DIRECTION INPUT ;
    USE SIGNAL ;
    PORT
      LAYER M5 ;
        RECT  60.912 0 60.936 0.084 ;
    END
  END tw_d1[393]
  PIN tw_d1[394]
    DIRECTION INPUT ;
    USE SIGNAL ;
    PORT
      LAYER M5 ;
        RECT  61.008 0 61.032 0.084 ;
    END
  END tw_d1[394]
  PIN tw_d1[395]
    DIRECTION INPUT ;
    USE SIGNAL ;
    PORT
      LAYER M5 ;
        RECT  61.104 0 61.128 0.084 ;
    END
  END tw_d1[395]
  PIN tw_d1[396]
    DIRECTION INPUT ;
    USE SIGNAL ;
    PORT
      LAYER M5 ;
        RECT  61.2 0 61.224 0.084 ;
    END
  END tw_d1[396]
  PIN tw_d1[397]
    DIRECTION INPUT ;
    USE SIGNAL ;
    PORT
      LAYER M5 ;
        RECT  61.296 0 61.32 0.084 ;
    END
  END tw_d1[397]
  PIN tw_d1[398]
    DIRECTION INPUT ;
    USE SIGNAL ;
    PORT
      LAYER M5 ;
        RECT  205.008 0 205.032 0.084 ;
    END
  END tw_d1[398]
  PIN tw_d1[399]
    DIRECTION INPUT ;
    USE SIGNAL ;
    PORT
      LAYER M5 ;
        RECT  205.104 0 205.128 0.084 ;
    END
  END tw_d1[399]
  PIN tw_d1[39]
    DIRECTION INPUT ;
    USE SIGNAL ;
    PORT
      LAYER M5 ;
        RECT  44.592 0 44.616 0.084 ;
    END
  END tw_d1[39]
  PIN tw_d1[3]
    DIRECTION INPUT ;
    USE SIGNAL ;
    PORT
      LAYER M5 ;
        RECT  200.88 0 200.904 0.084 ;
    END
  END tw_d1[3]
  PIN tw_d1[400]
    DIRECTION INPUT ;
    USE SIGNAL ;
    PORT
      LAYER M5 ;
        RECT  205.2 0 205.224 0.084 ;
    END
  END tw_d1[400]
  PIN tw_d1[401]
    DIRECTION INPUT ;
    USE SIGNAL ;
    PORT
      LAYER M5 ;
        RECT  205.296 0 205.32 0.084 ;
    END
  END tw_d1[401]
  PIN tw_d1[402]
    DIRECTION INPUT ;
    USE SIGNAL ;
    PORT
      LAYER M5 ;
        RECT  205.392 0 205.416 0.084 ;
    END
  END tw_d1[402]
  PIN tw_d1[403]
    DIRECTION INPUT ;
    USE SIGNAL ;
    PORT
      LAYER M5 ;
        RECT  205.488 0 205.512 0.084 ;
    END
  END tw_d1[403]
  PIN tw_d1[404]
    DIRECTION INPUT ;
    USE SIGNAL ;
    PORT
      LAYER M5 ;
        RECT  205.584 0 205.608 0.084 ;
    END
  END tw_d1[404]
  PIN tw_d1[405]
    DIRECTION INPUT ;
    USE SIGNAL ;
    PORT
      LAYER M5 ;
        RECT  205.68 0 205.704 0.084 ;
    END
  END tw_d1[405]
  PIN tw_d1[406]
    DIRECTION INPUT ;
    USE SIGNAL ;
    PORT
      LAYER M5 ;
        RECT  205.776 0 205.8 0.084 ;
    END
  END tw_d1[406]
  PIN tw_d1[407]
    DIRECTION INPUT ;
    USE SIGNAL ;
    PORT
      LAYER M5 ;
        RECT  205.872 0 205.896 0.084 ;
    END
  END tw_d1[407]
  PIN tw_d1[408]
    DIRECTION INPUT ;
    USE SIGNAL ;
    PORT
      LAYER M5 ;
        RECT  205.968 0 205.992 0.084 ;
    END
  END tw_d1[408]
  PIN tw_d1[409]
    DIRECTION INPUT ;
    USE SIGNAL ;
    PORT
      LAYER M5 ;
        RECT  206.064 0 206.088 0.084 ;
    END
  END tw_d1[409]
  PIN tw_d1[40]
    DIRECTION INPUT ;
    USE SIGNAL ;
    PORT
      LAYER M5 ;
        RECT  44.688 0 44.712 0.084 ;
    END
  END tw_d1[40]
  PIN tw_d1[410]
    DIRECTION INPUT ;
    USE SIGNAL ;
    PORT
      LAYER M5 ;
        RECT  206.16 0 206.184 0.084 ;
    END
  END tw_d1[410]
  PIN tw_d1[411]
    DIRECTION INPUT ;
    USE SIGNAL ;
    PORT
      LAYER M5 ;
        RECT  206.256 0 206.28 0.084 ;
    END
  END tw_d1[411]
  PIN tw_d1[412]
    DIRECTION INPUT ;
    USE SIGNAL ;
    PORT
      LAYER M5 ;
        RECT  206.352 0 206.376 0.084 ;
    END
  END tw_d1[412]
  PIN tw_d1[413]
    DIRECTION INPUT ;
    USE SIGNAL ;
    PORT
      LAYER M5 ;
        RECT  206.448 0 206.472 0.084 ;
    END
  END tw_d1[413]
  PIN tw_d1[414]
    DIRECTION INPUT ;
    USE SIGNAL ;
    PORT
      LAYER M5 ;
        RECT  206.544 0 206.568 0.084 ;
    END
  END tw_d1[414]
  PIN tw_d1[415]
    DIRECTION INPUT ;
    USE SIGNAL ;
    PORT
      LAYER M5 ;
        RECT  206.64 0 206.664 0.084 ;
    END
  END tw_d1[415]
  PIN tw_d1[416]
    DIRECTION INPUT ;
    USE SIGNAL ;
    PORT
      LAYER M5 ;
        RECT  206.736 0 206.76 0.084 ;
    END
  END tw_d1[416]
  PIN tw_d1[417]
    DIRECTION INPUT ;
    USE SIGNAL ;
    PORT
      LAYER M5 ;
        RECT  206.832 0 206.856 0.084 ;
    END
  END tw_d1[417]
  PIN tw_d1[418]
    DIRECTION INPUT ;
    USE SIGNAL ;
    PORT
      LAYER M5 ;
        RECT  206.928 0 206.952 0.084 ;
    END
  END tw_d1[418]
  PIN tw_d1[419]
    DIRECTION INPUT ;
    USE SIGNAL ;
    PORT
      LAYER M5 ;
        RECT  207.024 0 207.048 0.084 ;
    END
  END tw_d1[419]
  PIN tw_d1[41]
    DIRECTION INPUT ;
    USE SIGNAL ;
    PORT
      LAYER M5 ;
        RECT  44.784 0 44.808 0.084 ;
    END
  END tw_d1[41]
  PIN tw_d1[420]
    DIRECTION INPUT ;
    USE SIGNAL ;
    PORT
      LAYER M5 ;
        RECT  207.12 0 207.144 0.084 ;
    END
  END tw_d1[420]
  PIN tw_d1[421]
    DIRECTION INPUT ;
    USE SIGNAL ;
    PORT
      LAYER M5 ;
        RECT  207.216 0 207.24 0.084 ;
    END
  END tw_d1[421]
  PIN tw_d1[422]
    DIRECTION INPUT ;
    USE SIGNAL ;
    PORT
      LAYER M5 ;
        RECT  207.312 0 207.336 0.084 ;
    END
  END tw_d1[422]
  PIN tw_d1[423]
    DIRECTION INPUT ;
    USE SIGNAL ;
    PORT
      LAYER M5 ;
        RECT  207.408 0 207.432 0.084 ;
    END
  END tw_d1[423]
  PIN tw_d1[424]
    DIRECTION INPUT ;
    USE SIGNAL ;
    PORT
      LAYER M5 ;
        RECT  207.504 0 207.528 0.084 ;
    END
  END tw_d1[424]
  PIN tw_d1[425]
    DIRECTION INPUT ;
    USE SIGNAL ;
    PORT
      LAYER M5 ;
        RECT  207.6 0 207.624 0.084 ;
    END
  END tw_d1[425]
  PIN tw_d1[426]
    DIRECTION INPUT ;
    USE SIGNAL ;
    PORT
      LAYER M5 ;
        RECT  207.696 0 207.72 0.084 ;
    END
  END tw_d1[426]
  PIN tw_d1[427]
    DIRECTION INPUT ;
    USE SIGNAL ;
    PORT
      LAYER M5 ;
        RECT  207.792 0 207.816 0.084 ;
    END
  END tw_d1[427]
  PIN tw_d1[428]
    DIRECTION INPUT ;
    USE SIGNAL ;
    PORT
      LAYER M5 ;
        RECT  207.888 0 207.912 0.084 ;
    END
  END tw_d1[428]
  PIN tw_d1[429]
    DIRECTION INPUT ;
    USE SIGNAL ;
    PORT
      LAYER M5 ;
        RECT  207.984 0 208.008 0.084 ;
    END
  END tw_d1[429]
  PIN tw_d1[42]
    DIRECTION INPUT ;
    USE SIGNAL ;
    PORT
      LAYER M5 ;
        RECT  44.88 0 44.904 0.084 ;
    END
  END tw_d1[42]
  PIN tw_d1[430]
    DIRECTION INPUT ;
    USE SIGNAL ;
    PORT
      LAYER M5 ;
        RECT  201.936 0 201.96 0.084 ;
    END
  END tw_d1[430]
  PIN tw_d1[431]
    DIRECTION INPUT ;
    USE SIGNAL ;
    PORT
      LAYER M5 ;
        RECT  202.032 0 202.056 0.084 ;
    END
  END tw_d1[431]
  PIN tw_d1[432]
    DIRECTION INPUT ;
    USE SIGNAL ;
    PORT
      LAYER M5 ;
        RECT  202.128 0 202.152 0.084 ;
    END
  END tw_d1[432]
  PIN tw_d1[433]
    DIRECTION INPUT ;
    USE SIGNAL ;
    PORT
      LAYER M5 ;
        RECT  202.224 0 202.248 0.084 ;
    END
  END tw_d1[433]
  PIN tw_d1[434]
    DIRECTION INPUT ;
    USE SIGNAL ;
    PORT
      LAYER M5 ;
        RECT  202.32 0 202.344 0.084 ;
    END
  END tw_d1[434]
  PIN tw_d1[435]
    DIRECTION INPUT ;
    USE SIGNAL ;
    PORT
      LAYER M5 ;
        RECT  202.416 0 202.44 0.084 ;
    END
  END tw_d1[435]
  PIN tw_d1[436]
    DIRECTION INPUT ;
    USE SIGNAL ;
    PORT
      LAYER M5 ;
        RECT  202.512 0 202.536 0.084 ;
    END
  END tw_d1[436]
  PIN tw_d1[437]
    DIRECTION INPUT ;
    USE SIGNAL ;
    PORT
      LAYER M5 ;
        RECT  202.608 0 202.632 0.084 ;
    END
  END tw_d1[437]
  PIN tw_d1[438]
    DIRECTION INPUT ;
    USE SIGNAL ;
    PORT
      LAYER M5 ;
        RECT  202.704 0 202.728 0.084 ;
    END
  END tw_d1[438]
  PIN tw_d1[439]
    DIRECTION INPUT ;
    USE SIGNAL ;
    PORT
      LAYER M5 ;
        RECT  202.8 0 202.824 0.084 ;
    END
  END tw_d1[439]
  PIN tw_d1[43]
    DIRECTION INPUT ;
    USE SIGNAL ;
    PORT
      LAYER M5 ;
        RECT  44.976 0 45 0.084 ;
    END
  END tw_d1[43]
  PIN tw_d1[440]
    DIRECTION INPUT ;
    USE SIGNAL ;
    PORT
      LAYER M5 ;
        RECT  202.896 0 202.92 0.084 ;
    END
  END tw_d1[440]
  PIN tw_d1[441]
    DIRECTION INPUT ;
    USE SIGNAL ;
    PORT
      LAYER M5 ;
        RECT  202.992 0 203.016 0.084 ;
    END
  END tw_d1[441]
  PIN tw_d1[442]
    DIRECTION INPUT ;
    USE SIGNAL ;
    PORT
      LAYER M5 ;
        RECT  203.088 0 203.112 0.084 ;
    END
  END tw_d1[442]
  PIN tw_d1[443]
    DIRECTION INPUT ;
    USE SIGNAL ;
    PORT
      LAYER M5 ;
        RECT  203.184 0 203.208 0.084 ;
    END
  END tw_d1[443]
  PIN tw_d1[444]
    DIRECTION INPUT ;
    USE SIGNAL ;
    PORT
      LAYER M5 ;
        RECT  203.28 0 203.304 0.084 ;
    END
  END tw_d1[444]
  PIN tw_d1[445]
    DIRECTION INPUT ;
    USE SIGNAL ;
    PORT
      LAYER M5 ;
        RECT  203.376 0 203.4 0.084 ;
    END
  END tw_d1[445]
  PIN tw_d1[446]
    DIRECTION INPUT ;
    USE SIGNAL ;
    PORT
      LAYER M5 ;
        RECT  203.472 0 203.496 0.084 ;
    END
  END tw_d1[446]
  PIN tw_d1[447]
    DIRECTION INPUT ;
    USE SIGNAL ;
    PORT
      LAYER M5 ;
        RECT  203.568 0 203.592 0.084 ;
    END
  END tw_d1[447]
  PIN tw_d1[448]
    DIRECTION INPUT ;
    USE SIGNAL ;
    PORT
      LAYER M5 ;
        RECT  203.664 0 203.688 0.084 ;
    END
  END tw_d1[448]
  PIN tw_d1[449]
    DIRECTION INPUT ;
    USE SIGNAL ;
    PORT
      LAYER M5 ;
        RECT  203.76 0 203.784 0.084 ;
    END
  END tw_d1[449]
  PIN tw_d1[44]
    DIRECTION INPUT ;
    USE SIGNAL ;
    PORT
      LAYER M5 ;
        RECT  45.072 0 45.096 0.084 ;
    END
  END tw_d1[44]
  PIN tw_d1[450]
    DIRECTION INPUT ;
    USE SIGNAL ;
    PORT
      LAYER M5 ;
        RECT  203.856 0 203.88 0.084 ;
    END
  END tw_d1[450]
  PIN tw_d1[451]
    DIRECTION INPUT ;
    USE SIGNAL ;
    PORT
      LAYER M5 ;
        RECT  203.952 0 203.976 0.084 ;
    END
  END tw_d1[451]
  PIN tw_d1[452]
    DIRECTION INPUT ;
    USE SIGNAL ;
    PORT
      LAYER M5 ;
        RECT  204.048 0 204.072 0.084 ;
    END
  END tw_d1[452]
  PIN tw_d1[453]
    DIRECTION INPUT ;
    USE SIGNAL ;
    PORT
      LAYER M5 ;
        RECT  204.144 0 204.168 0.084 ;
    END
  END tw_d1[453]
  PIN tw_d1[454]
    DIRECTION INPUT ;
    USE SIGNAL ;
    PORT
      LAYER M5 ;
        RECT  204.24 0 204.264 0.084 ;
    END
  END tw_d1[454]
  PIN tw_d1[455]
    DIRECTION INPUT ;
    USE SIGNAL ;
    PORT
      LAYER M5 ;
        RECT  204.336 0 204.36 0.084 ;
    END
  END tw_d1[455]
  PIN tw_d1[456]
    DIRECTION INPUT ;
    USE SIGNAL ;
    PORT
      LAYER M5 ;
        RECT  204.432 0 204.456 0.084 ;
    END
  END tw_d1[456]
  PIN tw_d1[45]
    DIRECTION INPUT ;
    USE SIGNAL ;
    PORT
      LAYER M5 ;
        RECT  45.168 0 45.192 0.084 ;
    END
  END tw_d1[45]
  PIN tw_d1[46]
    DIRECTION INPUT ;
    USE SIGNAL ;
    PORT
      LAYER M5 ;
        RECT  39.12 0 39.144 0.084 ;
    END
  END tw_d1[46]
  PIN tw_d1[47]
    DIRECTION INPUT ;
    USE SIGNAL ;
    PORT
      LAYER M5 ;
        RECT  39.216 0 39.24 0.084 ;
    END
  END tw_d1[47]
  PIN tw_d1[48]
    DIRECTION INPUT ;
    USE SIGNAL ;
    PORT
      LAYER M5 ;
        RECT  39.312 0 39.336 0.084 ;
    END
  END tw_d1[48]
  PIN tw_d1[49]
    DIRECTION INPUT ;
    USE SIGNAL ;
    PORT
      LAYER M5 ;
        RECT  39.408 0 39.432 0.084 ;
    END
  END tw_d1[49]
  PIN tw_d1[4]
    DIRECTION INPUT ;
    USE SIGNAL ;
    PORT
      LAYER M5 ;
        RECT  200.976 0 201 0.084 ;
    END
  END tw_d1[4]
  PIN tw_d1[50]
    DIRECTION INPUT ;
    USE SIGNAL ;
    PORT
      LAYER M5 ;
        RECT  39.504 0 39.528 0.084 ;
    END
  END tw_d1[50]
  PIN tw_d1[51]
    DIRECTION INPUT ;
    USE SIGNAL ;
    PORT
      LAYER M5 ;
        RECT  39.6 0 39.624 0.084 ;
    END
  END tw_d1[51]
  PIN tw_d1[52]
    DIRECTION INPUT ;
    USE SIGNAL ;
    PORT
      LAYER M5 ;
        RECT  39.696 0 39.72 0.084 ;
    END
  END tw_d1[52]
  PIN tw_d1[53]
    DIRECTION INPUT ;
    USE SIGNAL ;
    PORT
      LAYER M5 ;
        RECT  39.792 0 39.816 0.084 ;
    END
  END tw_d1[53]
  PIN tw_d1[54]
    DIRECTION INPUT ;
    USE SIGNAL ;
    PORT
      LAYER M5 ;
        RECT  39.888 0 39.912 0.084 ;
    END
  END tw_d1[54]
  PIN tw_d1[55]
    DIRECTION INPUT ;
    USE SIGNAL ;
    PORT
      LAYER M5 ;
        RECT  39.984 0 40.008 0.084 ;
    END
  END tw_d1[55]
  PIN tw_d1[56]
    DIRECTION INPUT ;
    USE SIGNAL ;
    PORT
      LAYER M5 ;
        RECT  40.08 0 40.104 0.084 ;
    END
  END tw_d1[56]
  PIN tw_d1[57]
    DIRECTION INPUT ;
    USE SIGNAL ;
    PORT
      LAYER M5 ;
        RECT  40.176 0 40.2 0.084 ;
    END
  END tw_d1[57]
  PIN tw_d1[58]
    DIRECTION INPUT ;
    USE SIGNAL ;
    PORT
      LAYER M5 ;
        RECT  40.272 0 40.296 0.084 ;
    END
  END tw_d1[58]
  PIN tw_d1[59]
    DIRECTION INPUT ;
    USE SIGNAL ;
    PORT
      LAYER M5 ;
        RECT  40.368 0 40.392 0.084 ;
    END
  END tw_d1[59]
  PIN tw_d1[5]
    DIRECTION INPUT ;
    USE SIGNAL ;
    PORT
      LAYER M5 ;
        RECT  201.072 0 201.096 0.084 ;
    END
  END tw_d1[5]
  PIN tw_d1[60]
    DIRECTION INPUT ;
    USE SIGNAL ;
    PORT
      LAYER M5 ;
        RECT  40.464 0 40.488 0.084 ;
    END
  END tw_d1[60]
  PIN tw_d1[61]
    DIRECTION INPUT ;
    USE SIGNAL ;
    PORT
      LAYER M5 ;
        RECT  40.56 0 40.584 0.084 ;
    END
  END tw_d1[61]
  PIN tw_d1[62]
    DIRECTION INPUT ;
    USE SIGNAL ;
    PORT
      LAYER M5 ;
        RECT  40.656 0 40.68 0.084 ;
    END
  END tw_d1[62]
  PIN tw_d1[63]
    DIRECTION INPUT ;
    USE SIGNAL ;
    PORT
      LAYER M5 ;
        RECT  40.752 0 40.776 0.084 ;
    END
  END tw_d1[63]
  PIN tw_d1[64]
    DIRECTION INPUT ;
    USE SIGNAL ;
    PORT
      LAYER M5 ;
        RECT  40.848 0 40.872 0.084 ;
    END
  END tw_d1[64]
  PIN tw_d1[65]
    DIRECTION INPUT ;
    USE SIGNAL ;
    PORT
      LAYER M5 ;
        RECT  40.944 0 40.968 0.084 ;
    END
  END tw_d1[65]
  PIN tw_d1[66]
    DIRECTION INPUT ;
    USE SIGNAL ;
    PORT
      LAYER M5 ;
        RECT  41.04 0 41.064 0.084 ;
    END
  END tw_d1[66]
  PIN tw_d1[67]
    DIRECTION INPUT ;
    USE SIGNAL ;
    PORT
      LAYER M5 ;
        RECT  41.136 0 41.16 0.084 ;
    END
  END tw_d1[67]
  PIN tw_d1[68]
    DIRECTION INPUT ;
    USE SIGNAL ;
    PORT
      LAYER M5 ;
        RECT  41.232 0 41.256 0.084 ;
    END
  END tw_d1[68]
  PIN tw_d1[69]
    DIRECTION INPUT ;
    USE SIGNAL ;
    PORT
      LAYER M5 ;
        RECT  41.328 0 41.352 0.084 ;
    END
  END tw_d1[69]
  PIN tw_d1[6]
    DIRECTION INPUT ;
    USE SIGNAL ;
    PORT
      LAYER M5 ;
        RECT  201.168 0 201.192 0.084 ;
    END
  END tw_d1[6]
  PIN tw_d1[70]
    DIRECTION INPUT ;
    USE SIGNAL ;
    PORT
      LAYER M5 ;
        RECT  41.424 0 41.448 0.084 ;
    END
  END tw_d1[70]
  PIN tw_d1[71]
    DIRECTION INPUT ;
    USE SIGNAL ;
    PORT
      LAYER M5 ;
        RECT  41.52 0 41.544 0.084 ;
    END
  END tw_d1[71]
  PIN tw_d1[72]
    DIRECTION INPUT ;
    USE SIGNAL ;
    PORT
      LAYER M5 ;
        RECT  41.616 0 41.64 0.084 ;
    END
  END tw_d1[72]
  PIN tw_d1[73]
    DIRECTION INPUT ;
    USE SIGNAL ;
    PORT
      LAYER M5 ;
        RECT  41.712 0 41.736 0.084 ;
    END
  END tw_d1[73]
  PIN tw_d1[74]
    DIRECTION INPUT ;
    USE SIGNAL ;
    PORT
      LAYER M5 ;
        RECT  41.808 0 41.832 0.084 ;
    END
  END tw_d1[74]
  PIN tw_d1[75]
    DIRECTION INPUT ;
    USE SIGNAL ;
    PORT
      LAYER M5 ;
        RECT  41.904 0 41.928 0.084 ;
    END
  END tw_d1[75]
  PIN tw_d1[76]
    DIRECTION INPUT ;
    USE SIGNAL ;
    PORT
      LAYER M5 ;
        RECT  42 0 42.024 0.084 ;
    END
  END tw_d1[76]
  PIN tw_d1[77]
    DIRECTION INPUT ;
    USE SIGNAL ;
    PORT
      LAYER M5 ;
        RECT  42.096 0 42.12 0.084 ;
    END
  END tw_d1[77]
  PIN tw_d1[78]
    DIRECTION INPUT ;
    USE SIGNAL ;
    PORT
      LAYER M5 ;
        RECT  9.936 0 9.96 0.084 ;
    END
  END tw_d1[78]
  PIN tw_d1[79]
    DIRECTION INPUT ;
    USE SIGNAL ;
    PORT
      LAYER M5 ;
        RECT  10.032 0 10.056 0.084 ;
    END
  END tw_d1[79]
  PIN tw_d1[7]
    DIRECTION INPUT ;
    USE SIGNAL ;
    PORT
      LAYER M5 ;
        RECT  201.264 0 201.288 0.084 ;
    END
  END tw_d1[7]
  PIN tw_d1[80]
    DIRECTION INPUT ;
    USE SIGNAL ;
    PORT
      LAYER M5 ;
        RECT  10.128 0 10.152 0.084 ;
    END
  END tw_d1[80]
  PIN tw_d1[81]
    DIRECTION INPUT ;
    USE SIGNAL ;
    PORT
      LAYER M5 ;
        RECT  10.224 0 10.248 0.084 ;
    END
  END tw_d1[81]
  PIN tw_d1[82]
    DIRECTION INPUT ;
    USE SIGNAL ;
    PORT
      LAYER M5 ;
        RECT  10.32 0 10.344 0.084 ;
    END
  END tw_d1[82]
  PIN tw_d1[83]
    DIRECTION INPUT ;
    USE SIGNAL ;
    PORT
      LAYER M5 ;
        RECT  10.416 0 10.44 0.084 ;
    END
  END tw_d1[83]
  PIN tw_d1[84]
    DIRECTION INPUT ;
    USE SIGNAL ;
    PORT
      LAYER M5 ;
        RECT  10.512 0 10.536 0.084 ;
    END
  END tw_d1[84]
  PIN tw_d1[85]
    DIRECTION INPUT ;
    USE SIGNAL ;
    PORT
      LAYER M5 ;
        RECT  10.608 0 10.632 0.084 ;
    END
  END tw_d1[85]
  PIN tw_d1[86]
    DIRECTION INPUT ;
    USE SIGNAL ;
    PORT
      LAYER M5 ;
        RECT  10.704 0 10.728 0.084 ;
    END
  END tw_d1[86]
  PIN tw_d1[87]
    DIRECTION INPUT ;
    USE SIGNAL ;
    PORT
      LAYER M5 ;
        RECT  10.8 0 10.824 0.084 ;
    END
  END tw_d1[87]
  PIN tw_d1[88]
    DIRECTION INPUT ;
    USE SIGNAL ;
    PORT
      LAYER M5 ;
        RECT  10.896 0 10.92 0.084 ;
    END
  END tw_d1[88]
  PIN tw_d1[89]
    DIRECTION INPUT ;
    USE SIGNAL ;
    PORT
      LAYER M5 ;
        RECT  10.992 0 11.016 0.084 ;
    END
  END tw_d1[89]
  PIN tw_d1[8]
    DIRECTION INPUT ;
    USE SIGNAL ;
    PORT
      LAYER M5 ;
        RECT  201.36 0 201.384 0.084 ;
    END
  END tw_d1[8]
  PIN tw_d1[90]
    DIRECTION INPUT ;
    USE SIGNAL ;
    PORT
      LAYER M5 ;
        RECT  11.088 0 11.112 0.084 ;
    END
  END tw_d1[90]
  PIN tw_d1[91]
    DIRECTION INPUT ;
    USE SIGNAL ;
    PORT
      LAYER M5 ;
        RECT  11.184 0 11.208 0.084 ;
    END
  END tw_d1[91]
  PIN tw_d1[92]
    DIRECTION INPUT ;
    USE SIGNAL ;
    PORT
      LAYER M5 ;
        RECT  11.28 0 11.304 0.084 ;
    END
  END tw_d1[92]
  PIN tw_d1[93]
    DIRECTION INPUT ;
    USE SIGNAL ;
    PORT
      LAYER M5 ;
        RECT  11.376 0 11.4 0.084 ;
    END
  END tw_d1[93]
  PIN tw_d1[94]
    DIRECTION INPUT ;
    USE SIGNAL ;
    PORT
      LAYER M5 ;
        RECT  11.472 0 11.496 0.084 ;
    END
  END tw_d1[94]
  PIN tw_d1[95]
    DIRECTION INPUT ;
    USE SIGNAL ;
    PORT
      LAYER M5 ;
        RECT  11.568 0 11.592 0.084 ;
    END
  END tw_d1[95]
  PIN tw_d1[96]
    DIRECTION INPUT ;
    USE SIGNAL ;
    PORT
      LAYER M5 ;
        RECT  11.664 0 11.688 0.084 ;
    END
  END tw_d1[96]
  PIN tw_d1[97]
    DIRECTION INPUT ;
    USE SIGNAL ;
    PORT
      LAYER M5 ;
        RECT  11.76 0 11.784 0.084 ;
    END
  END tw_d1[97]
  PIN tw_d1[98]
    DIRECTION INPUT ;
    USE SIGNAL ;
    PORT
      LAYER M5 ;
        RECT  11.856 0 11.88 0.084 ;
    END
  END tw_d1[98]
  PIN tw_d1[99]
    DIRECTION INPUT ;
    USE SIGNAL ;
    PORT
      LAYER M5 ;
        RECT  11.952 0 11.976 0.084 ;
    END
  END tw_d1[99]
  PIN tw_d1[9]
    DIRECTION INPUT ;
    USE SIGNAL ;
    PORT
      LAYER M5 ;
        RECT  201.456 0 201.48 0.084 ;
    END
  END tw_d1[9]
  PIN tw_kind[0]
    DIRECTION INPUT ;
    USE SIGNAL ;
    PORT
      LAYER M5 ;
        RECT  204.528 0 204.552 0.084 ;
    END
  END tw_kind[0]
  PIN tw_kind[1]
    DIRECTION INPUT ;
    USE SIGNAL ;
    PORT
      LAYER M5 ;
        RECT  204.624 0 204.648 0.084 ;
    END
  END tw_kind[1]
  PIN tw_we
    DIRECTION INPUT ;
    USE SIGNAL ;
    PORT
      LAYER M5 ;
        RECT  204.72 0 204.744 0.084 ;
    END
  END tw_we
  PIN VDD
    DIRECTION INOUT ;
    USE POWER ;
    PORT
      LAYER M5 ;
        RECT  252.756 4.311 252.876 349.929 ;
        RECT  248.436 4.311 248.556 349.929 ;
        RECT  244.116 4.311 244.236 349.929 ;
        RECT  239.796 4.311 239.916 349.929 ;
        RECT  235.476 4.311 235.596 349.929 ;
        RECT  231.156 4.311 231.276 349.929 ;
        RECT  226.836 4.311 226.956 349.929 ;
        RECT  222.516 4.311 222.636 349.929 ;
        RECT  218.196 4.311 218.316 349.929 ;
        RECT  213.876 4.311 213.996 349.929 ;
        RECT  209.556 4.311 209.676 349.929 ;
        RECT  205.236 4.311 205.356 349.929 ;
        RECT  200.916 4.311 201.036 349.929 ;
        RECT  196.596 4.311 196.716 349.929 ;
        RECT  192.276 4.311 192.396 349.929 ;
        RECT  187.956 4.311 188.076 349.929 ;
        RECT  183.636 4.311 183.756 349.929 ;
        RECT  179.316 4.311 179.436 349.929 ;
        RECT  174.996 4.311 175.116 349.929 ;
        RECT  170.676 4.311 170.796 349.929 ;
        RECT  166.356 4.311 166.476 349.929 ;
        RECT  162.036 4.311 162.156 349.929 ;
        RECT  157.716 4.311 157.836 349.929 ;
        RECT  153.396 4.311 153.516 349.929 ;
        RECT  149.076 4.311 149.196 349.929 ;
        RECT  144.756 4.311 144.876 349.929 ;
        RECT  140.436 4.311 140.556 349.929 ;
        RECT  136.116 4.311 136.236 349.929 ;
        RECT  131.796 4.311 131.916 349.929 ;
        RECT  127.476 4.311 127.596 349.929 ;
        RECT  123.156 4.311 123.276 349.929 ;
        RECT  118.836 4.311 118.956 349.929 ;
        RECT  114.516 4.311 114.636 349.929 ;
        RECT  110.196 4.311 110.316 349.929 ;
        RECT  105.876 4.311 105.996 349.929 ;
        RECT  101.556 4.311 101.676 349.929 ;
        RECT  97.236 4.311 97.356 349.929 ;
        RECT  92.916 4.311 93.036 349.929 ;
        RECT  88.596 4.311 88.716 349.929 ;
        RECT  84.276 4.311 84.396 349.929 ;
        RECT  79.956 4.311 80.076 349.929 ;
        RECT  75.636 4.311 75.756 349.929 ;
        RECT  71.316 4.311 71.436 349.929 ;
        RECT  66.996 4.311 67.116 349.929 ;
        RECT  62.676 4.311 62.796 349.929 ;
        RECT  58.356 4.311 58.476 349.929 ;
        RECT  54.036 4.311 54.156 349.929 ;
        RECT  49.716 4.311 49.836 349.929 ;
        RECT  45.396 4.311 45.516 349.929 ;
        RECT  41.076 4.311 41.196 349.929 ;
        RECT  36.756 4.311 36.876 349.929 ;
        RECT  32.436 4.311 32.556 349.929 ;
        RECT  28.116 4.311 28.236 349.929 ;
        RECT  23.796 4.311 23.916 349.929 ;
        RECT  19.476 4.311 19.596 349.929 ;
        RECT  15.156 4.311 15.276 349.929 ;
        RECT  10.836 4.311 10.956 349.929 ;
        RECT  6.516 4.311 6.636 349.929 ;
    END
  END VDD
  PIN VSS
    DIRECTION INOUT ;
    USE GROUND ;
    PORT
      LAYER M5 ;
        RECT  252.564 4.297 252.684 349.943 ;
        RECT  248.244 4.297 248.364 349.943 ;
        RECT  243.924 4.297 244.044 349.943 ;
        RECT  239.604 4.297 239.724 349.943 ;
        RECT  235.284 4.297 235.404 349.943 ;
        RECT  230.964 4.297 231.084 349.943 ;
        RECT  226.644 4.297 226.764 349.943 ;
        RECT  222.324 4.297 222.444 349.943 ;
        RECT  218.004 4.297 218.124 349.943 ;
        RECT  213.684 4.297 213.804 349.943 ;
        RECT  209.364 4.297 209.484 349.943 ;
        RECT  205.044 4.297 205.164 349.943 ;
        RECT  200.724 4.297 200.844 349.943 ;
        RECT  196.404 4.297 196.524 349.943 ;
        RECT  192.084 4.297 192.204 349.943 ;
        RECT  187.764 4.297 187.884 349.943 ;
        RECT  183.444 4.297 183.564 349.943 ;
        RECT  179.124 4.297 179.244 349.943 ;
        RECT  174.804 4.297 174.924 349.943 ;
        RECT  170.484 4.297 170.604 349.943 ;
        RECT  166.164 4.297 166.284 349.943 ;
        RECT  161.844 4.297 161.964 349.943 ;
        RECT  157.524 4.297 157.644 349.943 ;
        RECT  153.204 4.297 153.324 349.943 ;
        RECT  148.884 4.297 149.004 349.943 ;
        RECT  144.564 4.297 144.684 349.943 ;
        RECT  140.244 4.297 140.364 349.943 ;
        RECT  135.924 4.297 136.044 349.943 ;
        RECT  131.604 4.297 131.724 349.943 ;
        RECT  127.284 4.297 127.404 349.943 ;
        RECT  122.964 4.297 123.084 349.943 ;
        RECT  118.644 4.297 118.764 349.943 ;
        RECT  114.324 4.297 114.444 349.943 ;
        RECT  110.004 4.297 110.124 349.943 ;
        RECT  105.684 4.297 105.804 349.943 ;
        RECT  101.364 4.297 101.484 349.943 ;
        RECT  97.044 4.297 97.164 349.943 ;
        RECT  92.724 4.297 92.844 349.943 ;
        RECT  88.404 4.297 88.524 349.943 ;
        RECT  84.084 4.297 84.204 349.943 ;
        RECT  79.764 4.297 79.884 349.943 ;
        RECT  75.444 4.297 75.564 349.943 ;
        RECT  71.124 4.297 71.244 349.943 ;
        RECT  66.804 4.297 66.924 349.943 ;
        RECT  62.484 4.297 62.604 349.943 ;
        RECT  58.164 4.297 58.284 349.943 ;
        RECT  53.844 4.297 53.964 349.943 ;
        RECT  49.524 4.297 49.644 349.943 ;
        RECT  45.204 4.297 45.324 349.943 ;
        RECT  40.884 4.297 41.004 349.943 ;
        RECT  36.564 4.297 36.684 349.943 ;
        RECT  32.244 4.297 32.364 349.943 ;
        RECT  27.924 4.297 28.044 349.943 ;
        RECT  23.604 4.297 23.724 349.943 ;
        RECT  19.284 4.297 19.404 349.943 ;
        RECT  14.964 4.297 15.084 349.943 ;
        RECT  10.644 4.297 10.764 349.943 ;
        RECT  6.324 4.297 6.444 349.943 ;
    END
  END VSS
  OBS
    LAYER RVTN ;
     RECT  4.32 0 259.2 349.943 ;
    LAYER RVTP ;
     RECT  4.32 0 259.2 349.943 ;
    LAYER M1 ;
     RECT  4.32 0 259.2 349.943 ;
    LAYER M2 ;
     RECT  4.32 0 259.2 349.943 ;
    LAYER M3 ;
     RECT  4.32 0 259.2 349.943 ;
    LAYER M4 ;
     RECT  4.32 0 259.2 349.943 ;
    LAYER M5 ;
     RECT  4.32 0 259.2 349.943 ;
  END
END qfd_dv_s8x_prog
END LIBRARY
